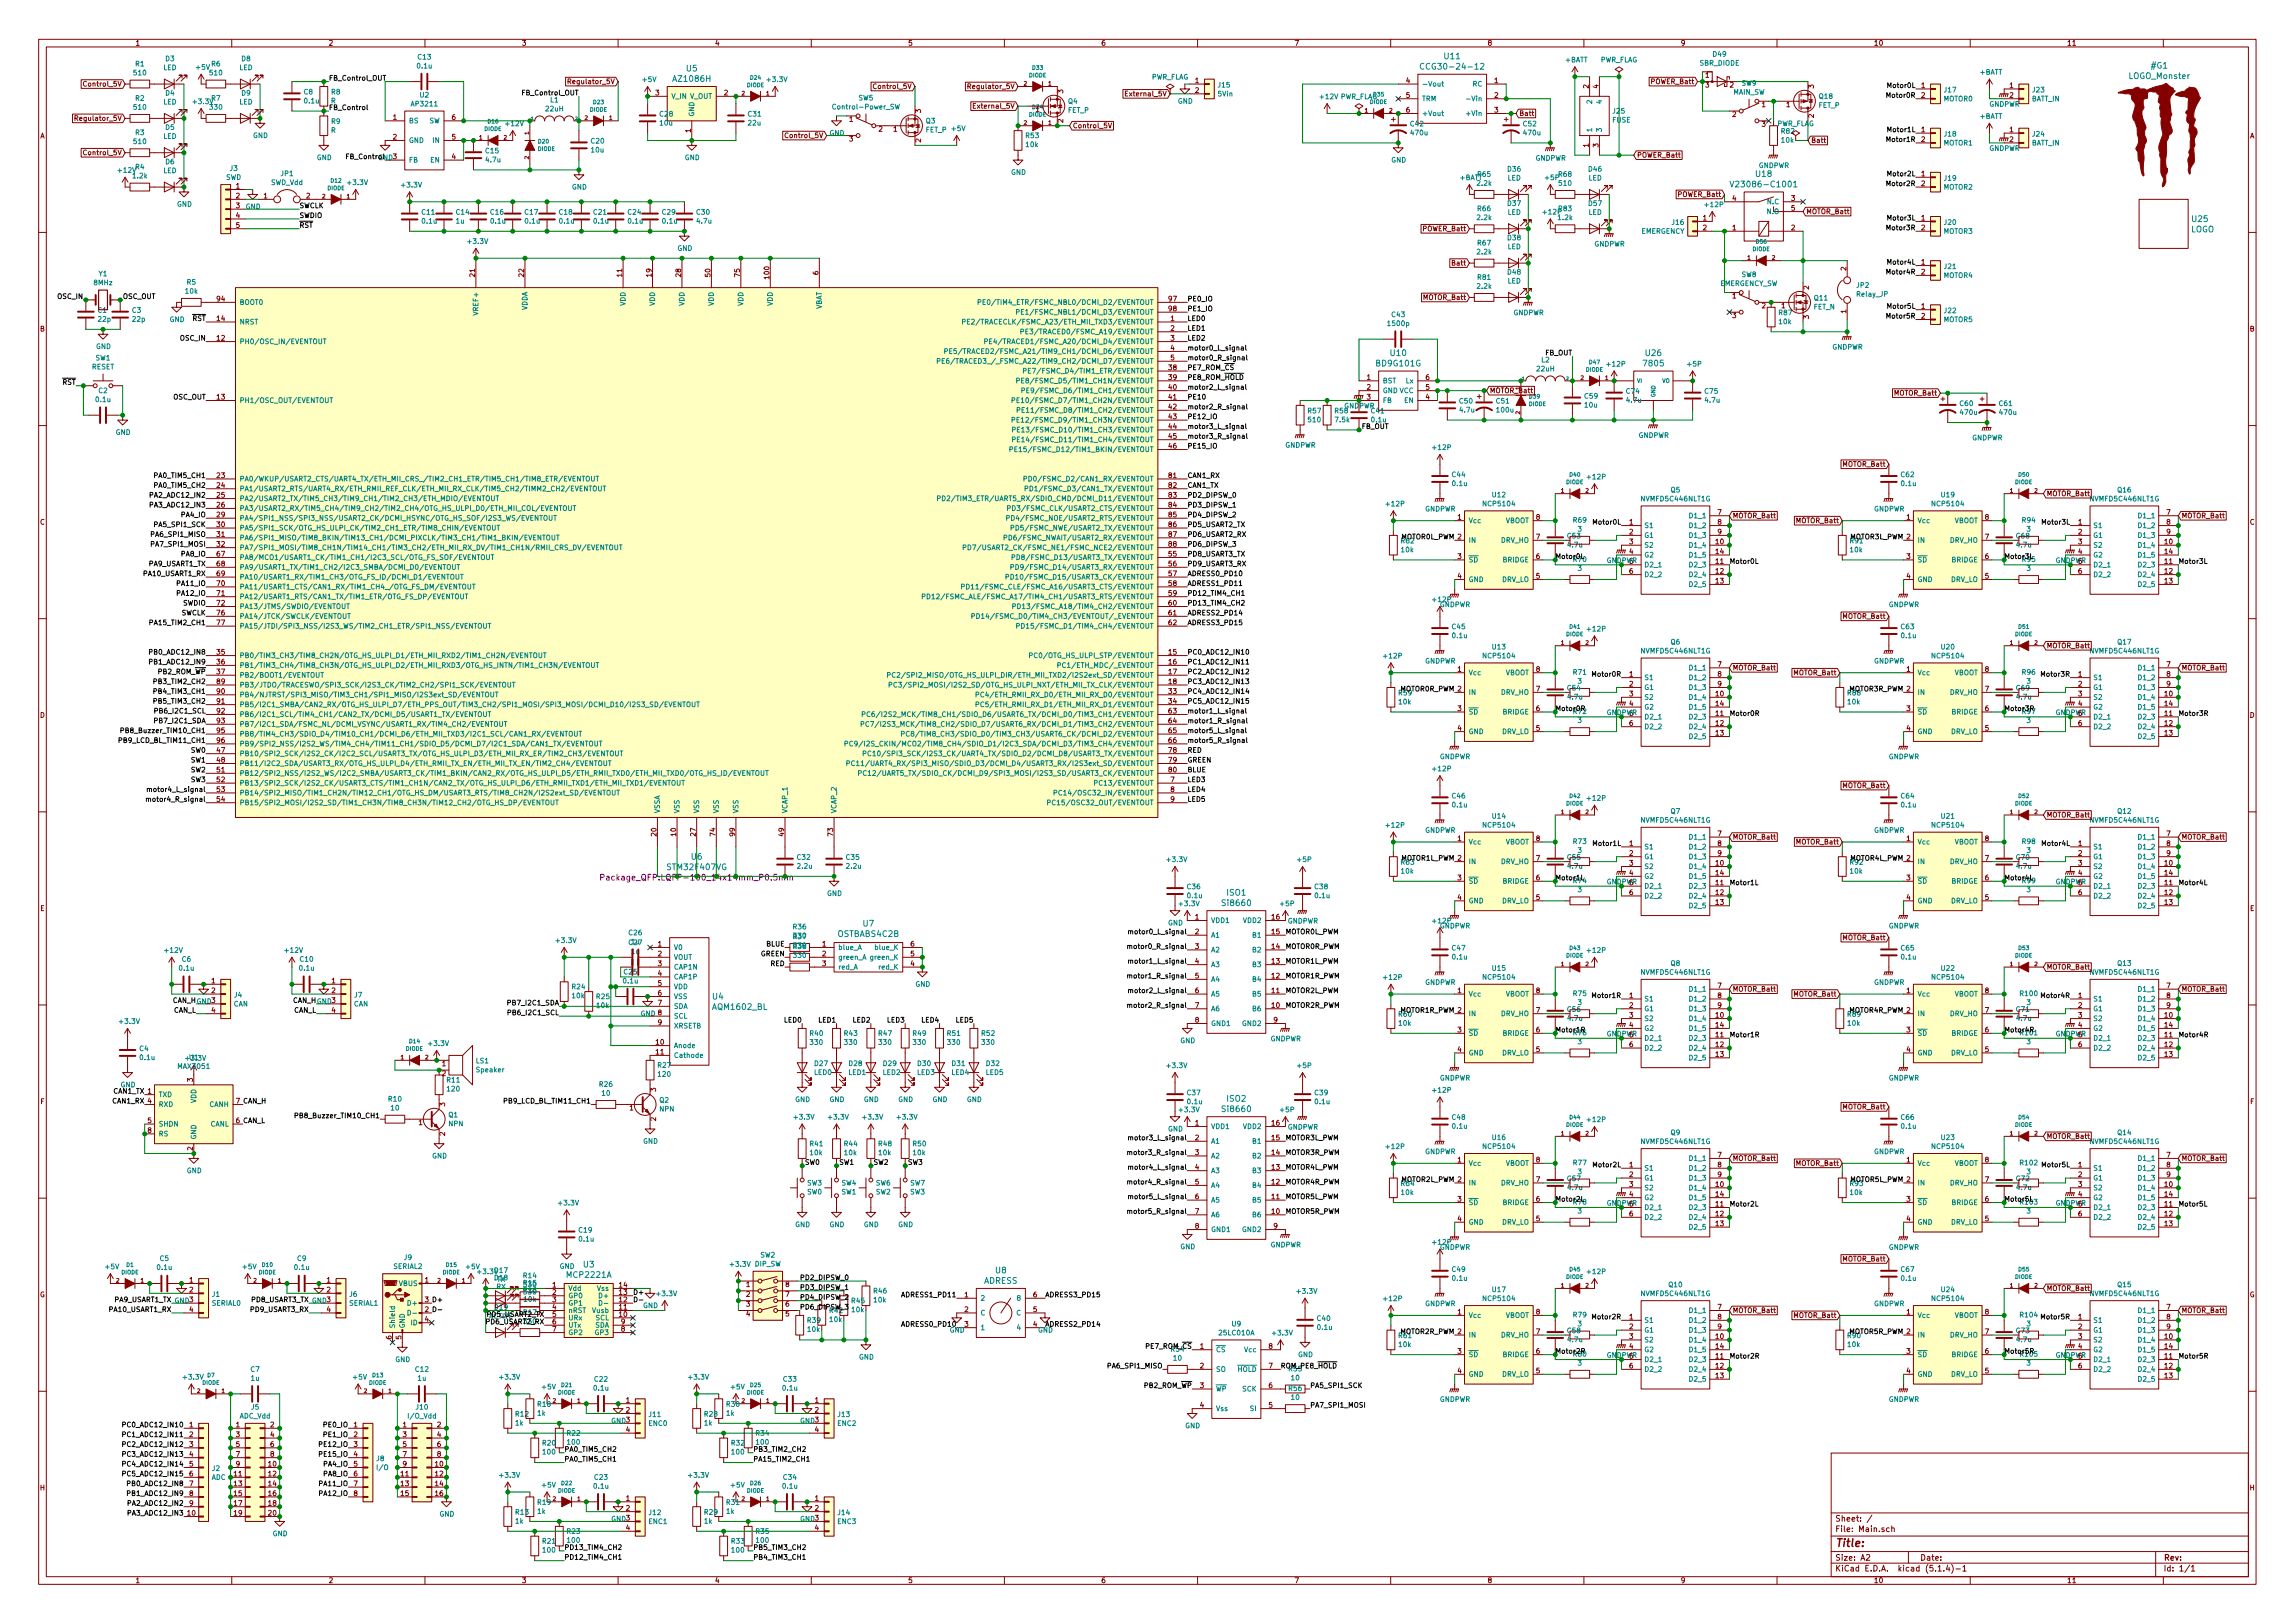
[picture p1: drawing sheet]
<svg xmlns="http://www.w3.org/2000/svg" width="594mm" height="420mm" viewBox="0 0 594 420" stroke-linecap="round" stroke-linejoin="round" font-family="sans-serif">
<defs><g id="words">
<text font-size="2.8" fill="#840000" x="475" y="400.4">Title:</text>
<g font-size="2.1" fill="#008484">
<text x="374" y="15.3">U11</text>
<text x="556.9" y="17.7">#G1</text>
<text x="174.5" y="21.2">AZ1086H</text>
<text x="177.7" y="18.5">U5</text>
<text x="369.3" y="18">CCG30-24-12</text>
<text x="551.1" y="20.4">LOGO_Monster</text>
<text x="454.6" y="45.8">U18</text>
<text x="449.4" y="48.5">V23086-C1001</text>
<text x="567.5" y="57.4">U25</text>
<text x="567.1" y="60.1">LOGO</text>
<text x="356.4" y="94.8">BD9G101G</text>
<text x="360" y="92.1">U10</text>
<text x="425.6" y="94.8">7805</text>
<text x="426.1" y="92.1">U26</text>
<text x="173" y="225.2">STM32F407VG</text>
<text x="179" y="222.5">U6</text>
<text x="317.6" y="231.8">ISO1</text>
<text x="223.4" y="239.8">U7</text>
<text x="316.7" y="234.5">Si8660</text>
<text x="216.9" y="242.5">OSTBABS4C2B</text>
<text x="184.5" y="258.7">U4</text>
<text x="184.7" y="261.4">AQM1602_BL</text>
<text x="316.7" y="287.9">Si8660</text>
<text x="317.6" y="285.2">ISO2</text>
<text x="151.1" y="328.1">U3</text>
<text x="257.7" y="329.6">U8</text>
<text x="146.9" y="330.8">MCP2221A</text>
<text x="254.7" y="332.3">ADRESS</text>
</g>
<text font-size="2.1" fill="#008400" x="157.9" y="227.9">Package_QFP:LQFP-100_14x14mm_P0.5mm</text>
<g font-size="2.1" fill="#840000">
<text x="475" y="393.9">Sheet: /</text>
<text x="475" y="396.6">File: Main.sch</text>
<text x="475" y="406.8">KiCad E.D.A. kicad (5.1.4)-1</text>
<text x="475" y="404">Size: A2</text>
<text x="497" y="404">Date:</text>
<text x="560" y="404">Rev:</text>
<text x="560" y="406.8">Id: 1/1</text>
</g>
<g font-size="1.8" fill="#840000">
<text x="35" y="11.8">1</text>
<text x="85" y="11.8">2</text>
<text x="135" y="11.8">3</text>
<text x="185" y="11.8">4</text>
<text x="235" y="11.8">5</text>
<text x="285" y="11.8">6</text>
<text x="335" y="11.8">7</text>
<text x="385" y="11.8">8</text>
<text x="435" y="11.8">9</text>
<text x="485" y="11.8">10</text>
<text x="535" y="11.8">11</text>
<text x="22.2" y="22.4">Control_5V</text>
<text x="147.8" y="21.8">Regulator_5V</text>
<text x="226.6" y="23">Control_5V</text>
<text x="251.3" y="23">Regulator_5V</text>
<text x="309.4" y="21.5">1</text>
<text x="364" y="21.5">4</text>
<text x="386.9" y="21.5">1</text>
<text x="411.2" y="22.9" transform="rotate(-90 411.2 22.9)">2</text>
<text x="413.8" y="22.9" transform="rotate(-90 413.8 22.9)">4</text>
<text x="427.5" y="21.8">POWER_Batt</text>
<text x="441.5" y="20.1">1</text>
<text x="441.5" y="22.6">3</text>
<text x="447.8" y="22.6">2</text>
<text x="469.5" y="22.9" transform="rotate(-90 469.5 22.9)">3</text>
<text x="497.4" y="22.8">1</text>
<text x="520.2" y="22.8">1</text>
<text x="169.7" y="24.7">3</text>
<text x="187.5" y="24.7">2</text>
<text x="238.4" y="29.2" transform="rotate(-90 238.4 29.2)">3</text>
<text x="252.6" y="28.1">External_5V</text>
<text x="268.1" y="29">1</text>
<text x="275.2" y="24.1" transform="rotate(-90 275.2 24.1)">3</text>
<text x="292" y="24.9">External_5V</text>
<text x="309.4" y="24">2</text>
<text x="364" y="25.3">5</text>
<text x="364" y="29.1">6</text>
<text x="386.9" y="25.3">2</text>
<text x="386.9" y="29.1">3</text>
<text x="456.1" y="27.7">1</text>
<text x="462.4" y="27.7">1</text>
<text x="497.4" y="25.3">2</text>
<text x="520.2" y="25.3">2</text>
<text x="10.4" y="35.8">A</text>
<text x="20.2" y="31.3">Regulator_5V</text>
<text x="101.8" y="31">1</text>
<text x="117" y="31">6</text>
<text x="178.8" y="34.3" transform="rotate(-90 178.8 34.3)">1</text>
<text x="203.8" y="35.7">Control_5V</text>
<text x="219.9" y="31.5">1</text>
<text x="227.5" y="34.1">2</text>
<text x="231.3" y="34.1">1</text>
<text x="275.2" y="31.8" transform="rotate(-90 275.2 31.8)">2</text>
<text x="277.6" y="33.2">Control_5V</text>
<text x="393.2" y="30">Batt</text>
<text x="448.5" y="30.3">2</text>
<text x="456.1" y="32.8">3</text>
<text x="469.5" y="30.5" transform="rotate(-90 469.5 30.5)">2</text>
<text x="497.4" y="34.2">1</text>
<text x="520.2" y="34.2">1</text>
<text x="582.4" y="35.8">A</text>
<text x="22.2" y="40.2">Control_5V</text>
<text x="101.8" y="36.1">2</text>
<text x="117" y="41.2">4</text>
<text x="117" y="36.1">5</text>
<text x="219.9" y="36.6">3</text>
<text x="238.4" y="36.8" transform="rotate(-90 238.4 36.8)">2</text>
<text x="411.2" y="38.1" transform="rotate(-90 411.2 38.1)">1</text>
<text x="413.8" y="38.1" transform="rotate(-90 413.8 38.1)">3</text>
<text x="423.7" y="40.8">POWER_Batt</text>
<text x="468.8" y="37">Batt</text>
<text x="497.4" y="36.7">2</text>
<text x="520.2" y="36.7">2</text>
<text x="497.4" y="45.6">1</text>
<text x="61.1" y="48.8">1</text>
<text x="61.1" y="51.4">2</text>
<text x="61.1" y="53.9">3</text>
<text x="68.3" y="51.4">1</text>
<text x="79.3" y="51.4">2</text>
<text x="434.5" y="51">POWER_Batt</text>
<text x="448.5" y="52">4</text>
<text x="463.7" y="52">3</text>
<text x="497.4" y="48.2">2</text>
<text x="61.1" y="56.4">4</text>
<text x="61.1" y="59">5</text>
<text x="368.5" y="59.9">POWER_Batt</text>
<text x="440.8" y="57.1">1</text>
<text x="440.8" y="59.6">2</text>
<text x="448.5" y="59.6">1</text>
<text x="463.7" y="59.6">2</text>
<text x="463.7" y="54.5">5</text>
<text x="467.5" y="55.4">MOTOR_Batt</text>
<text x="497.4" y="57.1">1</text>
<text x="497.4" y="59.6">2</text>
<text x="122.9" y="71.6" transform="rotate(-90 122.9 71.6)">21</text>
<text x="135.6" y="71.6" transform="rotate(-90 135.6 71.6)">22</text>
<text x="161" y="71.6" transform="rotate(-90 161 71.6)">11</text>
<text x="168.7" y="71.6" transform="rotate(-90 168.7 71.6)">19</text>
<text x="176.3" y="71.6" transform="rotate(-90 176.3 71.6)">28</text>
<text x="183.9" y="71.6" transform="rotate(-90 183.9 71.6)">50</text>
<text x="191.5" y="71.6" transform="rotate(-90 191.5 71.6)">75</text>
<text x="211.8" y="71.1" transform="rotate(-90 211.8 71.1)">6</text>
<text x="376.1" y="68.7">Batt</text>
<text x="477.9" y="70" transform="rotate(-90 477.9 70)">2</text>
<text x="497.4" y="68.5">1</text>
<text x="497.4" y="71">2</text>
<text x="199.1" y="72.1" transform="rotate(-90 199.1 72.1)">100</text>
<text x="368.6" y="77.6">MOTOR_Batt</text>
<text x="448.5" y="77.3">1</text>
<text x="468.2" y="74.9" transform="rotate(-90 468.2 74.9)">2</text>
<text x="56.2" y="83.1">14</text>
<text x="56.2" y="78">94</text>
<text x="302.6" y="78">97</text>
<text x="302.6" y="80.6">98</text>
<text x="303" y="83.1">1</text>
<text x="448.5" y="82.3">3</text>
<text x="456.1" y="79.8">2</text>
<text x="461.2" y="79.8">1</text>
<text x="468.2" y="82.6" transform="rotate(-90 468.2 82.6)">3</text>
<text x="477.9" y="81.1" transform="rotate(-90 477.9 81.1)">1</text>
<text x="497.4" y="79.9">1</text>
<text x="497.4" y="82.5">2</text>
<text x="10.4" y="85.8">B</text>
<text x="56.2" y="88.2">12</text>
<text x="303" y="85.6">2</text>
<text x="303" y="88.2">3</text>
<text x="582.4" y="85.8">B</text>
<text x="302.6" y="95.8">38</text>
<text x="303" y="90.7">4</text>
<text x="303" y="93.3">5</text>
<text x="302.6" y="98.3">39</text>
<text x="302.6" y="100.9">40</text>
<text x="353.8" y="98.3">1</text>
<text x="353.8" y="100.9">2</text>
<text x="369.1" y="100.9">5</text>
<text x="369.1" y="98.3">6</text>
<text x="385.6" y="101.8">MOTOR_Batt</text>
<text x="56.2" y="103.4">13</text>
<text x="302.6" y="103.4">41</text>
<text x="302.6" y="106">42</text>
<text x="353.8" y="103.4">3</text>
<text x="369.1" y="103.4">4</text>
<text x="490.5" y="102.4">MOTOR_Batt</text>
<text x="302.6" y="108.5">43</text>
<text x="302.6" y="111">44</text>
<text x="302.6" y="113.6">45</text>
<text x="302.6" y="116.1">46</text>
<text x="56.2" y="123.7">23</text>
<text x="302.6" y="123.7">81</text>
<text x="477.2" y="120.8">MOTOR_Batt</text>
<text x="56.2" y="126.3">24</text>
<text x="56.2" y="128.8">25</text>
<text x="56.2" y="131.4">26</text>
<text x="302.6" y="126.3">82</text>
<text x="302.6" y="128.8">83</text>
<text x="302.6" y="131.4">84</text>
<text x="529.7" y="128.4">MOTOR_Batt</text>
<text x="10.4" y="135.8">C</text>
<text x="56.2" y="133.9">29</text>
<text x="56.2" y="136.4">30</text>
<text x="302.6" y="133.9">85</text>
<text x="302.6" y="136.4">86</text>
<text x="377.3" y="134.5">1</text>
<text x="397.7" y="134.5">8</text>
<text x="421.8" y="135.8">1</text>
<text x="444.7" y="133.3">7</text>
<text x="444.7" y="135.8">8</text>
<text x="448.5" y="134.2">MOTOR_Batt</text>
<text x="465.1" y="135.4">MOTOR_Batt</text>
<text x="493.5" y="134.5">1</text>
<text x="513.9" y="134.5">8</text>
<text x="538" y="135.8">1</text>
<text x="560.9" y="133.3">7</text>
<text x="560.9" y="135.8">8</text>
<text x="564.7" y="134.2">MOTOR_Batt</text>
<text x="582.4" y="135.8">C</text>
<text x="56.2" y="139">31</text>
<text x="56.2" y="141.5">32</text>
<text x="302.6" y="139">87</text>
<text x="302.6" y="141.5">88</text>
<text x="397.7" y="139.6">7</text>
<text x="421.8" y="138.3">2</text>
<text x="421.8" y="140.9">3</text>
<text x="421.8" y="143.4">4</text>
<text x="444.2" y="140.9">10</text>
<text x="444.2" y="143.4">14</text>
<text x="444.7" y="138.3">9</text>
<text x="513.9" y="139.6">7</text>
<text x="538" y="138.3">2</text>
<text x="538" y="140.9">3</text>
<text x="538" y="143.4">4</text>
<text x="560.4" y="140.9">10</text>
<text x="560.4" y="143.4">14</text>
<text x="560.9" y="138.3">9</text>
<text x="56.2" y="144.1">67</text>
<text x="56.2" y="146.6">68</text>
<text x="56.2" y="149.1">69</text>
<text x="302.6" y="144.1">55</text>
<text x="302.6" y="146.6">56</text>
<text x="302.6" y="149.1">57</text>
<text x="377.3" y="144.7">3</text>
<text x="377.3" y="149.8">4</text>
<text x="397.7" y="149.8">5</text>
<text x="397.7" y="144.7">6</text>
<text x="421.8" y="146">5</text>
<text x="421.8" y="148.5">6</text>
<text x="444.2" y="146">11</text>
<text x="444.2" y="148.5">12</text>
<text x="493.5" y="144.7">3</text>
<text x="493.5" y="149.8">4</text>
<text x="513.9" y="149.8">5</text>
<text x="513.9" y="144.7">6</text>
<text x="538" y="146">5</text>
<text x="538" y="148.5">6</text>
<text x="560.4" y="146">11</text>
<text x="560.4" y="148.5">12</text>
<text x="56.2" y="151.7">70</text>
<text x="56.2" y="154.2">71</text>
<text x="302.6" y="151.7">58</text>
<text x="302.6" y="154.2">59</text>
<text x="444.2" y="151">13</text>
<text x="560.4" y="151">13</text>
<text x="56.2" y="156.8">72</text>
<text x="56.2" y="159.3">76</text>
<text x="56.2" y="161.8">77</text>
<text x="302.6" y="156.8">60</text>
<text x="302.6" y="159.3">61</text>
<text x="302.6" y="161.8">62</text>
<text x="477.2" y="160.2">MOTOR_Batt</text>
<text x="529.7" y="167.8">MOTOR_Batt</text>
<text x="56.2" y="169.5">35</text>
<text x="56.2" y="172">36</text>
<text x="302.6" y="169.5">15</text>
<text x="302.6" y="172">16</text>
<text x="377.3" y="173.9">1</text>
<text x="397.7" y="173.9">8</text>
<text x="444.7" y="172.6">7</text>
<text x="448.5" y="173.5">MOTOR_Batt</text>
<text x="493.5" y="173.9">1</text>
<text x="513.9" y="173.9">8</text>
<text x="560.9" y="172.6">7</text>
<text x="564.7" y="173.5">MOTOR_Batt</text>
<text x="56.2" y="174.5">37</text>
<text x="56.2" y="177.1">89</text>
<text x="56.2" y="179.6">90</text>
<text x="302.6" y="174.5">17</text>
<text x="302.6" y="177.1">18</text>
<text x="302.6" y="179.6">33</text>
<text x="397.7" y="179">7</text>
<text x="421.8" y="175.2">1</text>
<text x="421.8" y="177.7">2</text>
<text x="444.7" y="175.2">8</text>
<text x="444.7" y="177.7">9</text>
<text x="464.5" y="174.8">MOTOR_Batt</text>
<text x="513.9" y="179">7</text>
<text x="538" y="175.2">1</text>
<text x="538" y="177.7">2</text>
<text x="560.9" y="175.2">8</text>
<text x="560.9" y="177.7">9</text>
<text x="10.4" y="185.8">D</text>
<text x="56.2" y="182.2">91</text>
<text x="56.2" y="184.7">92</text>
<text x="302.6" y="182.2">34</text>
<text x="302.6" y="184.7">63</text>
<text x="377.3" y="184.1">3</text>
<text x="397.7" y="184.1">6</text>
<text x="421.8" y="180.3">3</text>
<text x="421.8" y="182.8">4</text>
<text x="421.8" y="185.3">5</text>
<text x="444.2" y="180.3">10</text>
<text x="444.2" y="185.3">11</text>
<text x="444.2" y="182.8">14</text>
<text x="493.5" y="184.1">3</text>
<text x="513.9" y="184.1">6</text>
<text x="538" y="180.3">3</text>
<text x="538" y="182.8">4</text>
<text x="538" y="185.3">5</text>
<text x="560.4" y="180.3">10</text>
<text x="560.4" y="185.3">11</text>
<text x="560.4" y="182.8">14</text>
<text x="582.4" y="185.8">D</text>
<text x="56.2" y="187.2">93</text>
<text x="56.2" y="189.8">95</text>
<text x="302.6" y="187.2">64</text>
<text x="302.6" y="189.8">65</text>
<text x="377.3" y="189.1">4</text>
<text x="397.7" y="189.1">5</text>
<text x="421.8" y="187.9">6</text>
<text x="444.2" y="187.9">12</text>
<text x="444.2" y="190.4">13</text>
<text x="493.5" y="189.1">4</text>
<text x="513.9" y="189.1">5</text>
<text x="538" y="187.9">6</text>
<text x="560.4" y="187.9">12</text>
<text x="560.4" y="190.4">13</text>
<text x="56.2" y="194.9">47</text>
<text x="56.2" y="197.4">48</text>
<text x="56.2" y="192.3">96</text>
<text x="302.6" y="192.3">66</text>
<text x="302.6" y="194.9">78</text>
<text x="302.6" y="197.4">79</text>
<text x="56.2" y="199.9">51</text>
<text x="56.2" y="202.5">52</text>
<text x="302.6" y="199.9">80</text>
<text x="303" y="202.5">7</text>
<text x="56.2" y="205">53</text>
<text x="56.2" y="207.6">54</text>
<text x="303" y="205">8</text>
<text x="303" y="207.6">9</text>
<text x="477.2" y="204">MOTOR_Batt</text>
<text x="529.7" y="211.6">MOTOR_Batt</text>
<text x="169.9" y="216.4" transform="rotate(-90 169.9 216.4)">20</text>
<text x="175" y="216.4" transform="rotate(-90 175 216.4)">10</text>
<text x="180.1" y="216.4" transform="rotate(-90 180.1 216.4)">27</text>
<text x="185.2" y="216.4" transform="rotate(-90 185.2 216.4)">74</text>
<text x="190.2" y="216.4" transform="rotate(-90 190.2 216.4)">99</text>
<text x="202.9" y="216.4" transform="rotate(-90 202.9 216.4)">49</text>
<text x="215.6" y="216.4" transform="rotate(-90 215.6 216.4)">73</text>
<text x="377.3" y="217.7">1</text>
<text x="397.7" y="217.7">8</text>
<text x="421.8" y="219">1</text>
<text x="421.8" y="221.5">2</text>
<text x="444.7" y="216.5">7</text>
<text x="444.7" y="219">8</text>
<text x="444.7" y="221.5">9</text>
<text x="448.5" y="217.3">MOTOR_Batt</text>
<text x="465.1" y="218.6">MOTOR_Batt</text>
<text x="493.5" y="217.7">1</text>
<text x="513.9" y="217.7">8</text>
<text x="538" y="219">1</text>
<text x="538" y="221.5">2</text>
<text x="560.9" y="216.5">7</text>
<text x="560.9" y="219">8</text>
<text x="560.9" y="221.5">9</text>
<text x="564.7" y="217.3">MOTOR_Batt</text>
<text x="377.3" y="227.9">3</text>
<text x="397.7" y="227.9">6</text>
<text x="397.7" y="222.8">7</text>
<text x="421.8" y="224.1">3</text>
<text x="421.8" y="226.6">4</text>
<text x="444.2" y="224.1">10</text>
<text x="444.2" y="226.6">14</text>
<text x="493.5" y="227.9">3</text>
<text x="513.9" y="227.9">6</text>
<text x="513.9" y="222.8">7</text>
<text x="538" y="224.1">3</text>
<text x="538" y="226.6">4</text>
<text x="560.4" y="224.1">10</text>
<text x="560.4" y="226.6">14</text>
<text x="377.3" y="233">4</text>
<text x="397.7" y="233">5</text>
<text x="421.8" y="229.2">5</text>
<text x="421.8" y="231.7">6</text>
<text x="444.2" y="229.2">11</text>
<text x="444.2" y="231.7">12</text>
<text x="493.5" y="233">4</text>
<text x="513.9" y="233">5</text>
<text x="538" y="229.2">5</text>
<text x="538" y="231.7">6</text>
<text x="560.4" y="229.2">11</text>
<text x="560.4" y="231.7">12</text>
<text x="10.4" y="235.8">E</text>
<text x="309.4" y="238">1</text>
<text x="329.2" y="238">16</text>
<text x="444.2" y="234.2">13</text>
<text x="560.4" y="234.2">13</text>
<text x="582.4" y="235.8">E</text>
<text x="170.3" y="245">1</text>
<text x="212.9" y="245">1</text>
<text x="235.7" y="245">6</text>
<text x="309.4" y="241.9">2</text>
<text x="309.4" y="245.7">3</text>
<text x="329.2" y="245.7">14</text>
<text x="329.2" y="241.9">15</text>
<text x="477.2" y="243.4">MOTOR_Batt</text>
<text x="170.3" y="247.6">2</text>
<text x="170.3" y="250.1">3</text>
<text x="212.9" y="247.6">2</text>
<text x="212.9" y="250.1">3</text>
<text x="235.7" y="250.1">4</text>
<text x="235.7" y="247.6">5</text>
<text x="309.4" y="249.5">4</text>
<text x="329.2" y="249.5">13</text>
<text x="529.7" y="251">MOTOR_Batt</text>
<text x="54.8" y="254.6">1</text>
<text x="54.8" y="257.1">2</text>
<text x="85.9" y="254.6">1</text>
<text x="85.9" y="257.1">2</text>
<text x="170.3" y="252.6">4</text>
<text x="170.3" y="255.2">5</text>
<text x="170.3" y="257.7">6</text>
<text x="309.4" y="253.3">5</text>
<text x="309.4" y="257.1">6</text>
<text x="329.2" y="257.1">11</text>
<text x="329.2" y="253.3">12</text>
<text x="377.3" y="257.1">1</text>
<text x="397.7" y="257.1">8</text>
<text x="444.7" y="255.8">7</text>
<text x="448.5" y="256.7">MOTOR_Batt</text>
<text x="464.5" y="258">MOTOR_Batt</text>
<text x="493.5" y="257.1">1</text>
<text x="513.9" y="257.1">8</text>
<text x="560.9" y="255.8">7</text>
<text x="564.7" y="256.7">MOTOR_Batt</text>
<text x="54.8" y="262.2">4</text>
<text x="85.9" y="262.2">4</text>
<text x="165.8" y="263.1">GND 8</text>
<text x="170.3" y="260.3">7</text>
<text x="309.4" y="260.9">7</text>
<text x="329.2" y="260.9">10</text>
<text x="397.7" y="262.2">7</text>
<text x="421.8" y="258.4">1</text>
<text x="421.8" y="260.9">2</text>
<text x="421.8" y="263.4">3</text>
<text x="444.2" y="263.4">10</text>
<text x="444.7" y="258.4">8</text>
<text x="444.7" y="260.9">9</text>
<text x="513.9" y="262.2">7</text>
<text x="538" y="258.4">1</text>
<text x="538" y="260.9">2</text>
<text x="538" y="263.4">3</text>
<text x="560.4" y="263.4">10</text>
<text x="560.9" y="258.4">8</text>
<text x="560.9" y="260.9">9</text>
<text x="170.3" y="265.3">9</text>
<text x="309.4" y="264.7">8</text>
<text x="329.7" y="264.7">9</text>
<text x="377.3" y="267.3">3</text>
<text x="397.7" y="267.3">6</text>
<text x="421.8" y="266">4</text>
<text x="421.8" y="268.5">5</text>
<text x="444.2" y="268.5">11</text>
<text x="444.2" y="266">14</text>
<text x="493.5" y="267.3">3</text>
<text x="513.9" y="267.3">6</text>
<text x="538" y="266">4</text>
<text x="538" y="268.5">5</text>
<text x="560.4" y="268.5">11</text>
<text x="560.4" y="266">14</text>
<text x="169.8" y="270.4">10</text>
<text x="169.8" y="273">11</text>
<text x="377.3" y="272.3">4</text>
<text x="397.7" y="272.3">5</text>
<text x="421.8" y="271.1">6</text>
<text x="444.2" y="271.1">12</text>
<text x="444.2" y="273.6">13</text>
<text x="493.5" y="272.3">4</text>
<text x="513.9" y="272.3">5</text>
<text x="538" y="271.1">6</text>
<text x="560.4" y="271.1">12</text>
<text x="560.4" y="273.6">13</text>
<text x="49.9" y="280.1" transform="rotate(-90 49.9 280.1)">3</text>
<text x="114.5" y="276">1</text>
<text x="114.5" y="278.6">2</text>
<text x="10.5" y="285.8">F</text>
<text x="115.2" y="286.4" transform="rotate(-90 115.2 286.4)">3</text>
<text x="163" y="287.4">1</text>
<text x="169.8" y="282.6" transform="rotate(-90 169.8 282.6)">3</text>
<text x="477.2" y="287.2">MOTOR_Batt</text>
<text x="582.5" y="285.8">F</text>
<text x="38.3" y="290.7">5</text>
<text x="38.3" y="293.3">8</text>
<text x="108.4" y="291.3">1</text>
<text x="169.8" y="290.2" transform="rotate(-90 169.8 290.2)">2</text>
<text x="309.4" y="291.4">1</text>
<text x="329.2" y="291.4">16</text>
<text x="49.9" y="297.8" transform="rotate(-90 49.9 297.8)">2</text>
<text x="115.2" y="294" transform="rotate(-90 115.2 294)">2</text>
<text x="309.4" y="295.2">2</text>
<text x="309.4" y="299">3</text>
<text x="329.2" y="299">14</text>
<text x="329.2" y="295.2">15</text>
<text x="444.7" y="299.6">7</text>
<text x="529.7" y="294.8">MOTOR_Batt</text>
<text x="560.9" y="299.6">7</text>
<text x="309.4" y="302.8">4</text>
<text x="329.2" y="302.8">13</text>
<text x="377.3" y="300.9">1</text>
<text x="397.7" y="306">7</text>
<text x="397.7" y="300.9">8</text>
<text x="421.8" y="302.2">1</text>
<text x="421.8" y="304.7">2</text>
<text x="444.7" y="302.2">8</text>
<text x="444.7" y="304.7">9</text>
<text x="448.5" y="300.5">MOTOR_Batt</text>
<text x="465.1" y="301.8">MOTOR_Batt</text>
<text x="493.5" y="300.9">1</text>
<text x="513.9" y="306">7</text>
<text x="513.9" y="300.9">8</text>
<text x="538" y="302.2">1</text>
<text x="538" y="304.7">2</text>
<text x="560.9" y="302.2">8</text>
<text x="560.9" y="304.7">9</text>
<text x="564.7" y="300.5">MOTOR_Batt</text>
<text x="309.4" y="306.6">5</text>
<text x="309.4" y="310.4">6</text>
<text x="329.2" y="310.4">11</text>
<text x="329.2" y="306.6">12</text>
<text x="377.3" y="311.1">3</text>
<text x="397.7" y="311.1">6</text>
<text x="421.8" y="307.3">3</text>
<text x="421.8" y="309.8">4</text>
<text x="444.2" y="307.3">10</text>
<text x="444.2" y="309.8">14</text>
<text x="493.5" y="311.1">3</text>
<text x="513.9" y="311.1">6</text>
<text x="538" y="307.3">3</text>
<text x="538" y="309.8">4</text>
<text x="560.4" y="307.3">10</text>
<text x="560.4" y="309.8">14</text>
<text x="309.4" y="314.2">7</text>
<text x="329.2" y="314.2">10</text>
<text x="377.3" y="316.1">4</text>
<text x="397.7" y="316.1">5</text>
<text x="421.8" y="312.3">5</text>
<text x="421.8" y="314.9">6</text>
<text x="444.2" y="312.3">11</text>
<text x="444.2" y="314.9">12</text>
<text x="444.2" y="317.4">13</text>
<text x="493.5" y="316.1">4</text>
<text x="513.9" y="316.1">5</text>
<text x="538" y="312.3">5</text>
<text x="538" y="314.9">6</text>
<text x="560.4" y="312.3">11</text>
<text x="560.4" y="314.9">12</text>
<text x="560.4" y="317.4">13</text>
<text x="309.4" y="318.1">8</text>
<text x="329.7" y="318.1">9</text>
<text x="477.2" y="326.6">MOTOR_Batt</text>
<text x="10.3" y="335.8">G</text>
<text x="49" y="332">1</text>
<text x="49" y="334.6">2</text>
<text x="84.6" y="332">1</text>
<text x="84.6" y="334.6">2</text>
<text x="110" y="332">1</text>
<text x="143" y="333.3">1</text>
<text x="143" y="335.2">2</text>
<text x="160.3" y="335.2">13</text>
<text x="160.3" y="333.3">14</text>
<text x="193.2" y="333.2">1</text>
<text x="193.2" y="335.7">2</text>
<text x="203.4" y="335.7">7</text>
<text x="203.4" y="333.2">8</text>
<text x="249.7" y="335.8">1</text>
<text x="267.5" y="335.8">6</text>
<text x="529.7" y="334.2">MOTOR_Batt</text>
<text x="582.3" y="335.8">G</text>
<text x="49" y="339.6">4</text>
<text x="84.6" y="339.6">4</text>
<text x="128.1" y="339.1">D19</text>
<text x="143" y="337.1">3</text>
<text x="143" y="339">4</text>
<text x="143" y="340.9">5</text>
<text x="160.3" y="340.9">10</text>
<text x="160.3" y="339">11</text>
<text x="160.3" y="337.1">12</text>
<text x="193.2" y="338.2">3</text>
<text x="193.2" y="340.8">4</text>
<text x="203.4" y="340.8">5</text>
<text x="203.4" y="338.2">6</text>
<text x="249.7" y="339.6">2</text>
<text x="267.5" y="339.6">5</text>
<text x="377.3" y="340.3">1</text>
<text x="397.7" y="340.3">8</text>
<text x="421.8" y="341.5">1</text>
<text x="444.7" y="339">7</text>
<text x="444.7" y="341.5">8</text>
<text x="448.5" y="339.9">MOTOR_Batt</text>
<text x="464.5" y="341.2">MOTOR_Batt</text>
<text x="493.5" y="340.3">1</text>
<text x="513.9" y="340.3">8</text>
<text x="538" y="341.5">1</text>
<text x="560.9" y="339">7</text>
<text x="560.9" y="341.5">8</text>
<text x="564.7" y="339.9">MOTOR_Batt</text>
<text x="101.3" y="346.7" transform="rotate(-90 101.3 346.7)">6</text>
<text x="103.9" y="346.7" transform="rotate(-90 103.9 346.7)">5</text>
<text x="110" y="342.2">4</text>
<text x="143" y="342.8">6</text>
<text x="143" y="344.7">7</text>
<text x="160.8" y="344.7">8</text>
<text x="160.8" y="342.8">9</text>
<text x="249.7" y="343.5">3</text>
<text x="267.5" y="343.5">4</text>
<text x="397.7" y="345.4">7</text>
<text x="421.8" y="344.1">2</text>
<text x="421.8" y="346.6">3</text>
<text x="444.2" y="346.6">10</text>
<text x="444.7" y="344.1">9</text>
<text x="513.9" y="345.4">7</text>
<text x="538" y="344.1">2</text>
<text x="538" y="346.6">3</text>
<text x="560.4" y="346.6">10</text>
<text x="560.9" y="344.1">9</text>
<text x="310.7" y="349.2">1</text>
<text x="328.4" y="349.2">8</text>
<text x="377.3" y="350.4">3</text>
<text x="397.7" y="350.4">6</text>
<text x="421.8" y="349.2">4</text>
<text x="421.8" y="351.7">5</text>
<text x="444.2" y="351.7">11</text>
<text x="444.2" y="349.2">14</text>
<text x="493.5" y="350.4">3</text>
<text x="513.9" y="350.4">6</text>
<text x="538" y="349.2">4</text>
<text x="538" y="351.7">5</text>
<text x="560.4" y="351.7">11</text>
<text x="560.4" y="349.2">14</text>
<text x="310.7" y="354.2">2</text>
<text x="310.7" y="359.3">3</text>
<text x="328.4" y="359.3">6</text>
<text x="328.4" y="354.2">7</text>
<text x="377.3" y="355.5">4</text>
<text x="397.7" y="355.5">5</text>
<text x="421.8" y="354.2">6</text>
<text x="444.2" y="354.2">12</text>
<text x="444.2" y="356.8">13</text>
<text x="493.5" y="355.5">4</text>
<text x="513.9" y="355.5">5</text>
<text x="538" y="354.2">6</text>
<text x="560.4" y="354.2">12</text>
<text x="560.4" y="356.8">13</text>
<text x="162.1" y="363.1">1</text>
<text x="162.1" y="365.7">2</text>
<text x="211" y="363.1">1</text>
<text x="211" y="365.7">2</text>
<text x="310.7" y="364.4">4</text>
<text x="328.4" y="364.4">5</text>
<text x="49" y="369.5">1</text>
<text x="61.1" y="369.5">1</text>
<text x="70" y="369.5">2</text>
<text x="91.6" y="369.5">1</text>
<text x="104.3" y="369.5">1</text>
<text x="113.2" y="369.5">2</text>
<text x="162.1" y="370.8">4</text>
<text x="211" y="370.8">4</text>
<text x="49" y="372">2</text>
<text x="49" y="374.6">3</text>
<text x="49" y="377.1">4</text>
<text x="61.1" y="372">3</text>
<text x="61.1" y="374.6">5</text>
<text x="61.1" y="377.1">7</text>
<text x="70" y="372">4</text>
<text x="70" y="374.6">6</text>
<text x="70" y="377.1">8</text>
<text x="91.6" y="372">2</text>
<text x="91.6" y="374.6">3</text>
<text x="91.6" y="377.1">4</text>
<text x="104.3" y="372">3</text>
<text x="104.3" y="374.6">5</text>
<text x="104.3" y="377.1">7</text>
<text x="113.2" y="372">4</text>
<text x="113.2" y="374.6">6</text>
<text x="113.2" y="377.1">8</text>
<text x="49" y="379.6">5</text>
<text x="49" y="382.2">6</text>
<text x="60.6" y="382.2">11</text>
<text x="61.1" y="379.6">9</text>
<text x="69.5" y="379.6">10</text>
<text x="69.5" y="382.2">12</text>
<text x="91.6" y="379.6">5</text>
<text x="91.6" y="382.2">6</text>
<text x="103.8" y="382.2">11</text>
<text x="104.3" y="379.6">9</text>
<text x="112.7" y="379.6">10</text>
<text x="112.7" y="382.2">12</text>
<text x="10.4" y="385.8">H</text>
<text x="49" y="384.7">7</text>
<text x="49" y="387.3">8</text>
<text x="49" y="389.8">9</text>
<text x="60.6" y="384.7">13</text>
<text x="60.6" y="387.3">15</text>
<text x="60.6" y="389.8">17</text>
<text x="69.5" y="384.7">14</text>
<text x="69.5" y="387.3">16</text>
<text x="69.5" y="389.8">18</text>
<text x="91.6" y="384.7">7</text>
<text x="91.6" y="387.3">8</text>
<text x="103.8" y="384.7">13</text>
<text x="103.8" y="387.3">15</text>
<text x="112.7" y="384.7">14</text>
<text x="112.7" y="387.3">16</text>
<text x="162.1" y="388.5">1</text>
<text x="211" y="388.5">1</text>
<text x="582.4" y="385.8">H</text>
<text x="48.6" y="392.3">10</text>
<text x="60.6" y="392.3">19</text>
<text x="69.5" y="392.3">20</text>
<text x="162.1" y="391.1">2</text>
<text x="211" y="391.1">2</text>
<text x="162.1" y="396.2">4</text>
<text x="211" y="396.2">4</text>
<text x="35" y="409.8">1</text>
<text x="85" y="409.8">2</text>
<text x="135" y="409.8">3</text>
<text x="185" y="409.8">4</text>
<text x="235" y="409.8">5</text>
<text x="285" y="409.8">6</text>
<text x="335" y="409.8">7</text>
<text x="385" y="409.8">8</text>
<text x="435" y="409.8">9</text>
<text x="485" y="409.8">10</text>
<text x="535" y="409.8">11</text>
</g>
<g font-size="1.8" fill="#008484">
<text x="35.1" y="17.2">R1</text>
<text x="42.9" y="15.8">D3</text>
<text x="54.8" y="17.2">R6</text>
<text x="62.6" y="15.8">D8</text>
<text x="108.1" y="17.7">0.1u</text>
<text x="108.2" y="15.4">C13</text>
<text x="405.2" y="16.1">+BATT</text>
<text x="414.1" y="16.1">PWR_FLAG</text>
<text x="440" y="17">SBR_DIODE</text>
<text x="443.5" y="14.7">D49</text>
<text x="34.7" y="19.5">510</text>
<text x="42.2" y="18.2">LED</text>
<text x="50.9" y="18.1">+5V</text>
<text x="54.4" y="19.5">510</text>
<text x="61.9" y="18.2">LED</text>
<text x="166.4" y="21.2">+5V</text>
<text x="198.7" y="21.2">+3.3V</text>
<text x="297.9" y="20.6">PWR_FLAG</text>
<text x="315.4" y="22.6">J15</text>
<text x="368" y="22.4">-Vout</text>
<text x="381.2" y="22.4">RC</text>
<text x="450.8" y="22.2">SW9</text>
<text x="503.3" y="23.9">J17</text>
<text x="512.5" y="19.3">+BATT</text>
<text x="526.2" y="23.9">J23</text>
<text x="34.7" y="28.4">510</text>
<text x="35.1" y="26.1">R2</text>
<text x="42.2" y="27">LED</text>
<text x="42.9" y="24.7">D4</text>
<text x="50.1" y="26.9">+3.3V</text>
<text x="54.4" y="28.4">330</text>
<text x="54.8" y="26.1">R7</text>
<text x="61.9" y="27">LED</text>
<text x="62.6" y="24.7">D9</text>
<text x="78.7" y="24.5">C8</text>
<text x="78.9" y="26.8">0.1u</text>
<text x="85.7" y="26.8">R</text>
<text x="85.8" y="24.5">R8</text>
<text x="106.7" y="27.6">AP3211</text>
<text x="108.7" y="25.2">U2</text>
<text x="141.4" y="28.8">22uH</text>
<text x="142.5" y="26.5">L1</text>
<text x="173.7" y="25.6">V_IN V_OUT</text>
<text x="216.2" y="28.3">Control-Power_SW</text>
<text x="222.2" y="26">SW5</text>
<text x="276.4" y="29.2">FET_P</text>
<text x="276.6" y="26.9">Q4</text>
<text x="304.9" y="26.8">GND</text>
<text x="315.3" y="25">5Vin</text>
<text x="341.8" y="25.7">+12V PWR_FLAG</text>
<text x="368" y="26.2">TRM</text>
<text x="380.4" y="26.2">-Vin</text>
<text x="412.1" y="26.7" transform="rotate(-90 412.1 26.7)">2</text>
<text x="414.7" y="26.7" transform="rotate(-90 414.7 26.7)">4</text>
<text x="417.6" y="29.4">J25</text>
<text x="448.6" y="24.5">MAIN_SW</text>
<text x="470.7" y="27.9">FET_P</text>
<text x="471" y="25.6">Q18</text>
<text x="503.1" y="26.2">MOTOR0</text>
<text x="514.9" y="27.6">GNDPWR</text>
<text x="525.8" y="26.2">BATT_IN</text>
<text x="35.1" y="35">R3</text>
<text x="42.2" y="35.9">LED</text>
<text x="42.9" y="33.6">D5</text>
<text x="65.5" y="35.7">GND</text>
<text x="85.7" y="34.4">R</text>
<text x="85.8" y="32.1">R9</text>
<text x="105.8" y="31.9">BS</text>
<text x="111.1" y="31.9">SW</text>
<text x="131" y="32.7">+12V</text>
<text x="170.8" y="30.2">C28</text>
<text x="170.9" y="32.5">10u</text>
<text x="179.7" y="30.3" transform="rotate(-90 179.7 30.3)">GND</text>
<text x="193.7" y="30.2">C31</text>
<text x="193.8" y="32.5">22u</text>
<text x="214.7" y="35.1">GND</text>
<text x="239.6" y="34.3">FET_P</text>
<text x="239.7" y="31.9">Q3</text>
<text x="246.4" y="33.9">+5V</text>
<text x="265.6" y="35.8">R53</text>
<text x="365.2" y="32.7">C42</text>
<text x="365.3" y="35">470u</text>
<text x="368" y="30">+Vout</text>
<text x="380" y="30">+Vin</text>
<text x="394.4" y="32.7">C52</text>
<text x="394.5" y="35">470u</text>
<text x="412.1" y="34.3" transform="rotate(-90 412.1 34.3)">1</text>
<text x="414.7" y="34.3" transform="rotate(-90 414.7 34.3)">3</text>
<text x="417.4" y="31.7">FUSE</text>
<text x="459.9" y="32.7">PWR_FLAG</text>
<text x="461.2" y="34.6">R82</text>
<text x="503.3" y="35.3">J18</text>
<text x="512.5" y="30.8">+BATT</text>
<text x="526.2" y="35.3">J24</text>
<text x="34.7" y="37.3">510</text>
<text x="82" y="41.4">GND</text>
<text x="105.8" y="37">GND</text>
<text x="112.1" y="37">IN</text>
<text x="125.8" y="39.7">C15</text>
<text x="153.1" y="37.2">C20</text>
<text x="153.1" y="39.5">10u</text>
<text x="177.2" y="41.4">GND</text>
<text x="265.6" y="38.1">10k</text>
<text x="397.4" y="41.6">GNDPWR</text>
<text x="461.2" y="36.9">10k</text>
<text x="503.1" y="37.7">MOTOR1</text>
<text x="514.9" y="39.1">GNDPWR</text>
<text x="525.8" y="37.7">BATT_IN</text>
<text x="30.7" y="44.7">+12V</text>
<text x="34.5" y="46.2">1.2k</text>
<text x="35.1" y="43.9">R4</text>
<text x="42.2" y="44.8">LED</text>
<text x="42.9" y="42.5">D6</text>
<text x="58.4" y="46.5">SWD</text>
<text x="59.5" y="44.2">J3</text>
<text x="70.1" y="47.9">SWD_Vdd</text>
<text x="72.7" y="45.6">JP1</text>
<text x="90.1" y="47.9">+3.3V</text>
<text x="105.8" y="42.1">FB</text>
<text x="111.5" y="42.1">EN</text>
<text x="125.9" y="42">4.7u</text>
<text x="261.7" y="45.3">GND</text>
<text x="360.1" y="42.1">GND</text>
<text x="377.9" y="46.6">+BATT</text>
<text x="382.5" y="45.8">R65</text>
<text x="390.2" y="46.7">LED</text>
<text x="390.3" y="44.4">D36</text>
<text x="400.1" y="46.6">+5P</text>
<text x="403.5" y="45.8">R68</text>
<text x="411.2" y="46.7">LED</text>
<text x="411.3" y="44.4">D46</text>
<text x="455.2" y="43.5">GNDPWR</text>
<text x="503.3" y="46.8">J19</text>
<text x="45.8" y="53.5">GND</text>
<text x="104.1" y="48.5">+3.3V</text>
<text x="148" y="49.1">GND</text>
<text x="382.4" y="48.1">2.2k</text>
<text x="390.3" y="53.3">D37</text>
<text x="403.7" y="48.1">510</text>
<text x="411.3" y="53.3">D57</text>
<text x="441.5" y="53.6">+12P</text>
<text x="457.6" y="52.9">N.C</text>
<text x="503.1" y="49.1">MOTOR2</text>
<text x="63.6" y="54.1">GND</text>
<text x="109.2" y="55.6">C11</text>
<text x="109.4" y="57.9">0.1u</text>
<text x="118.1" y="57.9">1u</text>
<text x="118.1" y="55.6">C14</text>
<text x="127" y="55.6">C16</text>
<text x="127.2" y="57.9">0.1u</text>
<text x="135.9" y="55.6">C17</text>
<text x="136" y="57.9">0.1u</text>
<text x="144.8" y="55.6">C18</text>
<text x="144.9" y="57.9">0.1u</text>
<text x="153.7" y="55.6">C21</text>
<text x="153.8" y="57.9">0.1u</text>
<text x="162.6" y="55.6">C24</text>
<text x="162.7" y="57.9">0.1u</text>
<text x="171.5" y="55.6">C29</text>
<text x="171.6" y="57.9">0.1u</text>
<text x="180.4" y="55.6">C30</text>
<text x="180.5" y="57.9">4.7u</text>
<text x="382.4" y="57">2.2k</text>
<text x="382.5" y="54.7">R66</text>
<text x="390.2" y="55.6">LED</text>
<text x="399.6" y="55.5">+12P</text>
<text x="403.4" y="57">1.2k</text>
<text x="403.5" y="54.7">R83</text>
<text x="411.2" y="55.6">LED</text>
<text x="432.9" y="58.2">J16</text>
<text x="457.5" y="55.4">N.O</text>
<text x="503.3" y="58.2">J20</text>
<text x="121.2" y="63.1">+3.3V</text>
<text x="175.3" y="64.9">GND</text>
<text x="382.4" y="65.9">2.2k</text>
<text x="382.5" y="63.5">R67</text>
<text x="390.2" y="64.5">LED</text>
<text x="390.3" y="62.2">D38</text>
<text x="412.6" y="63.8">GNDPWR</text>
<text x="424.8" y="60.5">EMERGENCY</text>
<text x="503.1" y="60.5">MOTOR3</text>
<text x="25.6" y="71.5">Y1</text>
<text x="390.3" y="71.1">D48</text>
<text x="450.8" y="71.7">SW8</text>
<text x="503.1" y="71.9">MOTOR4</text>
<text x="503.3" y="69.6">J21</text>
<text x="24.4" y="73.8">8MHz</text>
<text x="48.1" y="76">10k</text>
<text x="48.4" y="73.7">R5</text>
<text x="382.4" y="74.7">2.2k</text>
<text x="382.5" y="72.4">R81</text>
<text x="390.2" y="73.4">LED</text>
<text x="445.1" y="74">EMERGENCY_SW</text>
<text x="469.7" y="77.8">Q11</text>
<text x="480.6" y="74.5">JP2</text>
<text x="480.7" y="76.8">Relay_JP</text>
<text x="25.3" y="81">C1</text>
<text x="25.5" y="83.3">22p</text>
<text x="34.2" y="81">C3</text>
<text x="34.4" y="83.3">22p</text>
<text x="43.9" y="83.4">GND</text>
<text x="62" y="84">NRST</text>
<text x="62" y="78.9">BOOT0</text>
<text x="123.8" y="81.2" transform="rotate(-90 123.8 81.2)">VREF+</text>
<text x="136.5" y="80.5" transform="rotate(-90 136.5 80.5)">VDDA</text>
<text x="161.9" y="79.2" transform="rotate(-90 161.9 79.2)">VDD</text>
<text x="169.5" y="79.2" transform="rotate(-90 169.5 79.2)">VDD</text>
<text x="177.2" y="79.2" transform="rotate(-90 177.2 79.2)">VDD</text>
<text x="184.8" y="79.2" transform="rotate(-90 184.8 79.2)">VDD</text>
<text x="192.4" y="79.2" transform="rotate(-90 192.4 79.2)">VDD</text>
<text x="200" y="79.2" transform="rotate(-90 200 79.2)">VDD</text>
<text x="212.7" y="80.3" transform="rotate(-90 212.7 80.3)">VBAT</text>
<text x="252.3" y="84">PE2/TRACECLK/FSMC_A23/ETH_MII_TXD3/EVENTOUT</text>
<text x="256.8" y="78.9">PE0/TIM4_ETR/FSMC_NBL0/DCMI_D2/EVENTOUT</text>
<text x="265.9" y="81.4">PE1/FSMC_NBL1/DCMI_D3/EVENTOUT</text>
<text x="360.3" y="82.1">C43</text>
<text x="391.7" y="81.6">GNDPWR</text>
<text x="460.5" y="81.6">R87</text>
<text x="460.6" y="83.9">10k</text>
<text x="469.4" y="80.1">FET_N</text>
<text x="503.1" y="83.4">MOTOR5</text>
<text x="503.3" y="81.1">J22</text>
<text x="62" y="89.1">PH0/OSC_IN/EVENTOUT</text>
<text x="258.4" y="89.1">PE4/TRACED1/FSMC_A20/DCMI_D4/EVENTOUT</text>
<text x="266.7" y="86.5">PE3/TRACED0/FSMC_A19/EVENTOUT</text>
<text x="359.5" y="84.4">1500p</text>
<text x="23.7" y="95.6">RESET</text>
<text x="24.8" y="93.3">SW1</text>
<text x="24.8" y="90.3">GND</text>
<text x="247.4" y="94.1">PE6/TRACED3_/_FSMC_A22/TIM9_CH2/DCMI_D7/EVENTOUT</text>
<text x="249.4" y="91.6">PE5/TRACED2/FSMC_A21/TIM9_CH1/DCMI_D6/EVENTOUT</text>
<text x="399" y="93.8">L2</text>
<text x="416.1" y="94.9">+12P</text>
<text x="436.9" y="94.9">+5P</text>
<text x="474.2" y="90.5">GNDPWR</text>
<text x="25.6" y="101.8">C2</text>
<text x="266.2" y="99.2">PE8/FSMC_D5/TIM1_CH1N/EVENTOUT</text>
<text x="267.4" y="96.7">PE7/FSMC_D4/TIM1_ETR/EVENTOUT</text>
<text x="267.4" y="101.8">PE9/FSMC_D6/TIM1_CH1/EVENTOUT</text>
<text x="357.9" y="99.2">BST</text>
<text x="357.9" y="101.8">GND VCC</text>
<text x="364" y="99.2">Lx</text>
<text x="397.9" y="96.1">22uH</text>
<text x="421" y="101.9">C74</text>
<text x="441.4" y="101.9">C75</text>
<text x="24.9" y="104.1">0.1u</text>
<text x="62" y="104.3">PH1/OSC_OUT/EVENTOUT</text>
<text x="265.2" y="104.3">PE10/FSMC_D7/TIM1_CH2N/EVENTOUT</text>
<text x="266.5" y="106.8">PE11/FSMC_D8/TIM1_CH2/EVENTOUT</text>
<text x="338.6" y="107">R57</text>
<text x="345.6" y="107">R58</text>
<text x="347.9" y="105.7">GNDPWR</text>
<text x="355" y="107">C41</text>
<text x="357.9" y="104.3">FB</text>
<text x="363.6" y="104.3">EN</text>
<text x="377.9" y="104.5">C50</text>
<text x="378" y="106.8">4.7u</text>
<text x="387.4" y="104.5">C51</text>
<text x="387.6" y="106.8">100u</text>
<text x="410.2" y="103.2">C59</text>
<text x="410.3" y="105.5">10u</text>
<text x="421.2" y="104.2">4.7u</text>
<text x="441.5" y="104.2">4.7u</text>
<text x="507.4" y="105.1">C60</text>
<text x="507.6" y="107.4">470u</text>
<text x="517.6" y="105.1">C61</text>
<text x="517.7" y="107.4">470u</text>
<text x="29.9" y="112.6">GND</text>
<text x="265.2" y="109.4">PE12/FSMC_D9/TIM1_CH3N/EVENTOUT</text>
<text x="265.5" y="111.9">PE13/FSMC_D10/TIM1_CH3/EVENTOUT</text>
<text x="338.7" y="109.3">510</text>
<text x="345.7" y="109.3">7.5k</text>
<text x="355.1" y="109.3">0.1u</text>
<text x="424.1" y="113.4">GNDPWR</text>
<text x="510.4" y="114">GNDPWR</text>
<text x="264.7" y="117">PE15/FSMC_D12/TIM1_BKIN/EVENTOUT</text>
<text x="265.5" y="114.5">PE14/FSMC_D11/TIM1_CH4/EVENTOUT</text>
<text x="332.6" y="115.9">GNDPWR</text>
<text x="371" y="116.5">+12P</text>
<text x="62" y="124.6">PA0/WKUP/USART2_CTS/UART4_TX/ETH_MII_CRS_/TIM2_CH1_ETR/TIM5_CH1/TIM8_ETR/EVENTOUT</text>
<text x="267.6" y="124.6">PD0/FSMC_D2/CAN1_RX/EVENTOUT</text>
<text x="375.9" y="123.5">C44</text>
<text x="376.1" y="125.8">0.1u</text>
<text x="411" y="124.1">+12P</text>
<text x="492.2" y="123.5">C62</text>
<text x="492.3" y="125.8">0.1u</text>
<text x="62" y="127.2">PA1/USART2_RTS/UART4_RX/ETH_RMII_REF_CLK/ETH_MII_RX_CLK/TIM5_CH2/TIMM2_CH2/EVENTOUT</text>
<text x="62" y="129.7">PA2/USART2_TX/TIM5_CH3/TIM9_CH1/TIM2_CH3/ETH_MDIO/EVENTOUT</text>
<text x="247.2" y="129.7">PD2/TIM3_ETR/UART5_RX/SDIO_CMD/DCMI_D11/EVENTOUT</text>
<text x="267.8" y="127.2">PD1/FSMC_D3/CAN1_TX/EVENTOUT</text>
<text x="359" y="131.1">+12P</text>
<text x="384.1" y="131.1">NCP5104</text>
<text x="386.4" y="128.7">U12</text>
<text x="425.1" y="129.8">NVMFD5C446NLT1G</text>
<text x="432.5" y="127.5">Q5</text>
<text x="500.4" y="131.1">NCP5104</text>
<text x="502.6" y="128.7">U19</text>
<text x="541.3" y="129.8">NVMFD5C446NLT1G</text>
<text x="548.2" y="127.5">Q16</text>
<text x="62" y="132.2">PA3/USART2_RX/TIM5_CH4/TIM9_CH2/TIM2_CH4/OTG_HS_ULPI_D0/ETH_MII_COL/EVENTOUT</text>
<text x="62" y="134.8">PA4/SPI1_NSS/SPI3_NSS/USART2_CK/DCMI_HSYNC/OTG_HS_SOF/I2S3_WS/EVENTOUT</text>
<text x="62" y="137.3">PA5/SPI1_SCK/OTG_HS_ULPI_CK/TIM2_CH1_ETR/TIM8_CHIN/EVENTOUT</text>
<text x="262.7" y="134.8">PD4/FSMC_NOE/USART2_RTS/EVENTOUT</text>
<text x="262.9" y="132.2">PD3/FSMC_CLK/USART2_CTS/EVENTOUT</text>
<text x="263.7" y="137.3">PD5/FSMC_NWE/USART2_TX/EVENTOUT</text>
<text x="368.8" y="132.4">GNDPWR</text>
<text x="380.1" y="135.4">Vcc</text>
<text x="389.6" y="135.4">VBOOT</text>
<text x="407.3" y="135.3">R69</text>
<text x="408.5" y="137.6">3</text>
<text x="425.6" y="136.7">S1</text>
<text x="437.6" y="134.2">D1_1</text>
<text x="437.6" y="136.7">D1_2</text>
<text x="485" y="132.4">GNDPWR</text>
<text x="496.3" y="135.4">Vcc</text>
<text x="505.8" y="135.4">VBOOT</text>
<text x="523.5" y="135.3">R94</text>
<text x="524.7" y="137.6">3</text>
<text x="541.8" y="136.7">S1</text>
<text x="553.8" y="134.2">D1_1</text>
<text x="553.8" y="136.7">D1_2</text>
<text x="62" y="139.9">PA6/SPI1_MISO/TIM8_BKIN/TIM13_CH1/DCMI_PIXCLK/TIM3_CH1/TIM1_BKIN/EVENTOUT</text>
<text x="62" y="142.4">PA7/SPI1_MOSI/TIM8_CH1N/TIM14_CH1/TIM3_CH2/ETH_MII_RX_DV/TIM1_CH1N/RMII_CRS_DV/EVENTOUT</text>
<text x="252.9" y="142.4">PD7/USART2_CK/FSMC_NE1/FSMC_NCE2/EVENTOUT</text>
<text x="261.8" y="139.9">PD6/FSMC_NWAIT/USART2_RX/EVENTOUT</text>
<text x="362.7" y="140.7">R62</text>
<text x="362.8" y="143">10k</text>
<text x="380.1" y="140.5">IN</text>
<text x="388.5" y="140.5">DRV_HO</text>
<text x="405.8" y="139.4">C53</text>
<text x="405.9" y="141.7">4.7u</text>
<text x="425.6" y="139.2">G1</text>
<text x="425.6" y="141.8">S2</text>
<text x="437.6" y="141.8">D1_4</text>
<text x="437.6" y="139.2">D1_3</text>
<text x="478.9" y="140.7">R91</text>
<text x="479" y="143">10k</text>
<text x="496.3" y="140.5">IN</text>
<text x="504.7" y="140.5">DRV_HO</text>
<text x="522" y="139.4">C68</text>
<text x="522.1" y="141.7">4.7u</text>
<text x="541.8" y="139.2">G1</text>
<text x="541.8" y="141.8">S2</text>
<text x="553.8" y="141.8">D1_4</text>
<text x="553.8" y="139.2">D1_3</text>
<text x="62" y="144.9">PA8/MCO1/USART1_CK/TIM1_CH1/I2C3_SCL/OTG_FS_SOF/EVENTOUT</text>
<text x="62" y="147.5">PA9/USART1_TX/TIM1_CH2/I2C3_SMBA/DCMI_D0/EVENTOUT</text>
<text x="264.4" y="147.5">PD9/FSMC_D14/USART3_RX/EVENTOUT</text>
<text x="264.6" y="144.9">PD8/FSMC_D13/USART3_TX/EVENTOUT</text>
<text x="380.1" y="145.6">SD</text>
<text x="389" y="145.6">BRIDGE</text>
<text x="408.5" y="147.8">3</text>
<text x="415.8" y="145.7">GNDPWR</text>
<text x="425.6" y="144.3">G2</text>
<text x="425.6" y="146.9">D2_1</text>
<text x="425.6" y="149.4">D2_2</text>
<text x="437.6" y="146.9">D2_3</text>
<text x="437.6" y="149.4">D2_4</text>
<text x="437.6" y="144.3">D1_5</text>
<text x="496.3" y="145.6">SD</text>
<text x="505.2" y="145.6">BRIDGE</text>
<text x="524.7" y="147.8">3</text>
<text x="532" y="145.7">GNDPWR</text>
<text x="541.8" y="144.3">G2</text>
<text x="541.8" y="146.9">D2_1</text>
<text x="541.8" y="149.4">D2_2</text>
<text x="553.8" y="146.9">D2_3</text>
<text x="553.8" y="149.4">D2_4</text>
<text x="553.8" y="144.3">D1_5</text>
<text x="62" y="150">PA10/USART1_RX/TIM1_CH3/OTG_FS_ID/DCMI_D1/EVENTOUT</text>
<text x="62" y="152.6">PA11/USART1_CTS/CAN1_RX/TIM1_CH4_/OTG_FS_DM/EVENTOUT</text>
<text x="62" y="155.1">PA12/USART1_RTS/CAN1_TX/TIM1_ETR/OTG_FS_DP/EVENTOUT</text>
<text x="243.3" y="155.1">PD12/FSMC_ALE/FSMC_A17/TIM4_CH1/USART3_RTS/EVENTOUT</text>
<text x="252.3" y="152.6">PD11/FSMC_CLE/FSMC_A16/USART3_CTS/EVENTOUT</text>
<text x="263.3" y="150">PD10/FSMC_D15/USART3_CK/EVENTOUT</text>
<text x="371" y="155.8">+12P</text>
<text x="380.1" y="150.7">GND</text>
<text x="388.7" y="150.7">DRV_LO</text>
<text x="437.6" y="151.9">D2_5</text>
<text x="496.3" y="150.7">GND</text>
<text x="504.9" y="150.7">DRV_LO</text>
<text x="553.8" y="151.9">D2_5</text>
<text x="62" y="157.6">PA13/JTMS/SWDIO/EVENTOUT</text>
<text x="62" y="160.2">PA14/JTCK/SWCLK/EVENTOUT</text>
<text x="255.3" y="160.2">PD14/FSMC_D0/TIM4_CH3/EVENTOUT/_EVENTOUT</text>
<text x="265.4" y="157.6">PD13/FSMC_A18/TIM4_CH2/EVENTOUT</text>
<text x="372.6" y="157.2">GNDPWR</text>
<text x="488.8" y="157.2">GNDPWR</text>
<text x="62" y="162.7">PA15/JTDI/SPI3_NSS/I2S3_WS/TIM2_CH1_ETR/SPI1_NSS/EVENTOUT</text>
<text x="266.4" y="162.7">PD15/FSMC_D1/TIM4_CH4/EVENTOUT</text>
<text x="375.9" y="162.9">C45</text>
<text x="376.1" y="165.2">0.1u</text>
<text x="411" y="163.5">+12P</text>
<text x="432.5" y="166.8">Q6</text>
<text x="492.2" y="162.9">C63</text>
<text x="492.3" y="165.2">0.1u</text>
<text x="548.2" y="166.8">Q17</text>
<text x="62" y="170.3">PB0/TIM3_CH3/TIM8_CH2N/OTG_HS_ULPI_D1/ETH_MII_RXD2/TIM1_CH2N/EVENTOUT</text>
<text x="62" y="172.9">PB1/TIM3_CH4/TIM8_CH3N/OTG_HS_ULPI_D2/ETH_MII_RXD3/OTG_HS_INTN/TIM1_CH3N/EVENTOUT</text>
<text x="267.9" y="170.3">PC0/OTG_HS_ULPI_STP/EVENTOUT</text>
<text x="275.1" y="172.9">PC1/ETH_MDC/_EVENTOUT</text>
<text x="358.3" y="170.5">+12P</text>
<text x="368.8" y="171.8">GNDPWR</text>
<text x="384.1" y="170.4">NCP5104</text>
<text x="386.4" y="168.1">U13</text>
<text x="425.1" y="169.2">NVMFD5C446NLT1G</text>
<text x="437.6" y="173.5">D1_1</text>
<text x="485" y="171.8">GNDPWR</text>
<text x="500.4" y="170.4">NCP5104</text>
<text x="502.6" y="168.1">U20</text>
<text x="541.3" y="169.2">NVMFD5C446NLT1G</text>
<text x="553.8" y="173.5">D1_1</text>
<text x="62" y="175.4">PB2/BOOT1/EVENTOUT</text>
<text x="62" y="178">PB3/JTDO/TRACESWO/SPI3_SCK/I2S3_CK/TIM2_CH2/SPI1_SCK/EVENTOUT</text>
<text x="235.1" y="178">PC3/SPI2_MOSI/I2S2_SD/OTG_HS_ULPI_NXT/ETH_MII_TX_CLK/EVENTOUT</text>
<text x="235.4" y="175.4">PC2/SPI2_MISO/OTG_HS_ULPI_DIR/ETH_MII_TXD2/I2S2ext_SD/EVENTOUT</text>
<text x="380.1" y="174.8">Vcc</text>
<text x="380.1" y="179.9">IN</text>
<text x="388.5" y="179.9">DRV_HO</text>
<text x="389.6" y="174.8">VBOOT</text>
<text x="405.8" y="178.8">C54</text>
<text x="407.3" y="174.7">R71</text>
<text x="408.5" y="177">3</text>
<text x="425.6" y="176.1">S1</text>
<text x="425.6" y="178.6">G1</text>
<text x="437.6" y="176.1">D1_2</text>
<text x="437.6" y="178.6">D1_3</text>
<text x="496.3" y="174.8">Vcc</text>
<text x="496.3" y="179.9">IN</text>
<text x="504.7" y="179.9">DRV_HO</text>
<text x="505.8" y="174.8">VBOOT</text>
<text x="522" y="178.8">C69</text>
<text x="523.5" y="174.7">R96</text>
<text x="524.7" y="177">3</text>
<text x="541.8" y="176.1">S1</text>
<text x="541.8" y="178.6">G1</text>
<text x="553.8" y="176.1">D1_2</text>
<text x="553.8" y="178.6">D1_3</text>
<text x="62" y="180.5">PB4/NJTRST/SPI3_MISO/TIM3_CH1/SPI1_MISO/I2S3ext_SD/EVENTOUT</text>
<text x="62" y="183">PB5/I2C1_SMBA/CAN2_RX/OTG_HS_ULPI_D7/ETH_PPS_OUT/TIM3_CH2/SPI1_MOSI/SPI3_MOSI/DCMI_D10/I2S3_SD/EVENTOUT</text>
<text x="62" y="185.6">PB6/I2C1_SCL/TIM4_CH1/CAN2_TX/DCMI_D5/USART1_TX/EVENTOUT</text>
<text x="230.8" y="185.6">PC6/I2S2_MCK/TIM8_CH1/SDIO_D6/USART6_TX/DCMI_D0/TIM3_CH1/EVENTOUT</text>
<text x="255.5" y="180.5">PC4/ETH_RMII_RX_D0/ETH_MII_RX_D0/EVENTOUT</text>
<text x="255.5" y="183">PC5/ETH_RMII_RX_D1/ETH_MII_RX_D1/EVENTOUT</text>
<text x="362.1" y="180">R59</text>
<text x="362.2" y="182.3">10k</text>
<text x="380.1" y="185">SD</text>
<text x="389" y="185">BRIDGE</text>
<text x="405.9" y="181.1">4.7u</text>
<text x="415.8" y="185.1">GNDPWR</text>
<text x="425.6" y="181.1">S2</text>
<text x="425.6" y="183.7">G2</text>
<text x="437.6" y="181.1">D1_4</text>
<text x="437.6" y="183.7">D1_5</text>
<text x="478.3" y="180">R88</text>
<text x="478.4" y="182.3">10k</text>
<text x="496.3" y="185">SD</text>
<text x="505.2" y="185">BRIDGE</text>
<text x="522.1" y="181.1">4.7u</text>
<text x="532" y="185.1">GNDPWR</text>
<text x="541.8" y="181.1">S2</text>
<text x="541.8" y="183.7">G2</text>
<text x="553.8" y="181.1">D1_4</text>
<text x="553.8" y="183.7">D1_5</text>
<text x="62" y="188.1">PB7/I2C1_SDA/FSMC_NL/DCMI_VSYNC/USART1_RX/TIM4_CH2/EVENTOUT</text>
<text x="62" y="190.7">PB8/TIM4_CH3/SDIO_D4/TIM10_CH1/DCMI_D6/ETH_MII_TXD3/I2C1_SCL/CAN1_RX/EVENTOUT</text>
<text x="230.6" y="188.1">PC7/I2S3_MCK/TIM8_CH2/SDIO_D7/USART6_RX/DCMI_D1/TIM3_CH2/EVENTOUT</text>
<text x="239.6" y="190.7">PC8/TIM8_CH3/SDIO_D0/TIM3_CH3/USART6_CK/DCMI_D2/EVENTOUT</text>
<text x="380.1" y="190">GND</text>
<text x="388.7" y="190">DRV_LO</text>
<text x="408.5" y="187.1">3</text>
<text x="425.6" y="186.2">D2_1</text>
<text x="425.6" y="188.8">D2_2</text>
<text x="437.6" y="186.2">D2_3</text>
<text x="437.6" y="188.8">D2_4</text>
<text x="437.6" y="191.3">D2_5</text>
<text x="496.3" y="190">GND</text>
<text x="504.9" y="190">DRV_LO</text>
<text x="524.7" y="187.1">3</text>
<text x="541.8" y="186.2">D2_1</text>
<text x="541.8" y="188.8">D2_2</text>
<text x="553.8" y="186.2">D2_3</text>
<text x="553.8" y="188.8">D2_4</text>
<text x="553.8" y="191.3">D2_5</text>
<text x="62" y="195.7">PB10/SPI2_SCK/I2S2_CK/I2C2_SCL/USART3_TX/OTG_HS_ULPI_D3/ETH_MII_RX_ER/TIM2_CH3/EVENTOUT</text>
<text x="62" y="193.2">PB9/SPI2_NSS/I2S2_WS/TIM4_CH4/TIM11_CH1/SDIO_D5/DCMI_D7/I2C1_SDA/CAN1_TX/EVENTOUT</text>
<text x="227.7" y="193.2">PC9/I2S_CKIN/MCO2/TIM8_CH4/SDIO_D1/I2C3_SDA/DCMI_D3/TIM3_CH4/EVENTOUT</text>
<text x="230.7" y="195.7">PC10/SPI3_SCK/I2S3_CK/UART4_TX/SDIO_D2/DCMI_D8/USART3_TX/EVENTOUT</text>
<text x="372.6" y="196.5">GNDPWR</text>
<text x="488.8" y="196.5">GNDPWR</text>
<text x="62" y="198.3">PB11/I2C2_SDA/USART3_RX/OTG_HS_ULPI_D4/ETH_RMII_TX_EN/ETH_MII_TX_EN/TIM2_CH4/EVENTOUT</text>
<text x="62" y="200.8">PB12/SPI2_NSS/I2S2_WS/I2C2_SMBA/USART3_CK/TIM1_BKIN/CAN2_RX/OTG_HS_ULPI_D5/ETH_RMII_TXD0/ETH_MII_TXD0/OTG_HS_ID/EVENTOUT</text>
<text x="62" y="203.4">PB13/SPI2_SCK/I2S2_CK/USART3_CTS/TIM1_CH1N/CAN2_TX/OTG_HS_ULPI_D6/ETH_RMII_TXD1/ETH_MII_TXD1/EVENTOUT</text>
<text x="227.1" y="198.3">PC11/UART4_RX/SPI3_MISO/SDIO_D3/DCMI_D4/USART3_RX/I2S3ext_SD/EVENTOUT</text>
<text x="229.4" y="200.8">PC12/UART5_TX/SDIO_CK/DCMI_D9/SPI3_MOSI/I2S3_SD/USART3_CK/EVENTOUT</text>
<text x="284.1" y="203.4">PC13/EVENTOUT</text>
<text x="371" y="199.7">+12P</text>
<text x="62" y="205.9">PB14/SPI2_MISO/TIM1_CH2N/TIM12_CH1/OTG_HS_DM/USART3_RTS/TIM8_CH2N/I2S2ext_SD/EVENTOUT</text>
<text x="62" y="208.4">PB15/SPI2_MOSI/I2S2_SD/TIM1_CH3N/TIM8_CH3N/TIM12_CH2/OTG_HS_DP/EVENTOUT</text>
<text x="273.2" y="208.4">PC15/OSC32_OUT/EVENTOUT</text>
<text x="275.1" y="205.9">PC14/OSC32_IN/EVENTOUT</text>
<text x="375.9" y="206.7">C46</text>
<text x="376.1" y="209">0.1u</text>
<text x="411" y="207.3">+12P</text>
<text x="492.2" y="206.7">C64</text>
<text x="492.3" y="209">0.1u</text>
<text x="170.8" y="210.6" transform="rotate(-90 170.8 210.6)">VSSA</text>
<text x="175.9" y="210.6" transform="rotate(-90 175.9 210.6)">VSS</text>
<text x="181" y="210.6" transform="rotate(-90 181 210.6)">VSS</text>
<text x="186.1" y="210.6" transform="rotate(-90 186.1 210.6)">VSS</text>
<text x="191.1" y="210.6" transform="rotate(-90 191.1 210.6)">VSS</text>
<text x="203.8" y="210.6" transform="rotate(-90 203.8 210.6)">VCAP_1</text>
<text x="216.5" y="210.6" transform="rotate(-90 216.5 210.6)">VCAP_2</text>
<text x="359" y="214.3">+12P</text>
<text x="368.8" y="215.6">GNDPWR</text>
<text x="384.1" y="214.2">NCP5104</text>
<text x="386.4" y="211.9">U14</text>
<text x="425.1" y="213">NVMFD5C446NLT1G</text>
<text x="432.5" y="210.7">Q7</text>
<text x="485" y="215.6">GNDPWR</text>
<text x="500.4" y="214.2">NCP5104</text>
<text x="502.6" y="211.9">U21</text>
<text x="541.3" y="213">NVMFD5C446NLT1G</text>
<text x="548.2" y="210.7">Q12</text>
<text x="380.1" y="218.6">Vcc</text>
<text x="389.6" y="218.6">VBOOT</text>
<text x="407.3" y="218.5">R73</text>
<text x="408.5" y="220.8">3</text>
<text x="425.6" y="219.9">S1</text>
<text x="437.6" y="217.3">D1_1</text>
<text x="437.6" y="219.9">D1_2</text>
<text x="496.3" y="218.6">Vcc</text>
<text x="505.8" y="218.6">VBOOT</text>
<text x="523.5" y="218.5">R98</text>
<text x="524.7" y="220.8">3</text>
<text x="541.8" y="219.9">S1</text>
<text x="553.8" y="217.3">D1_1</text>
<text x="553.8" y="219.9">D1_2</text>
<text x="206.4" y="222.6">C32</text>
<text x="206.5" y="224.9">2.2u</text>
<text x="219.1" y="222.6">C35</text>
<text x="219.2" y="224.9">2.2u</text>
<text x="302.2" y="223.2">+3.3V</text>
<text x="336" y="223.2">+5P</text>
<text x="362.7" y="223.8">R63</text>
<text x="362.8" y="226.2">10k</text>
<text x="380.1" y="223.7">IN</text>
<text x="388.5" y="223.7">DRV_HO</text>
<text x="405.8" y="222.6">C55</text>
<text x="405.9" y="224.9">4.7u</text>
<text x="425.6" y="222.4">G1</text>
<text x="425.6" y="225">S2</text>
<text x="425.6" y="227.5">G2</text>
<text x="437.6" y="225">D1_4</text>
<text x="437.6" y="222.4">D1_3</text>
<text x="437.6" y="227.5">D1_5</text>
<text x="478.9" y="223.8">R92</text>
<text x="479" y="226.2">10k</text>
<text x="496.3" y="223.7">IN</text>
<text x="504.7" y="223.7">DRV_HO</text>
<text x="522" y="222.6">C70</text>
<text x="522.1" y="224.9">4.7u</text>
<text x="541.8" y="222.4">G1</text>
<text x="541.8" y="225">S2</text>
<text x="541.8" y="227.5">G2</text>
<text x="553.8" y="225">D1_4</text>
<text x="553.8" y="222.4">D1_3</text>
<text x="553.8" y="227.5">D1_5</text>
<text x="214.1" y="231.9">GND</text>
<text x="307.4" y="230.2">C36</text>
<text x="307.5" y="232.5">0.1u</text>
<text x="340.4" y="230.2">C38</text>
<text x="340.5" y="232.5">0.1u</text>
<text x="380.1" y="228.8">SD</text>
<text x="380.1" y="233.8">GND</text>
<text x="388.7" y="233.8">DRV_LO</text>
<text x="389" y="228.8">BRIDGE</text>
<text x="408.5" y="231">3</text>
<text x="415.8" y="228.9">GNDPWR</text>
<text x="425.6" y="230">D2_1</text>
<text x="425.6" y="232.6">D2_2</text>
<text x="437.6" y="230">D2_3</text>
<text x="437.6" y="232.6">D2_4</text>
<text x="496.3" y="228.8">SD</text>
<text x="496.3" y="233.8">GND</text>
<text x="504.9" y="233.8">DRV_LO</text>
<text x="505.2" y="228.8">BRIDGE</text>
<text x="524.7" y="231">3</text>
<text x="532" y="228.9">GNDPWR</text>
<text x="541.8" y="230">D2_1</text>
<text x="541.8" y="232.6">D2_2</text>
<text x="553.8" y="230">D2_3</text>
<text x="553.8" y="232.6">D2_4</text>
<text x="302.3" y="239.6">GND</text>
<text x="305.4" y="234.6">+3.3V</text>
<text x="313.4" y="238.9">VDD1</text>
<text x="321.9" y="238.9">VDD2</text>
<text x="331.5" y="234.6">+5P</text>
<text x="333.3" y="239.1">GNDPWR</text>
<text x="371" y="239">+12P</text>
<text x="437.6" y="235.1">D2_5</text>
<text x="553.8" y="235.1">D2_5</text>
<text x="144.1" y="244.1">+3.3V</text>
<text x="162.8" y="244.6">C27</text>
<text x="162.8" y="242.1">C26</text>
<text x="163.4" y="244.4">1u</text>
<text x="174.4" y="245.9">V0</text>
<text x="205.4" y="240.6">R36</text>
<text x="205.5" y="242.9">330</text>
<text x="205.5" y="245.4">330</text>
<text x="216.9" y="245.9">blue_A</text>
<text x="226.8" y="245.9">blue_K</text>
<text x="313.4" y="242.7">A1</text>
<text x="324.4" y="242.7">B1</text>
<text x="372.6" y="240.4">GNDPWR</text>
<text x="488.8" y="240.4">GNDPWR</text>
<text x="42.7" y="246.7">+12V</text>
<text x="46.5" y="251.3">0.1u</text>
<text x="47.1" y="249">C6</text>
<text x="73.9" y="246.7">+12V</text>
<text x="77.6" y="251.3">0.1u</text>
<text x="77.7" y="249">C10</text>
<text x="163.4" y="247">1u</text>
<text x="174.4" y="248.5">VOUT</text>
<text x="174.4" y="251">CAP1N</text>
<text x="205.5" y="248">330</text>
<text x="216.9" y="248.5">green_A</text>
<text x="216.9" y="251">red_A</text>
<text x="225.6" y="248.5">green_K</text>
<text x="227.7" y="251">red_K</text>
<text x="313.4" y="246.5">A2</text>
<text x="313.4" y="250.4">A3</text>
<text x="324.4" y="250.4">B3</text>
<text x="324.4" y="246.5">B2</text>
<text x="375.9" y="246.1">C47</text>
<text x="376.1" y="248.4">0.1u</text>
<text x="386.4" y="251.3">U15</text>
<text x="411" y="246.7">+12P</text>
<text x="432.5" y="250">Q8</text>
<text x="492.2" y="246.1">C65</text>
<text x="492.3" y="248.4">0.1u</text>
<text x="502.6" y="251.3">U22</text>
<text x="548.2" y="250">Q13</text>
<text x="148.1" y="256.1">R24</text>
<text x="161.4" y="254.6">0.1u</text>
<text x="161.6" y="252.3">C25</text>
<text x="174.4" y="253.5">CAP1P</text>
<text x="174.4" y="256.1">VDD</text>
<text x="236.9" y="255.4">GND</text>
<text x="313.4" y="254.2">A4</text>
<text x="313.4" y="258">A5</text>
<text x="324.4" y="258">B5</text>
<text x="324.4" y="254.2">B4</text>
<text x="358.3" y="253.6">+12P</text>
<text x="368.8" y="255">GNDPWR</text>
<text x="380.1" y="258">Vcc</text>
<text x="384.1" y="253.6">NCP5104</text>
<text x="389.6" y="258">VBOOT</text>
<text x="407.3" y="257.9">R75</text>
<text x="425.1" y="252.3">NVMFD5C446NLT1G</text>
<text x="437.6" y="256.7">D1_1</text>
<text x="485" y="255">GNDPWR</text>
<text x="496.3" y="258">Vcc</text>
<text x="500.4" y="253.6">NCP5104</text>
<text x="505.8" y="258">VBOOT</text>
<text x="523" y="257.9">R100</text>
<text x="541.3" y="252.3">NVMFD5C446NLT1G</text>
<text x="553.8" y="256.7">D1_1</text>
<text x="60.5" y="260.5">CAN</text>
<text x="60.7" y="258.2">J4</text>
<text x="91.6" y="260.5">CAN</text>
<text x="91.8" y="258.2">J7</text>
<text x="148.2" y="258.4">10k</text>
<text x="154.5" y="258.6">R25</text>
<text x="154.5" y="261">10k</text>
<text x="174.4" y="258.6">VSS</text>
<text x="174.4" y="261.2">SDA</text>
<text x="174.4" y="263.7">SCL</text>
<text x="313.4" y="261.8">A6</text>
<text x="324.4" y="261.8">B6</text>
<text x="362.1" y="263.2">R60</text>
<text x="380.1" y="263.1">IN</text>
<text x="388.5" y="263.1">DRV_HO</text>
<text x="405.8" y="261.9">C56</text>
<text x="408.5" y="260.2">3</text>
<text x="425.6" y="259.2">S1</text>
<text x="425.6" y="261.8">G1</text>
<text x="437.6" y="259.2">D1_2</text>
<text x="437.6" y="261.8">D1_3</text>
<text x="478.3" y="263.2">R89</text>
<text x="496.3" y="263.1">IN</text>
<text x="504.7" y="263.1">DRV_HO</text>
<text x="522" y="261.9">C71</text>
<text x="524.7" y="260.2">3</text>
<text x="541.8" y="259.2">S1</text>
<text x="541.8" y="261.8">G1</text>
<text x="553.8" y="259.2">D1_2</text>
<text x="553.8" y="261.8">D1_3</text>
<text x="31.1" y="265.1">+3.3V</text>
<text x="174.4" y="266.2">XRSETB</text>
<text x="209.7" y="268.2">R40</text>
<text x="218.6" y="268.2">R43</text>
<text x="227.5" y="268.2">R47</text>
<text x="236.4" y="268.2">R49</text>
<text x="245.3" y="268.2">R51</text>
<text x="254.2" y="268.2">R52</text>
<text x="313.4" y="265.6">GND1</text>
<text x="321.7" y="265.6">GND2</text>
<text x="328.8" y="269.6">GNDPWR</text>
<text x="362.2" y="265.5">10k</text>
<text x="380.1" y="268.1">SD</text>
<text x="389" y="268.1">BRIDGE</text>
<text x="405.9" y="264.3">4.7u</text>
<text x="415.8" y="268.3">GNDPWR</text>
<text x="425.6" y="264.3">S2</text>
<text x="425.6" y="266.9">G2</text>
<text x="425.6" y="269.4">D2_1</text>
<text x="437.6" y="264.3">D1_4</text>
<text x="437.6" y="269.4">D2_3</text>
<text x="437.6" y="266.9">D1_5</text>
<text x="478.4" y="265.5">10k</text>
<text x="496.3" y="268.1">SD</text>
<text x="505.2" y="268.1">BRIDGE</text>
<text x="522.1" y="264.3">4.7u</text>
<text x="532" y="268.3">GNDPWR</text>
<text x="541.8" y="264.3">S2</text>
<text x="541.8" y="266.9">G2</text>
<text x="541.8" y="269.4">D2_1</text>
<text x="553.8" y="264.3">D1_4</text>
<text x="553.8" y="269.4">D2_3</text>
<text x="553.8" y="266.9">D1_5</text>
<text x="36.1" y="272.1">C4</text>
<text x="36.3" y="274.4">0.1u</text>
<text x="48.2" y="274.6">+3.3V</text>
<text x="49" y="274.4">U1</text>
<text x="111.1" y="270.8">+3.3V</text>
<text x="123.2" y="275.3">LS1</text>
<text x="174.4" y="271.3">Anode</text>
<text x="174.4" y="273.9">Cathode</text>
<text x="209.8" y="270.5">330</text>
<text x="210.9" y="276">D27</text>
<text x="218.7" y="270.5">330</text>
<text x="219.8" y="276">D28</text>
<text x="227.6" y="270.5">330</text>
<text x="228.7" y="276">D29</text>
<text x="236.5" y="270.5">330</text>
<text x="237.6" y="276">D30</text>
<text x="245.4" y="270.5">330</text>
<text x="246.5" y="276">D31</text>
<text x="254.3" y="270.5">330</text>
<text x="255.4" y="276">D32</text>
<text x="305.5" y="270">GND</text>
<text x="380.1" y="273.2">GND</text>
<text x="388.7" y="273.2">DRV_LO</text>
<text x="408.5" y="270.3">3</text>
<text x="425.6" y="271.9">D2_2</text>
<text x="437.6" y="271.9">D2_4</text>
<text x="437.6" y="274.5">D2_5</text>
<text x="496.3" y="273.2">GND</text>
<text x="504.9" y="273.2">DRV_LO</text>
<text x="524.7" y="270.3">3</text>
<text x="541.8" y="271.9">D2_2</text>
<text x="553.8" y="271.9">D2_4</text>
<text x="553.8" y="274.5">D2_5</text>
<text x="31.2" y="281.5">GND</text>
<text x="46.2" y="276.7">MAX3051</text>
<text x="115.7" y="280.2">R11</text>
<text x="123.4" y="277.6">Speaker</text>
<text x="155.2" y="281.3">R26</text>
<text x="170.3" y="276.4">R27</text>
<text x="170.5" y="278.7">120</text>
<text x="210.8" y="278.3">LED0</text>
<text x="219.7" y="278.3">LED1</text>
<text x="228.5" y="278.3">LED2</text>
<text x="237.4" y="278.3">LED3</text>
<text x="246.3" y="278.3">LED4</text>
<text x="255.2" y="278.3">LED5</text>
<text x="302.2" y="276.5">+3.3V</text>
<text x="336" y="276.5">+5P</text>
<text x="372.6" y="279.7">GNDPWR</text>
<text x="488.8" y="279.7">GNDPWR</text>
<text x="41" y="284">TXD</text>
<text x="41" y="286.6">RXD</text>
<text x="50.8" y="285.6" transform="rotate(-90 50.8 285.6)">VDD</text>
<text x="54.2" y="286.6">CANH</text>
<text x="100.6" y="285.2">R10</text>
<text x="101.3" y="287.5">10</text>
<text x="115.8" y="282.5">120</text>
<text x="155.9" y="283.7">10</text>
<text x="170.8" y="285.4">Q2</text>
<text x="170.8" y="287.7">NPN</text>
<text x="205.8" y="285.3">GND</text>
<text x="214.7" y="285.3">GND</text>
<text x="223.6" y="285.3">GND</text>
<text x="232.5" y="285.3">GND</text>
<text x="241.4" y="285.3">GND</text>
<text x="250.3" y="285.3">GND</text>
<text x="305.4" y="287.9">+3.3V</text>
<text x="307.4" y="283.5">C37</text>
<text x="307.5" y="285.8">0.1u</text>
<text x="331.5" y="287.9">+5P</text>
<text x="340.4" y="283.5">C39</text>
<text x="340.5" y="285.8">0.1u</text>
<text x="371" y="282.8">+12P</text>
<text x="41" y="291.6">SHDN</text>
<text x="54.4" y="291.6">CANL</text>
<text x="116.2" y="289.2">Q1</text>
<text x="116.2" y="291.6">NPN</text>
<text x="205.7" y="289.8">+3.3V</text>
<text x="214.6" y="289.8">+3.3V</text>
<text x="223.5" y="289.8">+3.3V</text>
<text x="232.4" y="289.8">+3.3V</text>
<text x="302.3" y="292.9">GND</text>
<text x="313.4" y="292.3">VDD1</text>
<text x="321.9" y="292.3">VDD2</text>
<text x="333.3" y="292.4">GNDPWR</text>
<text x="375.9" y="289.9">C48</text>
<text x="376.1" y="292.2">0.1u</text>
<text x="411" y="290.5">+12P</text>
<text x="432.5" y="293.8">Q9</text>
<text x="492.2" y="289.9">C66</text>
<text x="492.3" y="292.2">0.1u</text>
<text x="548.2" y="293.8">Q14</text>
<text x="41" y="294.2">RS</text>
<text x="50.8" y="295.1" transform="rotate(-90 50.8 295.1)">GND</text>
<text x="111.8" y="299.9">GND</text>
<text x="166.4" y="296.1">GND</text>
<text x="209.7" y="296.7">R41</text>
<text x="209.8" y="299.1">10k</text>
<text x="218.6" y="296.7">R44</text>
<text x="218.6" y="299.1">10k</text>
<text x="227.5" y="296.7">R48</text>
<text x="227.5" y="299.1">10k</text>
<text x="236.4" y="296.7">R50</text>
<text x="236.4" y="299.1">10k</text>
<text x="313.4" y="296.1">A1</text>
<text x="313.4" y="299.9">A2</text>
<text x="324.4" y="299.9">B2</text>
<text x="324.4" y="296.1">B1</text>
<text x="359" y="297.5">+12P</text>
<text x="368.8" y="298.8">GNDPWR</text>
<text x="384.1" y="297.4">NCP5104</text>
<text x="386.4" y="295.1">U16</text>
<text x="425.1" y="296.2">NVMFD5C446NLT1G</text>
<text x="485" y="298.8">GNDPWR</text>
<text x="500.4" y="297.4">NCP5104</text>
<text x="502.6" y="295.1">U23</text>
<text x="541.3" y="296.2">NVMFD5C446NLT1G</text>
<text x="48.3" y="303.7">GND</text>
<text x="313.4" y="303.7">A3</text>
<text x="324.4" y="303.7">B3</text>
<text x="380.1" y="301.8">Vcc</text>
<text x="389.6" y="301.8">VBOOT</text>
<text x="405.8" y="305.8">C57</text>
<text x="407.3" y="301.7">R77</text>
<text x="408.5" y="304">3</text>
<text x="425.6" y="303.1">S1</text>
<text x="425.6" y="305.6">G1</text>
<text x="437.6" y="300.5">D1_1</text>
<text x="437.6" y="303.1">D1_2</text>
<text x="437.6" y="305.6">D1_3</text>
<text x="496.3" y="301.8">Vcc</text>
<text x="505.8" y="301.8">VBOOT</text>
<text x="522" y="305.8">C72</text>
<text x="523" y="301.7">R102</text>
<text x="524.7" y="304">3</text>
<text x="541.8" y="303.1">S1</text>
<text x="541.8" y="305.6">G1</text>
<text x="553.8" y="300.5">D1_1</text>
<text x="553.8" y="303.1">D1_2</text>
<text x="553.8" y="305.6">D1_3</text>
<text x="209" y="306.9">SW3</text>
<text x="209" y="309.2">SW0</text>
<text x="217.9" y="306.9">SW4</text>
<text x="217.9" y="309.2">SW1</text>
<text x="226.7" y="306.9">SW6</text>
<text x="226.7" y="309.2">SW2</text>
<text x="235.6" y="306.9">SW7</text>
<text x="235.6" y="309.2">SW3</text>
<text x="313.4" y="307.5">A4</text>
<text x="313.4" y="311.3">A5</text>
<text x="324.4" y="311.3">B5</text>
<text x="324.4" y="307.5">B4</text>
<text x="362.7" y="307">R64</text>
<text x="362.8" y="309.3">10k</text>
<text x="380.1" y="306.9">IN</text>
<text x="380.1" y="312">SD</text>
<text x="388.5" y="306.9">DRV_HO</text>
<text x="389" y="312">BRIDGE</text>
<text x="405.9" y="308.1">4.7u</text>
<text x="425.6" y="308.1">S2</text>
<text x="425.6" y="310.7">G2</text>
<text x="437.6" y="308.1">D1_4</text>
<text x="437.6" y="310.7">D1_5</text>
<text x="478.9" y="307">R93</text>
<text x="479" y="309.3">10k</text>
<text x="496.3" y="306.9">IN</text>
<text x="496.3" y="312">SD</text>
<text x="504.7" y="306.9">DRV_HO</text>
<text x="505.2" y="312">BRIDGE</text>
<text x="522.1" y="308.1">4.7u</text>
<text x="541.8" y="308.1">S2</text>
<text x="541.8" y="310.7">G2</text>
<text x="553.8" y="308.1">D1_4</text>
<text x="553.8" y="310.7">D1_5</text>
<text x="144.7" y="312.1">+3.3V</text>
<text x="205.8" y="317.7">GND</text>
<text x="214.7" y="317.7">GND</text>
<text x="223.6" y="317.7">GND</text>
<text x="232.5" y="317.7">GND</text>
<text x="313.4" y="315.1">A6</text>
<text x="324.4" y="315.1">B6</text>
<text x="380.1" y="317">GND</text>
<text x="388.7" y="317">DRV_LO</text>
<text x="408.5" y="314.1">3</text>
<text x="415.8" y="312.1">GNDPWR</text>
<text x="425.6" y="313.2">D2_1</text>
<text x="425.6" y="315.8">D2_2</text>
<text x="437.6" y="313.2">D2_3</text>
<text x="437.6" y="315.8">D2_4</text>
<text x="496.3" y="317">GND</text>
<text x="504.9" y="317">DRV_LO</text>
<text x="524.7" y="314.1">3</text>
<text x="532" y="312.1">GNDPWR</text>
<text x="541.8" y="313.2">D2_1</text>
<text x="541.8" y="315.8">D2_2</text>
<text x="553.8" y="313.2">D2_3</text>
<text x="553.8" y="315.8">D2_4</text>
<text x="149.9" y="319.1">C19</text>
<text x="150" y="321.4">0.1u</text>
<text x="305.5" y="323.4">GND</text>
<text x="313.4" y="318.9">GND1</text>
<text x="321.7" y="318.9">GND2</text>
<text x="328.8" y="322.9">GNDPWR</text>
<text x="371" y="322.2">+12P</text>
<text x="372.6" y="323.5">GNDPWR</text>
<text x="437.6" y="318.3">D2_5</text>
<text x="488.8" y="323.5">GNDPWR</text>
<text x="553.8" y="318.3">D2_5</text>
<text x="27.4" y="328.6">+5V</text>
<text x="40.8" y="328.7">0.1u</text>
<text x="41.4" y="326.4">C5</text>
<text x="62.9" y="328.6">+5V</text>
<text x="76.4" y="328.7">0.1u</text>
<text x="77" y="326.4">C9</text>
<text x="101.9" y="328.5">SERIAL2</text>
<text x="104.6" y="326.2">J9</text>
<text x="120.7" y="328.6">+5V</text>
<text x="123.8" y="329.8">+3.3VD17</text>
<text x="144.9" y="328.5">GND</text>
<text x="189.2" y="327.9">+3.3V</text>
<text x="195.4" y="327.9">DIP_SW</text>
<text x="196.8" y="325.5">SW2</text>
<text x="375.9" y="329.3">C49</text>
<text x="411" y="329.8">+12P</text>
<text x="492.2" y="329.3">C67</text>
<text x="54.9" y="335.7">J1</text>
<text x="90.5" y="335.7">J6</text>
<text x="103.3" y="332.9">VBUS</text>
<text x="128.5" y="333.7">RX</text>
<text x="128.6" y="331.8">TX</text>
<text x="135.5" y="330.9">R14</text>
<text x="135.7" y="333.2">330</text>
<text x="135.7" y="335.1">330</text>
<text x="147.1" y="334.2">Vdd</text>
<text x="154.6" y="334.2">Vss</text>
<text x="170.1" y="335.6">+3.3V</text>
<text x="226.2" y="334.8">R46</text>
<text x="335.9" y="334.9">+3.3V</text>
<text x="376.1" y="331.6">0.1u</text>
<text x="386.4" y="334.5">U17</text>
<text x="425.1" y="335.5">NVMFD5C446NLT1G</text>
<text x="432" y="333.2">Q10</text>
<text x="492.3" y="331.6">0.1u</text>
<text x="502.6" y="334.5">U24</text>
<text x="541.3" y="335.5">NVMFD5C446NLT1G</text>
<text x="548.2" y="333.2">Q15</text>
<text x="54.9" y="338">SERIAL0</text>
<text x="90.4" y="338">SERIAL1</text>
<text x="105.9" y="338">D+</text>
<text x="135.7" y="337">10k</text>
<text x="147.1" y="336.1">GP0</text>
<text x="147.1" y="338">GP1</text>
<text x="147.1" y="339.9">nRST</text>
<text x="147.1" y="341.8">URx</text>
<text x="153.4" y="339.9">Vusb</text>
<text x="154.2" y="341.8">SCL</text>
<text x="155.4" y="336.1">D+</text>
<text x="166.4" y="338.6">GND</text>
<text x="214.8" y="339.9">R42</text>
<text x="220.5" y="337.4">R45</text>
<text x="220.5" y="339.7">10k</text>
<text x="226.3" y="337.2">10k</text>
<text x="253.7" y="336.7">2</text>
<text x="253.7" y="340.5">C</text>
<text x="263.1" y="340.5">C</text>
<text x="263.4" y="336.7">8</text>
<text x="341" y="342">C40</text>
<text x="358.3" y="336.8">+12P</text>
<text x="368.8" y="338.1">GNDPWR</text>
<text x="380.1" y="341.2">Vcc</text>
<text x="384.1" y="336.8">NCP5104</text>
<text x="389.6" y="341.2">VBOOT</text>
<text x="407.3" y="341">R79</text>
<text x="437.6" y="339.9">D1_1</text>
<text x="485" y="338.1">GNDPWR</text>
<text x="496.3" y="341.2">Vcc</text>
<text x="500.4" y="336.8">NCP5104</text>
<text x="505.8" y="341.2">VBOOT</text>
<text x="523" y="341">R104</text>
<text x="553.8" y="339.9">D1_1</text>
<text x="102.2" y="344" transform="rotate(-90 102.2 344)">Shield</text>
<text x="104.8" y="344" transform="rotate(-90 104.8 344)">GND</text>
<text x="106.4" y="343.1">ID</text>
<text x="147.1" y="343.7">UTx</text>
<text x="147.1" y="345.6">GP2</text>
<text x="154" y="343.7">SDA</text>
<text x="154.2" y="345.6">GP3</text>
<text x="209.1" y="342.5">R39</text>
<text x="209.1" y="344.8">10k</text>
<text x="214.8" y="342.2">10k</text>
<text x="253.7" y="344.3">1</text>
<text x="263.4" y="344.3">4</text>
<text x="268.7" y="345">GND</text>
<text x="315.8" y="345.7">25LC010A</text>
<text x="318.9" y="343.4">U9</text>
<text x="329.5" y="345.7">+3.3V</text>
<text x="341.1" y="344.3">0.1u</text>
<text x="362.1" y="346.4">R61</text>
<text x="380.1" y="346.2">IN</text>
<text x="388.5" y="346.2">DRV_HO</text>
<text x="405.8" y="345.1">C58</text>
<text x="405.9" y="347.4">4.7u</text>
<text x="408.5" y="343.3">3</text>
<text x="425.6" y="342.4">S1</text>
<text x="425.6" y="345">G1</text>
<text x="425.6" y="347.5">S2</text>
<text x="437.6" y="347.5">D1_4</text>
<text x="437.6" y="342.4">D1_2</text>
<text x="437.6" y="345">D1_3</text>
<text x="478.3" y="346.4">R90</text>
<text x="496.3" y="346.2">IN</text>
<text x="504.7" y="346.2">DRV_HO</text>
<text x="522" y="345.1">C73</text>
<text x="522.1" y="347.4">4.7u</text>
<text x="524.7" y="343.3">3</text>
<text x="541.8" y="342.4">S1</text>
<text x="541.8" y="345">G1</text>
<text x="541.8" y="347.5">S2</text>
<text x="553.8" y="347.5">D1_4</text>
<text x="553.8" y="342.4">D1_2</text>
<text x="553.8" y="345">D1_3</text>
<text x="102.3" y="352.6">GND</text>
<text x="222.3" y="352">GND</text>
<text x="303.8" y="352.2">10</text>
<text x="314.7" y="350.1">CS</text>
<text x="322.2" y="350.1">Vcc</text>
<text x="336" y="351.3">GND</text>
<text x="362.2" y="348.7">10k</text>
<text x="380.1" y="351.3">SD</text>
<text x="389" y="351.3">BRIDGE</text>
<text x="408.5" y="353.5">3</text>
<text x="415.8" y="351.5">GNDPWR</text>
<text x="425.6" y="350.1">G2</text>
<text x="425.6" y="352.6">D2_1</text>
<text x="437.6" y="352.6">D2_3</text>
<text x="437.6" y="350.1">D1_5</text>
<text x="478.4" y="348.7">10k</text>
<text x="496.3" y="351.3">SD</text>
<text x="505.2" y="351.3">BRIDGE</text>
<text x="524.7" y="353.5">3</text>
<text x="532" y="351.5">GNDPWR</text>
<text x="541.8" y="350.1">G2</text>
<text x="541.8" y="352.6">D2_1</text>
<text x="553.8" y="352.6">D2_3</text>
<text x="553.8" y="350.1">D1_5</text>
<text x="47.6" y="357.1">+3.3V</text>
<text x="64.9" y="355.1">C7</text>
<text x="65" y="357.4">1u</text>
<text x="91.5" y="357.1">+5V</text>
<text x="107.6" y="355.1">C12</text>
<text x="108.2" y="357.4">1u</text>
<text x="129.5" y="357.1">+3.3V</text>
<text x="140.4" y="359.7">+5V</text>
<text x="153.8" y="360">0.1u</text>
<text x="153.9" y="357.7">C22</text>
<text x="178.4" y="357.1">+3.3V</text>
<text x="189.3" y="359.7">+5V</text>
<text x="202.7" y="360">0.1u</text>
<text x="202.8" y="357.7">C33</text>
<text x="314.7" y="355.1">SO</text>
<text x="320.4" y="355.1">HOLD</text>
<text x="334.3" y="357.3">10</text>
<text x="380.1" y="356.4">GND</text>
<text x="388.7" y="356.4">DRV_LO</text>
<text x="425.6" y="355.1">D2_2</text>
<text x="437.6" y="355.1">D2_4</text>
<text x="437.6" y="357.7">D2_5</text>
<text x="496.3" y="356.4">GND</text>
<text x="504.9" y="356.4">DRV_LO</text>
<text x="541.8" y="355.1">D2_2</text>
<text x="553.8" y="355.1">D2_4</text>
<text x="553.8" y="357.7">D2_5</text>
<text x="65.1" y="364.9">J5</text>
<text x="107.7" y="364.9">J10</text>
<text x="139.2" y="364.2">R18</text>
<text x="188.1" y="364.2">R30</text>
<text x="314.7" y="360.2">WP</text>
<text x="314.7" y="365.3">Vss</text>
<text x="321.6" y="360.2">SCK</text>
<text x="323.7" y="365.3">SI</text>
<text x="333.7" y="360.1">R56</text>
<text x="334.3" y="362.4">10</text>
<text x="372.6" y="362.9">GNDPWR</text>
<text x="488.8" y="362.9">GNDPWR</text>
<text x="62" y="367.2">ADC_Vdd</text>
<text x="105.9" y="367.2">I/O_Vdd</text>
<text x="133.5" y="369">1k</text>
<text x="133.5" y="366.7">R12</text>
<text x="139.2" y="366.5">1k</text>
<text x="146.8" y="371.7">R22</text>
<text x="158.2" y="368.5">GND3</text>
<text x="167.9" y="369.1">ENC0</text>
<text x="168" y="366.8">J11</text>
<text x="182.3" y="369">1k</text>
<text x="182.4" y="366.7">R28</text>
<text x="188.1" y="366.5">1k</text>
<text x="195.7" y="371.7">R34</text>
<text x="207.1" y="368.5">GND3</text>
<text x="216.8" y="369.1">ENC2</text>
<text x="216.9" y="366.8">J13</text>
<text x="306.8" y="369.7">GND</text>
<text x="140.5" y="374.2">R20</text>
<text x="140.6" y="376.5">100</text>
<text x="147" y="374">100</text>
<text x="189.4" y="374.2">R32</text>
<text x="189.5" y="376.5">100</text>
<text x="195.9" y="374">100</text>
<text x="54.7" y="383.1">ADC</text>
<text x="54.9" y="380.8">J2</text>
<text x="97.5" y="378.2">J8</text>
<text x="97.8" y="380.6">I/O</text>
<text x="129.5" y="382.5">+3.3V</text>
<text x="153.9" y="383.1">C23</text>
<text x="178.4" y="382.5">+3.3V</text>
<text x="202.8" y="383.1">C34</text>
<text x="139.2" y="389.6">R19</text>
<text x="140.4" y="385.1">+5V</text>
<text x="153.8" y="385.4">0.1u</text>
<text x="188.1" y="389.6">R31</text>
<text x="189.3" y="385.1">+5V</text>
<text x="202.7" y="385.4">0.1u</text>
<text x="113.7" y="392.6">GND</text>
<text x="133.5" y="394.4">1k</text>
<text x="133.5" y="392.1">R13</text>
<text x="139.2" y="391.9">1k</text>
<text x="158.2" y="393.9">GND3</text>
<text x="167.9" y="394.5">ENC1</text>
<text x="168" y="392.2">J12</text>
<text x="182.3" y="394.4">1k</text>
<text x="182.4" y="392.1">R29</text>
<text x="188.1" y="391.9">1k</text>
<text x="207.1" y="393.9">GND3</text>
<text x="216.8" y="394.5">ENC3</text>
<text x="216.9" y="392.2">J14</text>
<text x="70.6" y="397.7">GND</text>
<text x="140.5" y="399.6">R21</text>
<text x="140.6" y="401.9">100</text>
<text x="146.8" y="397.1">R23</text>
<text x="147" y="399.4">100</text>
<text x="189.4" y="399.6">R33</text>
<text x="189.5" y="401.9">100</text>
<text x="195.7" y="397.1">R35</text>
<text x="195.9" y="399.4">100</text>
</g>
<g font-size="1.8">
<text x="85.1" y="20.9">FB_Control_OUT</text>
<text x="488.9" y="22.8">Motor0L</text>
<text x="85.1" y="28.5">FB_Control</text>
<text x="135.5" y="24.7">FB_Control_OUT</text>
<text x="488.8" y="25.3">Motor0R</text>
<text x="488.9" y="34.2">Motor1L</text>
<text x="90.1" y="41.2">FB_Control</text>
<text x="97.9" y="41.4">GND3</text>
<text x="488.8" y="36.7">Motor1R</text>
<text x="488.9" y="45.6">Motor2L</text>
<text x="77.5" y="53.9">SWCLK</text>
<text x="488.8" y="48.2">Motor2R</text>
<text x="77.5" y="56.4">SWDIO</text>
<text x="77.5" y="59">RST</text>
<text x="488.8" y="59.6">Motor3R</text>
<text x="488.9" y="57.1">Motor3L</text>
<text x="488.8" y="71">Motor4R</text>
<text x="488.9" y="68.5">Motor4L</text>
<text x="15" y="77.4">OSC_IN</text>
<text x="31.7" y="77.4">OSC_OUT</text>
<text x="49.8" y="83.1">RST</text>
<text x="307.3" y="78">PE0_IO</text>
<text x="307.3" y="80.6">PE1_IO</text>
<text x="307.3" y="83.1">LED0</text>
<text x="488.8" y="82.5">Motor5R</text>
<text x="488.9" y="79.9">Motor5L</text>
<text x="46.8" y="88.2">OSC_IN</text>
<text x="307.3" y="88.2">LED2</text>
<text x="307.3" y="85.6">LED1</text>
<text x="307.3" y="95.8">PE7_ROM_CS</text>
<text x="307.3" y="90.7">motor0_L_signal</text>
<text x="307.3" y="93.3">motor0_R_signal</text>
<text x="399.9" y="92">FB_OUT</text>
<text x="16.2" y="99.6">RST</text>
<text x="307.3" y="98.3">PE8_ROM_HOLD</text>
<text x="307.3" y="100.9">motor2_L_signal</text>
<text x="44.8" y="103.4">OSC_OUT</text>
<text x="307.3" y="103.4">PE10</text>
<text x="307.3" y="106">motor2_R_signal</text>
<text x="307.3" y="108.5">PE12_IO</text>
<text x="307.3" y="113.6">motor3_R_signal</text>
<text x="307.3" y="111">motor3_L_signal</text>
<text x="352.4" y="111">FB_OUT</text>
<text x="307.3" y="116.1">PE15_IO</text>
<text x="40.4" y="123.7">PA0_TIM5_CH1</text>
<text x="307.3" y="123.7">CAN1_RX</text>
<text x="39.4" y="128.8">PA2_ADC12_IN2</text>
<text x="39.4" y="131.4">PA3_ADC12_IN3</text>
<text x="40.4" y="126.3">PA0_TIM5_CH2</text>
<text x="307.3" y="128.8">PD2_DIPSW_0</text>
<text x="307.3" y="131.4">PD3_DIPSW_1</text>
<text x="307.3" y="126.3">CAN1_TX</text>
<text x="40.4" y="136.4">PA5_SPI1_SCK</text>
<text x="47" y="133.9">PA4_IO</text>
<text x="307.3" y="133.9">PD4_DIPSW_2</text>
<text x="307.3" y="136.4">PD5_USART2_TX</text>
<text x="412.7" y="135.8">Motor0L</text>
<text x="529" y="135.8">Motor3L</text>
<text x="39.6" y="141.5">PA7_SPI1_MOSI</text>
<text x="39.6" y="139">PA6_SPI1_MISO</text>
<text x="307.3" y="141.5">PD6_DIPSW_3</text>
<text x="307.3" y="139">PD6_USART2_RX</text>
<text x="362.6" y="139.6">MOTOR0L_PWM 2</text>
<text x="478.8" y="139.6">MOTOR3L_PWM 2</text>
<text x="37.4" y="149.1">PA10_USART1_RX</text>
<text x="38.6" y="146.6">PA9_USART1_TX</text>
<text x="47" y="144.1">PA8_IO</text>
<text x="307.3" y="149.1">ADRESS0_PD10</text>
<text x="307.3" y="144.1">PD8_USART3_TX</text>
<text x="307.3" y="146.6">PD9_USART3_RX</text>
<text x="402.6" y="144.7">Motor0L</text>
<text x="407.3" y="145.5">R70</text>
<text x="447.7" y="146">Motor0L</text>
<text x="518.8" y="144.7">Motor3L</text>
<text x="523.5" y="145.5">R95</text>
<text x="563.9" y="146">Motor3L</text>
<text x="46.1" y="154.2">PA12_IO</text>
<text x="46.1" y="151.7">PA11_IO</text>
<text x="307.3" y="151.7">ADRESS1_PD11</text>
<text x="307.3" y="154.2">PD12_TIM4_CH1</text>
<text x="39.4" y="161.8">PA15_TIM2_CH1</text>
<text x="46.9" y="159.3">SWCLK</text>
<text x="47.3" y="156.8">SWDIO</text>
<text x="307.3" y="161.8">ADRESS3_PD15</text>
<text x="307.3" y="159.3">ADRESS2_PD14</text>
<text x="307.3" y="156.8">PD13_TIM4_CH2</text>
<text x="39.4" y="169.5">PB0_ADC12_IN8</text>
<text x="39.4" y="172">PB1_ADC12_IN9</text>
<text x="307.3" y="172">PC1_ADC12_IN11</text>
<text x="307.3" y="169.5">PC0_ADC12_IN10</text>
<text x="40.4" y="177.1">PB3_TIM2_CH2</text>
<text x="40.4" y="179.6">PB4_TIM3_CH1</text>
<text x="40.9" y="174.5">PB2_ROM_WP</text>
<text x="307.3" y="174.5">PC2_ADC12_IN12</text>
<text x="307.3" y="177.1">PC3_ADC12_IN13</text>
<text x="307.3" y="179.6">PC4_ADC12_IN14</text>
<text x="362.4" y="179">MOTOR0R_PWM 2</text>
<text x="412.6" y="175.2">Motor0R</text>
<text x="478.6" y="179">MOTOR3R_PWM 2</text>
<text x="528.8" y="175.2">Motor3R</text>
<text x="40.4" y="182.2">PB5_TIM3_CH2</text>
<text x="40.7" y="184.7">PB6_I2C1_SCL</text>
<text x="307.3" y="184.7">motor1_L_signal</text>
<text x="307.3" y="182.2">PC5_ADC12_IN15</text>
<text x="402.6" y="184.1">Motor0R</text>
<text x="407.3" y="184.8">R72</text>
<text x="447.7" y="185.3">Motor0R</text>
<text x="518.8" y="184.1">Motor3R</text>
<text x="523.5" y="184.8">R97</text>
<text x="563.9" y="185.3">Motor3R</text>
<text x="32.6" y="189.8">PB8_Buzzer_TIM10_CH1</text>
<text x="40.5" y="187.2">PB7_I2C1_SDA</text>
<text x="307.3" y="189.8">motor5_L_signal</text>
<text x="307.3" y="187.2">motor1_R_signal</text>
<text x="31.4" y="192.3">PB9_LCD_BL_TIM11_CH1</text>
<text x="49.5" y="197.4">SW1</text>
<text x="49.5" y="194.9">SW0</text>
<text x="307.3" y="192.3">motor5_R_signal</text>
<text x="307.3" y="194.9">RED</text>
<text x="307.3" y="197.4">GREEN</text>
<text x="49.5" y="199.9">SW2</text>
<text x="49.5" y="202.5">SW3</text>
<text x="307.3" y="199.9">BLUE</text>
<text x="307.3" y="202.5">LED3</text>
<text x="39" y="207.6">motor4_R_signal</text>
<text x="39.2" y="205">motor4_L_signal</text>
<text x="307.3" y="207.6">LED5</text>
<text x="307.3" y="205">LED4</text>
<text x="412.7" y="219">Motor1L</text>
<text x="529" y="219">Motor4L</text>
<text x="362.6" y="222.8">MOTOR1L_PWM 2</text>
<text x="402.6" y="227.9">Motor1L</text>
<text x="478.8" y="222.8">MOTOR4L_PWM 2</text>
<text x="518.8" y="227.9">Motor4L</text>
<text x="407.3" y="228.6">R74</text>
<text x="447.7" y="229.2">Motor1L</text>
<text x="523.5" y="228.6">R99</text>
<text x="563.9" y="229.2">Motor4L</text>
<text x="198.4" y="245">BLUE</text>
<text x="293" y="245.7">motor0_R_signal</text>
<text x="293.2" y="241.9">motor0_L_signal</text>
<text x="332.7" y="241.9">MOTOR0L_PWM</text>
<text x="332.7" y="245.7">MOTOR0R_PWM</text>
<text x="196.9" y="247.6">GREEN</text>
<text x="199.5" y="250.1">RED</text>
<text x="293.2" y="249.5">motor1_L_signal</text>
<text x="332.7" y="249.5">MOTOR1L_PWM</text>
<text x="293" y="253.3">motor1_R_signal</text>
<text x="293.2" y="257.1">motor2_L_signal</text>
<text x="332.7" y="253.3">MOTOR1R_PWM</text>
<text x="332.7" y="257.1">MOTOR2L_PWM</text>
<text x="44.7" y="259.6">CAN_HGND3</text>
<text x="44.9" y="262.2">CAN_L</text>
<text x="75.8" y="259.6">CAN_HGND3</text>
<text x="76" y="262.2">CAN_L</text>
<text x="131.9" y="260.3">PB7_I2C1_SDA</text>
<text x="132.1" y="262.8">PB6_I2C1_SCL</text>
<text x="293" y="260.9">motor2_R_signal</text>
<text x="332.7" y="260.9">MOTOR2R_PWM</text>
<text x="362.4" y="262.2">MOTOR1R_PWM 2</text>
<text x="412.6" y="258.4">Motor1R</text>
<text x="478.6" y="262.2">MOTOR4R_PWM 2</text>
<text x="528.8" y="258.4">Motor4R</text>
<text x="203.1" y="264.7">LED0</text>
<text x="212" y="264.7">LED1</text>
<text x="220.9" y="264.7">LED2</text>
<text x="229.8" y="264.7">LED3</text>
<text x="238.7" y="264.7">LED4</text>
<text x="247.6" y="264.7">LED5</text>
<text x="402.6" y="267.3">Motor1R</text>
<text x="407.3" y="268">R76</text>
<text x="447.7" y="268.5">Motor1R</text>
<text x="518.8" y="267.3">Motor4R</text>
<text x="523" y="268">R101</text>
<text x="563.9" y="268.5">Motor4R</text>
<text x="29.2" y="285.7">CAN1_RX 4</text>
<text x="29.4" y="283.1">CAN1_TX 1</text>
<text x="61.1" y="285.7">7 CAN_H</text>
<text x="131.1" y="285.7">PB9_LCD_BL_TIM11_CH1</text>
<text x="61.1" y="290.7">6 CAN_L</text>
<text x="77.7" y="289.5">PB8_Buzzer_TIM10_CH1</text>
<text x="293" y="299">motor3_R_signal</text>
<text x="293.2" y="295.2">motor3_L_signal</text>
<text x="332.7" y="295.2">MOTOR3L_PWM</text>
<text x="332.7" y="299">MOTOR3R_PWM</text>
<text x="208.3" y="301.5">SW0</text>
<text x="217.2" y="301.5">SW1</text>
<text x="226.1" y="301.5">SW2</text>
<text x="234.9" y="301.5">SW3</text>
<text x="293.2" y="302.8">motor4_L_signal</text>
<text x="332.7" y="302.8">MOTOR4L_PWM</text>
<text x="362.6" y="306">MOTOR2L_PWM 2</text>
<text x="412.7" y="302.2">Motor2L</text>
<text x="478.8" y="306">MOTOR5L_PWM 2</text>
<text x="529" y="302.2">Motor5L</text>
<text x="293" y="306.6">motor4_R_signal</text>
<text x="293.2" y="310.4">motor5_L_signal</text>
<text x="332.7" y="310.4">MOTOR5L_PWM</text>
<text x="332.7" y="306.6">MOTOR4R_PWM</text>
<text x="402.6" y="311.1">Motor2L</text>
<text x="407.3" y="311.8">R78</text>
<text x="518.8" y="311.1">Motor5L</text>
<text x="523" y="311.8">R103</text>
<text x="293" y="314.2">motor5_R_signal</text>
<text x="332.7" y="314.2">MOTOR5R_PWM</text>
<text x="447.7" y="312.3">Motor2L</text>
<text x="563.9" y="312.3">Motor5L</text>
<text x="163.8" y="335.2">D+</text>
<text x="207" y="331.4">PD2_DIPSW_0</text>
<text x="207" y="333.9">PD3_DIPSW_1</text>
<text x="233.9" y="335.8">ADRESS1_PD11</text>
<text x="270.5" y="335.8">ADRESS3_PD15</text>
<text x="28.5" y="339.6">PA10_USART1_RX</text>
<text x="29.7" y="337.1">PA9_USART1_TX GND3</text>
<text x="65.1" y="339.6">PD9_USART3_RX</text>
<text x="65.3" y="337.1">PD8_USART3_TX GND3</text>
<text x="110" y="339.6">2 D-</text>
<text x="110" y="337.1">3 D+</text>
<text x="126.2" y="340.9">PD5_USART2_TX</text>
<text x="126.5" y="341.4">ACTIVE</text>
<text x="135.5" y="340.4">R17</text>
<text x="207" y="339">PD6_DIPSW_3</text>
<text x="207" y="336.5">PD4_DIPSW_2</text>
<text x="412.6" y="341.5">Motor2R</text>
<text x="528.8" y="341.5">Motor5R</text>
<text x="126" y="342.8">PD6_USART2_RX</text>
<text x="135.7" y="342.7">330</text>
<text x="233.9" y="343.5">ADRESS0_PD10</text>
<text x="245.8" y="345">GND</text>
<text x="270.5" y="343.5">ADRESS2_PD14</text>
<text x="362.4" y="345.4">MOTOR2R_PWM 2</text>
<text x="478.6" y="345.4">MOTOR5R_PWM 2</text>
<text x="296.7" y="349.2">PE7_ROM_CS</text>
<text x="303.2" y="349.9">R54</text>
<text x="402.6" y="350.4">Motor2R</text>
<text x="407.3" y="351.2">R80</text>
<text x="447.7" y="351.7">Motor2R</text>
<text x="518.8" y="350.4">Motor5R</text>
<text x="523" y="351.2">R105</text>
<text x="563.9" y="351.7">Motor5R</text>
<text x="287.2" y="354.2">PA6_SPI1_MISO</text>
<text x="296.2" y="359.3">PB2_ROM_WP</text>
<text x="331.5" y="354.2">ROM_PE8_HOLD</text>
<text x="333.7" y="355">R55</text>
<text x="339.1" y="359.3">PA5_SPI1_SCK</text>
<text x="339.1" y="364.4">PA7_SPI1_MOSI</text>
<text x="32.7" y="369.5">PC0_ADC12_IN10</text>
<text x="84" y="369.5">PE0_IO</text>
<text x="32.7" y="372">PC1_ADC12_IN11</text>
<text x="32.7" y="374.6">PC2_ADC12_IN12</text>
<text x="32.7" y="377.1">PC3_ADC12_IN13</text>
<text x="83" y="374.6">PE12_IO</text>
<text x="83" y="377.1">PE15_IO</text>
<text x="84" y="372">PE1_IO</text>
<text x="146" y="375.8">PA0_TIM5_CH2</text>
<text x="194.9" y="375.8">PB3_TIM2_CH2</text>
<text x="32.7" y="382.2">PC5_ADC12_IN15</text>
<text x="32.7" y="379.6">PC4_ADC12_IN14</text>
<text x="83.9" y="379.6">PA4_IO</text>
<text x="83.9" y="382.2">PA8_IO</text>
<text x="146" y="378.4">PA0_TIM5_CH1</text>
<text x="194.9" y="378.4">PA15_TIM2_CH1</text>
<text x="33.7" y="389.8">PA2_ADC12_IN2</text>
<text x="33.7" y="384.7">PB0_ADC12_IN8</text>
<text x="33.7" y="387.3">PB1_ADC12_IN9</text>
<text x="82.9" y="387.3">PA12_IO</text>
<text x="82.9" y="384.7">PA11_IO</text>
<text x="33.7" y="392.3">PA3_ADC12_IN3</text>
<text x="146" y="401.2">PD13_TIM4_CH2</text>
<text x="194.9" y="401.2">PB5_TIM3_CH2</text>
<text x="146" y="403.8">PD12_TIM4_CH1</text>
<text x="194.9" y="403.8">PB4_TIM3_CH1</text>
</g>
<g font-size="1.4" fill="#008484">
<text x="193.3" y="22.5">DIODE</text>
<text x="194.3" y="20.6">D24</text>
<text x="266.4" y="20">DIODE</text>
<text x="267.3" y="18.1">D33</text>
<text x="152.7" y="28.9">DIODE</text>
<text x="153.6" y="27">D23</text>
<text x="267.3" y="28.2">D34</text>
<text x="354.6" y="26.9">DIODE</text>
<text x="355.6" y="25">D35</text>
<text x="125.4" y="33.9">DIODE</text>
<text x="126.3" y="31.9">D16</text>
<text x="266.4" y="30.2">DIODE</text>
<text x="139.2" y="39.1">DIODE</text>
<text x="139.4" y="37.1">D20</text>
<text x="85.7" y="47.3">D12</text>
<text x="84.8" y="49.2">DIODE</text>
<text x="453.7" y="65">DIODE</text>
<text x="454.6" y="63.1">D56</text>
<text x="411.5" y="94.3">D47</text>
<text x="410.5" y="96.2">DIODE</text>
<text x="423.7" y="99.1">VI</text>
<text x="430.3" y="99.1">VO</text>
<text x="395.8" y="105.1">DIODE</text>
<text x="395.9" y="103.2">D39</text>
<text x="428.5" y="102.9" transform="rotate(-90 428.5 102.9)">GND</text>
<text x="405.4" y="125.3">DIODE</text>
<text x="406.4" y="123.4">D40</text>
<text x="521.6" y="125.3">DIODE</text>
<text x="522.6" y="123.4">D50</text>
<text x="405.4" y="164.7">DIODE</text>
<text x="406.4" y="162.8">D41</text>
<text x="521.6" y="164.7">DIODE</text>
<text x="522.6" y="162.8">D51</text>
<text x="405.4" y="208.5">DIODE</text>
<text x="406.4" y="206.6">D42</text>
<text x="521.6" y="208.5">DIODE</text>
<text x="522.6" y="206.6">D52</text>
<text x="406.4" y="245.9">D43</text>
<text x="522.6" y="245.9">D53</text>
<text x="405.4" y="247.9">DIODE</text>
<text x="521.6" y="247.9">DIODE</text>
<text x="105.1" y="272">DIODE</text>
<text x="106" y="270.1">D14</text>
<text x="405.4" y="291.7">DIODE</text>
<text x="406.4" y="289.8">D44</text>
<text x="521.6" y="291.7">DIODE</text>
<text x="522.6" y="289.8">D54</text>
<text x="31.4" y="329.9">DIODE</text>
<text x="32.8" y="328">D1</text>
<text x="67" y="329.9">DIODE</text>
<text x="67.9" y="328">D10</text>
<text x="114.6" y="329.9">DIODE</text>
<text x="115.5" y="328">D15</text>
<text x="406.4" y="329.1">D45</text>
<text x="522.6" y="329.1">D55</text>
<text x="405.4" y="331.1">DIODE</text>
<text x="521.6" y="331.1">DIODE</text>
<text x="52.4" y="358.5">DIODE</text>
<text x="53.7" y="356.5">D7</text>
<text x="95.6" y="358.5">DIODE</text>
<text x="96.5" y="356.5">D13</text>
<text x="145.4" y="359.1">D21</text>
<text x="194.3" y="359.1">D25</text>
<text x="144.4" y="361">DIODE</text>
<text x="193.3" y="361">DIODE</text>
<text x="144.4" y="386.4">DIODE</text>
<text x="145.4" y="384.5">D22</text>
<text x="193.3" y="386.4">DIODE</text>
<text x="194.3" y="384.5">D26</text>
</g>
<g font-size="1.4" fill="#840000">
<text x="265" y="22.1">2</text>
<text x="271.4" y="22.1">1</text>
<text x="192" y="24.7">2</text>
<text x="198.4" y="24.7">1</text>
<text x="353.3" y="29.1">1</text>
<text x="359.7" y="29.1">2</text>
<text x="136.9" y="34.8" transform="rotate(-90 136.9 34.8)">1</text>
<text x="151.4" y="31">2</text>
<text x="157.7" y="31">1</text>
<text x="265" y="32.3">2</text>
<text x="271.4" y="32.3">1</text>
<text x="124.1" y="36.1">1</text>
<text x="130.4" y="36.1">2</text>
<text x="136.9" y="41.2" transform="rotate(-90 136.9 41.2)">2</text>
<text x="83.4" y="51.4">2</text>
<text x="89.8" y="51.4">1</text>
<text x="452.4" y="67.2">1</text>
<text x="458.7" y="67.2">2</text>
<text x="393.4" y="100.9" transform="rotate(-90 393.4 100.9)">1</text>
<text x="409.2" y="98.3">2</text>
<text x="415.5" y="98.3">1</text>
<text x="393.4" y="107.2" transform="rotate(-90 393.4 107.2)">2</text>
<text x="404.1" y="127.6">1</text>
<text x="410.5" y="127.6">2</text>
<text x="520.3" y="127.6">1</text>
<text x="526.7" y="127.6">2</text>
<text x="404.1" y="166.9">1</text>
<text x="410.5" y="166.9">2</text>
<text x="520.3" y="166.9">1</text>
<text x="526.7" y="166.9">2</text>
<text x="404.1" y="210.7">1</text>
<text x="410.5" y="210.7">2</text>
<text x="520.3" y="210.7">1</text>
<text x="526.7" y="210.7">2</text>
<text x="404.1" y="250.1">1</text>
<text x="410.5" y="250.1">2</text>
<text x="520.3" y="250.1">1</text>
<text x="526.7" y="250.1">2</text>
<text x="103.8" y="274.2">1</text>
<text x="110.1" y="274.2">2</text>
<text x="404.1" y="293.9">1</text>
<text x="410.5" y="293.9">2</text>
<text x="520.3" y="293.9">1</text>
<text x="526.7" y="293.9">2</text>
<text x="30.1" y="332">2</text>
<text x="36.4" y="332">1</text>
<text x="65.7" y="332">2</text>
<text x="72" y="332">1</text>
<text x="113.3" y="332">2</text>
<text x="119.6" y="332">1</text>
<text x="404.1" y="333.3">1</text>
<text x="410.5" y="333.3">2</text>
<text x="520.3" y="333.3">1</text>
<text x="526.7" y="333.3">2</text>
<text x="51.1" y="360.6">2</text>
<text x="57.4" y="360.6">1</text>
<text x="94.2" y="360.6">2</text>
<text x="100.6" y="360.6">1</text>
<text x="143.1" y="363.1">2</text>
<text x="149.5" y="363.1">1</text>
<text x="192" y="363.1">2</text>
<text x="198.4" y="363.1">1</text>
<text x="143.1" y="388.5">2</text>
<text x="149.5" y="388.5">1</text>
<text x="192" y="388.5">2</text>
<text x="198.4" y="388.5">1</text>
</g>
<g font-size="1.1" fill="#008484">
<text x="137.5" y="31.1">1</text>
<text x="148.9" y="31.1">2</text>
<text x="394.1" y="98.4">1</text>
<text x="405.5" y="98.4">2</text>
</g>
</g></defs>
<g fill="none" stroke="#840000" stroke-width=".26">
<path d="M10 10.2h574v400h-574zM12 12.2h570v396h-570zM52.1 19.2v2.6h1.2M52.1 19.2l-.8 1.3M52.1 19.2l.7 1.3M60 10.2v2M110 10.2v2M160 10.2v2M210 10.2v2M260 10.2v2M310 10.2v2M360 10.2v2"/>
<path d="M367 19.2h17.8v12.7h-17.8zM407.7 17.3l-.8 1.3M407.7 17.3v2.6M407.7 17.3l.7 1.3M410 10.2v2M411.5 19.9v5M414 19.9v5M419.1 18.6l1-.7-1-.6-1 .6 1 .7v1.3M419.1 19.9h.1M440.7 18.6h2.5M442 18.6h1.2v2.5h6.4M444.5 19.9l2.5 1.2-2.5 1.3z"/>
<path d="M460 10.2v2M510 10.2v2M536.5 11.8h.8M560 10.2v2M18.8 29.5h12.9l.7 1.1-.7 1.2h-12.9zM19.4 30.6l.7-.1v-.4l-.7-.2v1.3M19.7 30.6l.4 .6M21 38.4h10.7l.7 1.1-.7 1.2h-10.7zM21 20.6h10.7l.7 1.2-.7 1.1h-10.7zM22.4 39a.56 .56 0 0 0-.8 .5 .56 .56 0 0 0 .8 .5M22.4 21.2a.56 .56 0 0 0-.8 .5 .56 .56 0 0 0 .8 .5M32.4 21.8h1.3"/>
<path d="M32.4 30.6h1.3M32.4 39.5h1.3M33.7 38.5h5v2.1h-5zM33.7 29.6h5v2.1h-5zM33.7 20.7h5v2.1h-5zM38.7 21.8h8.9M38.7 30.6h8.9M38.7 39.5h8.9M42.5 29.4l2.6 1.2-2.6 1.3zM42.5 38.3l2.6 1.2-2.6 1.3zM42.5 20.5l2.6 1.3-2.6 1.2zM45.1 20.5v2.5"/>
<path d="M45.1 29.4v2.5M45.1 38.3v2.5M47.1 29.1v-.7h-.7h.7l-1.5 1.5M47.1 38v-.7h-.7h.7l-1.5 1.5M47.1 20.2v-.7h-.7h.7l-1.5 1.5M48.4 29.1v-.7h-.8h.8l-1.5 1.5M48.4 38v-.7h-.8h.8l-1.5 1.5M48.4 20.2v-.7h-.8h.8l-1.5 1.5M52.1 28.1v2.5h1.2M52.1 28.1l-.8 1.3M52.1 28.1l.7 1.3M53.3 29.6h5.1v2.1h-5.1z"/>
<path d="M53.3 20.7h5.1v2.1h-5.1zM58.4 30.6h8.9v1.3h1.3l-1.3 1.3-1.3-1.3h1.3M58.4 21.8h8.9M62.2 29.4l2.6 1.2-2.6 1.3zM62.2 20.5l2.6 1.3-2.6 1.2zM64.8 20.5v2.5M64.8 29.4v2.5M66.8 29.1v-.7h-.8h.8l-1.5 1.5M66.8 20.2v-.7h-.8h.8l-1.5 1.5M68.1 29.1v-.7h-.8h.8l-1.6 1.5M68.1 20.2v-.7h-.8h.8l-1.6 1.5M75.6 21.1v2.8"/>
<path d="M75.6 26v2.7M82.8 22.4h2v5.1h-2zM82.8 30h2v5.1h-2zM83.8 35.1v2.5h1.3l-1.3 1.3-1.3-1.3h1.3M83.8 21.1v1.3M83.8 27.5v2.5M99.7 31.3h5.1M104.8 28.7h10.1v15.3h-10.1zM104.8 36.4h-5.1v1.2h1.3l-1.3 1.3-1.3-1.3h1.3M106 21.1h2.8M110.9 21.1h2.8M114.9 31.3h5.1"/>
<path d="M114.9 36.4h5.1M126.4 36.4h-3.8v2.8M126.4 35.1v2.5M132.7 33.8v2.6h-3.8M132.7 33.8l-.7 1.3M132.7 33.8l.8 1.3M135.9 36.4h2.5M137.2 31.3h1.2a1.27 1.27 0 0 1 1.3-1.3 1.27 1.27 0 0 1 1.3 1.3 1.27 1.27 0 0 1 1.2-1.3 1.27 1.27 0 0 1 1.3 1.3 1.27 1.27 0 0 1 1.3-1.3 1.27 1.27 0 0 1 1.2 1.3 1.27 1.27 0 0 1 1.3-1.3 1.27 1.27 0 0 1 1.3 1.3h5.1M137.2 32.6v3.8M137.2 38.9v3.8M146.4 20h13l.6 1.1-.6 1.1h-13zM147 21.1l.7-.1v-.5l-.7-.1v1.3"/>
<path d="M147.3 21.1l.5 .6M149.9 33.8v2.8M149.9 38.7v2.7M156.2 31.3h3.8M156.2 30v2.6M167.6 22.4v2.5h5.1M167.6 26.8v2.8M167.6 31.7v2.8M167.6 22.4l-.7 1.3M167.6 22.4l.8 1.3M172.7 22.4h12.7v8.9h-12.7zM179.1 31.3v6.3h1.2l-1.2 1.3-1.3-1.3h1.3"/>
<path d="M185.4 24.9h8.9M190.5 26.8v2.8M190.5 31.7v2.8M196.8 23.7v2.5M200.7 22.4v2.5h-3.9M200.7 22.4l-.8 1.3M200.7 22.4l.7 1.3M202.6 34h10.8l.6 1.1-.6 1.1h-10.8zM204 34.5a.56 .56 0 0 0-.8 .5 .56 .56 0 0 0 .8 .5M216.5 30v1.3h1.3l-1.3 1.3-1.2-1.3h1.2M219.1 30h2.5M219.1 35.1h2.5"/>
<path d="M221.6 30.5l4.1 1.8M224.2 29.5v2M225.5 21.3h10.7l.7 1.1-.7 1.1h-10.7zM226.7 32.6h7.9M226.8 21.8a.56 .56 0 0 0-.7 .5 .56 .56 0 0 0 .7 .5M234.6 30.6v3.9M235.1 30.8h2.5v3.5h-.7M235.1 30.3v1M235.1 32v1.1M235.1 33.8v1M235.1 34.3h1.8M236.9 27.5v5.1h-1.8"/>
<path d="M236.9 34.3v3.3M237.2 32.3h.8l-.4 .6zM238.1 32.8l-1 .3M247.6 35.1l-.7 1.3M247.6 35.1v2.5M247.6 35.1l.8 1.3M249.9 21.3h13l.6 1.1-.6 1.1h-13zM250.5 22.3l.7-.1v-.4l-.7-.1v1.3M250.9 22.3l.4 .7M251.3 26.4h11.6l.6 1.1-.6 1.1h-11.6zM251.9 27.4h.5M252.6 26.8h-.7v1.2h.7"/>
<path d="M262.5 33.8h2v5.1h-2zM263.5 38.9v2.5h1.3l-1.3 1.3-1.2-1.3h1.2M263.5 22.4h3.8M266.1 27.5h5.3M267.3 32.6h-3.8v1.2M269.9 21.1v2.6M269.9 31.3v2.5M269.9 22.4h3.8v5.1h-1.8M271.4 25.6v3.8M271.9 25.7h2.5v3.6h-.7M271.9 25.2v1M271.9 27v1"/>
<path d="M271.9 28.7v1.1M271.9 29.3h1.8M273.7 29.3v3.3h-3.8M274.1 27.2h.7l-.4 .7zM275 27.7l-1.1 .3M277.5 31.4h10.7v2.3h-10.7l-.6-1.1zM286.9 31.8l.4 1.3 .5-1.3M290.7 23.2h11.6l.6 1.1-.6 1.1h-11.6zM291.3 24.2h.4M291.9 23.6h-.6v1.3h.6M302.9 23l1-.6-1-.6-1 .6 1 .6v1.3M302.9 24.3h.1"/>
<path d="M306.7 21.8v1.2h1.3l-1.3 1.3-1.3-1.3h1.3M308 21.8h3.8M308 24.3h3.8M311.8 20.5h2.5v5.1h-2.5zM311.8 24.2h1.3v.2h-1.3zM311.8 21.6h1.3v.3h-1.3zM343.5 26.8l-.7 1.3M343.5 26.8v2.6M343.5 26.8l.8 1.3M351.8 28.1l1-.6-1-.7-1 .7 1 .6v1.3M351.8 29.4h.1M351.8 29.4h3.8"/>
<path d="M355.6 28.1v2.5M358.1 29.4h8.9M360.2 30.9h1M360.7 30.4v1M361.9 33.7v4.6h1.3l-1.3 1.2-1.2-1.2h1.2M361.9 21.8h5.1M361.9 25.6h5.1M361.9 29.4v2.8M384.8 21.8h5.1M384.8 25.6h5.1M384.8 29.4h5.1M389.4 30.9h1"/>
<path d="M389.9 30.4v1M391.2 29.4v2.8M391.2 33.7v3.3M393.1 28.3h4.4v2.2h-4.4l-.7-1.1zM396.5 29.1h.5M396.7 28.7v1.1l.3 .1M400 39l.3-.7h2l-.2 .7M400.8 38.3l-.2 .7M401.3 37v1.3l-.2 .7M401.8 38.3l-.2 .7M408.9 24.9h7.7v10.2h-7.7zM411.5 35.1v5.1"/>
<path d="M414 35.1v5.1M423.5 39.1h11.9v2.2h-11.9l-.6-1.1zM426.9 20h11.9l.6 1.1-.6 1.1h-11.9zM440.7 21.1h2.5M447.7 20.5v-.6h-.7v2.5h-.6v-.6M447.7 28.7h2.5M452.8 25.7v2M455.3 26.7l-4.1 1.8M455.3 26.2h2.5M455.3 31.3h2.5M458.1 32.6h2v5h-2zM459.1 37.6v2.6l-.2 .7"/>
<path d="M459.1 31.3v1.3M460.4 26.2h5.3M464.8 35.1l1-.6-1-.7-1 .7 1 .6v1.3M464.8 36.4h.1M465.7 24.3v3.8M466.2 24.4h2.6v3.6h-.8M466.2 23.9v1M466.2 25.7v1M466.2 27.5v1M466.2 28h1.8M468 21.1v5.1h-1.8M468 28v3.3"/>
<path d="M468.2 25.7l1.1 .3M468.6 35.2h4.5v2.3h-4.5l-.6-1.1zM468.8 25.8l.3 .7h-.7zM472.1 36.1h.5M472.3 35.7v1l.3 .2M495.9 25.6h3.8M495.9 34.5h3.8M495.9 37h3.8M495.9 23h3.8M499.7 33.2h2.6v5.1h-2.6zM499.7 36.9h1.3v.2h-1.3zM499.7 34.3h1.3v.3h-1.3z"/>
<path d="M499.7 21.8h2.6v5h-2.6zM499.7 25.4h1.3v.3h-1.3zM499.7 22.9h1.3v.3h-1.3zM515 31.9l-.8 1.3M515 20.5v2.5M515 31.9v2.6M515 31.9l.7 1.3M515 20.5l-.8 1.3M515 20.5l.7 1.3M517.5 36.5l.3-.8h2l-.2 .8M517.5 25.1l.3-.8h2l-.2 .8M518.3 35.7l-.3 .8"/>
<path d="M518.3 24.3l-.3 .8M518.8 25.6h3.8M518.8 37h3.8M519.3 35.7l-.3 .8M519.3 24.3l-.3 .8M522.6 33.2h2.5v5.1h-2.5zM522.6 36.9h1.3v.2h-1.3zM522.6 34.3h1.3v.3h-1.3zM522.6 21.8h2.5v5h-2.5zM522.6 25.4h1.3v.3h-1.3zM522.6 22.9h1.3v.3h-1.3zM522.6 34.5h-3.8v1.2l-.3 .8"/>
<path d="M522.6 23h-3.8v1.3l-.3 .8M32.4 45.9v2.5h1.3M32.4 45.9l-.8 1.3M32.4 45.9l.7 1.3M33.7 47.4h5v2h-5zM38.7 48.4h8.9v1.3h1.3l-1.3 1.3-1.2-1.3h1.2M42.5 47.2l2.6 1.2-2.6 1.3zM45.1 47.2v2.5M47.1 46.9v-.8h-.7h.7l-1.5 1.6M48.4 46.9v-.8h-.8h.8l-1.5 1.6M57.1 47.8h2.6v12.7h-2.6zM58.4 59.1h1.3v.3h-1.3z"/>
<path d="M58.4 56.6h1.3v.2h-1.3zM58.4 51.5h1.3v.2h-1.3zM58.4 48.9h1.3v.3h-1.3zM58.4 54h1.3v.3h-1.3zM59.7 59.2h3.8M59.7 49.1h3.8M59.7 51.6h3.8M59.7 54.1h3.8M59.7 56.7h3.8M65.4 49.1v1.2h1.3l-1.3 1.3-1.3-1.3h1.3M66.7 51.6h4.2M71.8 50.3a3.2 3.2 0 0 1 5 0"/>
<path d="M77.7 51.6h8M88.3 50.3v2.6M92.1 49.1v2.5h-3.8M92.1 49.1l-.8 1.2M92.1 49.1l.7 1.2M99.7 41.4h5.1M106 49.7l-.7 1.3M106 49.7v5.3M106 57.1v2.8M106 49.7l.8 1.3M114.9 41.4h5.1M114.9 52.2v2.8"/>
<path d="M114.9 57.1v2.8M122.6 41.2v2.8M123.8 52.2v2.8M123.8 57.1v2.8M132.7 52.2v2.8M132.7 57.1v2.8M141.6 52.2v2.8M141.6 57.1v2.8M149.9 44v1.3h1.2l-1.2 1.2-1.3-1.2h1.3M150.5 52.2v2.8M150.5 57.1v2.8M159.4 52.2v2.8"/>
<path d="M159.4 57.1v2.8M168.3 52.2v2.8M168.3 57.1v2.8M177.2 57.1v4h1.2l-1.2 1.3-1.3-1.3h1.3M177.2 52.2v2.8M367.8 58.1h11.9l.7 1.1-.7 1.1h-11.9zM380.4 47.8v2.5h1.2M380.4 59.2h1.2M380.4 47.8l-.8 1.3M380.4 47.8l.7 1.3M381.6 58.2h5.1v2h-5.1zM381.6 49.3h5.1v2.1h-5.1z"/>
<path d="M386.7 50.3h8.9M386.7 59.2h8.9M390.5 58l2.6 1.2-2.6 1.3zM390.5 49.1l2.6 1.2-2.6 1.3zM393.1 49.1v2.5M393.1 58v2.5M395.1 57.7v-.8h-.8h.8l-1.5 1.6M395.1 48.8v-.8h-.8h.8l-1.5 1.6M396.4 57.7v-.8h-.8h.8l-1.6 1.6M396.4 48.8v-.8h-.8h.8l-1.6 1.6M401.3 47.8v2.5h1.3M401.3 47.8l-.7 1.3"/>
<path d="M401.3 56.7v2.5h1.3M401.3 47.8l.8 1.3M401.3 56.7l-.7 1.3M401.3 56.7l.8 1.3M402.6 49.3h5.1v2.1h-5.1zM402.6 58.2h5.1v2h-5.1zM407.7 59.2h8.9v1.3l-.3 .8M407.7 50.3h8.9M411.5 49.1l2.5 1.2-2.5 1.3zM411.5 58l2.5 1.2-2.5 1.3zM414 49.1v2.5M414 58v2.5"/>
<path d="M416.1 48.8v-.8h-.8h.8l-1.6 1.6M416.1 57.7v-.8h-.8h.8l-1.6 1.6M417.3 48.8v-.8h-.7h.7l-1.5 1.6M417.3 57.7v-.8h-.7h.7l-1.5 1.6M433.9 49.2h11.9l.6 1.1-.6 1.2h-11.9zM436.9 56h2.5v5.1h-2.5zM438.1 59.7h1.3v.3h-1.3zM438.1 57.2h1.3v.2h-1.3zM439.4 59.9h3.8M443.2 54.8v2.5h-3.8M443.2 54.8l-.7 1.2M443.2 54.8l.8 1.2"/>
<path d="M446.4 59.9h8.9M451.5 49.7h10.1v12.7h-10.1zM455.3 57.3h2.5v3.8h-2.5zM457.8 40.9l.3-.7h2l-.2 .7M457.8 59.9h8.9M457.8 57.3l-2.5 3.8M458.6 40.2l-.3 .7M459.1 53.5v1.3h7.6M459.1 51l-3.8 1.2h-8.9M459.6 40.2l-.2 .7M461.6 52.2h5.1M467.4 53.7h11.7v2.2h-11.7l-.7-1.1z"/>
<path d="M495.9 57.3h3.8M495.9 59.9h3.8M495.9 48.4h3.8M495.9 45.9h3.8M499.7 56h2.6v5.1h-2.6zM499.7 59.7h1.3v.3h-1.3zM499.7 57.2h1.3v.2h-1.3zM499.7 44.6h2.6v5.1h-2.6zM499.7 48.3h1.3v.3h-1.3zM499.7 45.8h1.3v.2h-1.3zM553.7 51.6h12.7v12.7h-12.7zM10 60.2h2"/>
<path d="M22.2 77.6v2.8M22.9 77.6h1.9M28.6 77.6h1.9M31.1 77.6v2.8M47 77.3h5.1v2h-5.1zM47 78.3h-1.3v1.2h1.3l-1.3 1.3-1.3-1.3h1.3M52.1 78.3h8.9M61 74.5h238.7v137.1h-238.7zM123.2 64.3l-.8 1.3M123.2 64.3v10.2M123.2 64.3l.8 1.3M135.9 66.8v7.7"/>
<path d="M161.3 66.8v7.7M168.9 66.8v7.7M176.5 66.8v7.7M184.1 66.8v7.7M191.8 66.8v7.7M199.4 66.8v7.7M212.1 66.8v7.7M299.7 78.3h7.6M368 75.9h11.7l.7 1.1-.7 1.1h-11.7zM375.3 67h4.4l.7 1.1-.7 1.1h-4.4zM380.4 77h1.2M380.4 68.1h1.2"/>
<path d="M381.6 76h5.1v2h-5.1zM381.6 67.1h5.1v2h-5.1zM386.7 77h8.9v1.3l-.2 .7M386.7 68.1h8.9M390.5 75.7l2.6 1.3-2.6 1.3zM390.5 66.8l2.6 1.3-2.6 1.3zM393.1 66.8v2.6M393.1 75.7v2.6M394.3 79l.3-.7h2l-.2 .7M395.1 75.5v-.8h-.8h.8l-1.5 1.5M395.1 78.3l-.3 .7M395.1 66.6v-.8h-.8h.8l-1.5 1.6"/>
<path d="M396.1 78.3l-.2 .7M396.4 75.5v-.8h-.8h.8l-1.6 1.5M396.4 66.6v-.8h-.8h.8l-1.6 1.6M415.3 61.3l.2-.8h2.1l-.3 .8M416.1 60.5l-.3 .8M417.1 60.5l-.3 .8M447.7 75.7h2.5M450.2 76.2l4.1 1.8M450.8 67.5h3.9M452.8 75.2v2.1M454.7 66.2v2.5M455.3 78.3h2.5"/>
<path d="M457.2 67.5h3.8M457.5 79.5h2v5.1h-2zM458.5 78.3v1.2M459.1 78.3h5.3M464.4 76.4v3.8M464.9 78.3h1.8v5.1M464.9 76v1M464.9 77.8v1M464.9 79.5v1.1M464.9 76.5h1.8M466.7 76.5h.8v3.6h-2.6M466.7 73.2v3.3"/>
<path d="M467 77.8l1 .2M467.5 77.9l.4 .6h-.8zM476.9 72.6a3.2 3.2 0 0 0 0 5M478.2 67.5v4.2M478.2 78.5v4.2M495.9 68.7h3.8M495.9 71.3h3.8M499.7 78.9h2.6v5.1h-2.6zM499.7 67.5h2.6v5.1h-2.6zM499.7 71.2h1.3v.2h-1.3zM499.7 68.6h1.3v.3h-1.3zM582 60.2h2"/>
<path d="M21.6 99.9h2.5M22.2 82.5v2.8M24.1 98.6h5.1M26.7 85.3v1.2h1.2l-1.2 1.3-1.3-1.3h1.3M26.7 96.8v1.8M29.2 99.9h2.5M31.1 82.5v2.8M53.3 83.4h7.7M53.3 88.4h7.7M299.7 98.6h7.6M299.7 83.4h7.6M299.7 88.4h7.6"/>
<path d="M299.7 85.9h7.6M299.7 96.1h7.6M299.7 91h7.6M299.7 93.5h7.6M299.7 80.8h7.6M351.8 98.6h5.1M356.9 96.1h10.1v10.1h-10.1zM358.1 87.8h2.8M363 87.8h2.8M367 98.6h5.1M406.4 98.6h-1.3a1.27 1.27 0 0 0-1.2-1.3 1.27 1.27 0 0 0-1.3 1.3 1.27 1.27 0 0 0-1.3-1.3 1.27 1.27 0 0 0-1.3 1.3 1.27 1.27 0 0 0-1.2-1.3 1.27 1.27 0 0 0-1.3 1.3 1.27 1.27 0 0 0-1.3-1.3 1.27 1.27 0 0 0-1.2 1.3h-1.3v3.8M407 99.9v2.8"/>
<path d="M407.7 98.6h3.8M414 98.6h8.9M414 97.3v2.6M417.8 96.1l-.7 1.2M417.8 96.1v5.3M417.8 96.1l.8 1.2M422.9 96.1h10.2v7.6h-10.2zM433.1 98.6h5M438.1 96.1l-.7 1.2M438.1 96.1v5.3M438.1 96.1l.8 1.2M447.7 80.8h2.5"/>
<path d="M458.5 84.6v1.3M476.9 87.9l.2-.7h2.1l-.3 .7M477.6 87.2l-.2 .7M478.2 85.9v1.3l-.3 .7M478.7 87.2l-.3 .7M495.9 80.2h3.8M495.9 82.7h3.8M499.7 82.6h1.3v.2h-1.3zM499.7 80.1h1.3v.2h-1.3zM10 110.2h2M22.9 107.5h2.8M27.7 107.5h2.8"/>
<path d="M31.7 107.5v1.3h1.3l-1.3 1.2-1.2-1.2h1.2M53.3 103.7h7.7M299.7 101.1h7.6M299.7 103.7h7.6M299.7 106.2h7.6M299.7 108.8h7.6M299.7 111.3h7.6M299.7 113.8h7.6M299.7 116.4h7.6M335.3 113.3l.2-.7h2.1l-.3 .7M335.5 104.9h2.1v5.1h-2.1zM336 112.6l-.2 .7"/>
<path d="M336.5 110v2.6l-.2 .7M336.5 103.7v1.2M337.1 112.6l-.3 .7M342.5 104.9h2.1v5.1h-2.1zM343.5 103.7v1.2M343.5 110v1.3M350.5 103.2l.3-.8h2l-.2 .8M351.3 102.4l-.3 .8M351.8 108.5v2.8M352.3 102.4l-.3 .8M356.9 101.1h-5.1v1.3l-.3 .8M356.9 103.7h-5.1v2.8"/>
<path d="M367 101.1h5.1M367 103.7h5.1M372.7 117.6v5.4M372.7 117.6l-.7 1.3M372.7 117.6l.8 1.3M374.6 101.1v2.8M374.6 106v2.8M382.4 102.7h1M382.9 102.2v1M384.2 101.1v2.8M384.2 105.5v3.3M385.4 100h11.8v2.3h-11.8l-.6-1.2z"/>
<path d="M393.7 104.9v3.9M407 104.7v2.8M417.8 103.4v2.8M426.7 110.8l.3-.8h2l-.2 .8M427.5 110l-.3 .8M428 108.8v1.2l-.3 .8M428 103.7v2.5M428.5 110l-.3 .8M438.1 103.4v2.8M476.6 119.1h11.7l.6 1.1-.6 1.1h-11.7zM489.9 100.7h11.7l.7 1.1-.7 1.1h-11.7zM502.4 103.3h1"/>
<path d="M502.9 102.8v1M504.2 101.8v2.8M504.2 106.1v3.3M512.6 103.3h1M513.1 111.4l.2-.7h2.1l-.3 .7M513.1 102.8v1M513.8 110.7l-.2 .7M514.3 106.1v4.6l-.2 .7M514.3 101.8v2.8M514.9 110.7l-.3 .7M582 110.2h2M53.3 124h7.7"/>
<path d="M53.3 126.5h7.7M53.3 129.1h7.7M53.3 131.6h7.7M53.3 134.2h7.7M53.3 136.7h7.7M53.3 139.2h7.7M299.7 124h7.6M299.7 126.5h7.6M299.7 129.1h7.6M299.7 131.6h7.6M299.7 134.2h7.6M299.7 136.7h7.6"/>
<path d="M299.7 139.2h7.6M359.7 138.6h2v5.1h-2zM360.7 132.2v2.6M360.7 137.3v1.3M360.7 132.2l-.8 1.3M360.7 132.2l.7 1.3M371.5 129.8l.2-.7h2.1l-.3 .7M372.2 129.1l-.2 .7M372.7 125v4.1l-.2 .7M373.3 129.1l-.3 .7M376.6 134.8h2.5M376.6 139.9h2.5"/>
<path d="M379.1 132.2h17.8v20.4h-17.8zM396.9 134.8h2.5M396.9 139.9h2.5M402.6 127.8h3.8M402.6 136.1v2.8M405.1 139.9h1.3M406.4 138.9h5.1v2h-5.1zM406.4 126.5v2.6M411.5 139.9h1.2M412.7 125.3v2.5h-3.8M412.7 125.3l-.7 1.2M412.7 125.3l.8 1.2"/>
<path d="M419.7 136.1h5.1M419.7 138.6h5.1M424.8 131h17.8v22.8h-17.8zM442.6 136.1h5.1M442.6 138.6h5.1M442.6 133.5h5.1M448.3 132.4h11.8v2.2h-11.8l-.6-1.1zM464.5 133.7h11.7l.7 1.1-.7 1.1h-11.7zM475.9 138.6h2v5.1h-2zM476.9 137.3v1.3M487.7 129.8l.2-.7h2.1l-.3 .7M488.4 129.1l-.2 .7"/>
<path d="M488.9 125v4.1l-.2 .7M488.9 120.2v2.8M489.5 129.1l-.3 .7M492.8 134.8h2.5M492.8 139.9h2.5M495.3 132.2h17.8v20.4h-17.8zM513.1 134.8h2.5M513.1 139.9h2.5M518.8 136.1v2.8M518.8 127.8h3.8M521.3 139.9h1.3M522.6 138.9h5.1v2h-5.1z"/>
<path d="M522.6 126.5v2.6M525.1 127.8h3.9M527.7 139.9h1.3M529.6 126.7h11.8v2.2h-11.8l-.6-1.1zM535.9 136.1h5.1M535.9 138.6h5.1M541 131h17.8v22.8h-17.8zM558.8 136.1h5.1M558.8 138.6h5.1M558.8 133.5h5.1M564.5 132.4h11.8v2.2h-11.8l-.6-1.1zM53.3 141.8h7.7"/>
<path d="M53.3 144.3h7.7M53.3 146.9h7.7M53.3 149.4h7.7M53.3 151.9h7.7M53.3 154.5h7.7M53.3 157h7.7M53.3 159.6h7.7M299.7 141.8h7.6M299.7 144.3h7.6M299.7 146.9h7.6M299.7 149.4h7.6M299.7 151.9h7.6"/>
<path d="M299.7 154.5h7.6M299.7 157h7.6M299.7 159.6h7.6M360.7 143.7v1.2M372.7 157v5.3M372.7 157l-.7 1.3M372.7 157l.8 1.3M375.3 154.6l.2-.8h2.1l-.3 .8M376 153.8l-.2 .8M376.6 152.6v1.2l-.3 .8M376.6 144.9h2.5M376.6 150h2.5"/>
<path d="M377.1 153.8l-.3 .8M396.9 144.9h2.5M396.9 150h2.5M402.6 140.9v2.8M405.1 150h1.3M406.4 149h5.1v2h-5.1zM411.5 150h1.2M418.5 143.2l.2-.8h2.1l-.3 .8M419.2 142.4l-.2 .8M419.7 146.2h5.1M419.7 148.8h5.1M419.7 143.7h5.1"/>
<path d="M420.2 142.4l-.2 .8M424.8 141.1h-5.1v1.3l-.2 .8M442.6 141.1h5.1M442.6 146.2h5.1M442.6 148.8h5.1M442.6 143.7h5.1M442.6 151.3h5.1M476.6 158.4h11.7l.6 1.2-.6 1.1h-11.7zM476.9 143.7v1.2M488.9 159.6v2.7M491.5 154.6l.2-.8h2.1l-.3 .8M492.3 153.8l-.3 .8"/>
<path d="M492.8 152.6v1.2l-.3 .8M492.8 144.9h2.5M492.8 150h2.5M493.3 153.8l-.3 .8M513.1 144.9h2.5M513.1 150h2.5M518.8 140.9v2.8M521.3 150h1.3M522.6 149h5.1v2h-5.1zM527.7 150h1.3M534.7 143.2l.2-.8h2.1l-.3 .8M535.4 142.4l-.2 .8"/>
<path d="M535.9 146.2h5.1M535.9 148.8h5.1M535.9 143.7h5.1M536.4 142.4l-.2 .8M541 141.1h-5.1v1.3l-.2 .8M558.8 141.1h5.1M558.8 146.2h5.1M558.8 148.8h5.1M558.8 143.7h5.1M558.8 151.3h5.1M10 160.2h2M53.3 169.7h7.7"/>
<path d="M53.3 172.3h7.7M53.3 174.8h7.7M53.3 177.3h7.7M53.3 179.9h7.7M53.3 162.1h7.7M299.7 169.7h7.6M299.7 172.3h7.6M299.7 174.8h7.6M299.7 177.3h7.6M299.7 179.9h7.6M299.7 162.1h7.6M359 178h2.1v5h-2.1z"/>
<path d="M360 171.6v2.6M360 176.7v1.3M360 171.6l-.7 1.3M360 171.6l.8 1.3M371.5 169.2l.2-.8h2.1l-.3 .8M372.2 168.4l-.2 .8M372.7 164.4v4l-.2 .8M373.3 168.4l-.3 .8M376.6 174.2h2.5M376.6 179.2h2.5M379.1 171.6h17.8v20.3h-17.8zM396.9 174.2h2.5"/>
<path d="M396.9 179.2h2.5M402.6 167.2h3.8M402.6 175.4v2.8M405.1 179.2h1.3M406.4 178.2h5.1v2.1h-5.1zM406.4 165.9v2.5M411.5 179.2h1.2M412.7 164.6v2.6h-3.8M412.7 164.6l-.7 1.3M412.7 164.6l.8 1.3M419.7 175.4h5.1M419.7 178h5.1"/>
<path d="M424.8 170.3h17.8v22.9h-17.8zM442.6 175.4h5.1M442.6 178h5.1M442.6 172.9h5.1M448.3 171.8h11.8v2.2h-11.8l-.6-1.1zM463.9 173h11.7l.6 1.2-.6 1.1h-11.7zM475.2 178h2.1v5h-2.1zM476.2 176.7v1.3M487.7 169.2l.2-.8h2.1l-.3 .8M488.4 168.4l-.2 .8M488.9 164.4v4l-.2 .8M489.5 168.4l-.3 .8"/>
<path d="M492.8 174.2h2.5M492.8 179.2h2.5M495.3 171.6h17.8v20.3h-17.8zM513.1 174.2h2.5M513.1 179.2h2.5M518.8 175.4v2.8M518.8 167.2h3.8M521.3 179.2h1.3M522.6 178.2h5.1v2.1h-5.1zM522.6 165.9v2.5M525.1 167.2h3.9M527.7 179.2h1.3"/>
<path d="M529.6 166.1h11.8v2.2h-11.8l-.6-1.1zM535.9 175.4h5.1M535.9 178h5.1M541 170.3h17.8v22.9h-17.8zM558.8 175.4h5.1M558.8 178h5.1M558.8 172.9h5.1M564.5 171.8h11.8v2.2h-11.8l-.6-1.1zM582 160.2h2M53.3 182.4h7.7M53.3 195.1h7.7M53.3 197.7h7.7"/>
<path d="M53.3 185h7.7M53.3 187.5h7.7M53.3 190h7.7M53.3 192.6h7.7M299.7 182.4h7.6M299.7 195.1h7.6M299.7 197.7h7.6M299.7 185h7.6M299.7 187.5h7.6M299.7 190h7.6M299.7 192.6h7.6M360 183v1.3"/>
<path d="M375.3 194l.2-.8h2.1l-.3 .8M376 193.2l-.2 .8M376.6 191.9v1.3l-.3 .8M376.6 184.3h2.5M376.6 189.4h2.5M377.1 193.2l-.3 .8M396.9 184.3h2.5M396.9 189.4h2.5M402.6 180.3v2.7M405.1 189.4h1.3M406.4 188.4h5.1v2h-5.1zM411.5 189.4h1.2"/>
<path d="M418.5 182.5l.2-.7h2.1l-.3 .7M419.2 181.8l-.2 .7M419.7 185.6h5.1M419.7 188.1h5.1M419.7 183h5.1M420.2 181.8l-.2 .7M424.8 180.5h-5.1v1.3l-.2 .7M442.6 180.5h5.1M442.6 185.6h5.1M442.6 188.1h5.1M442.6 183h5.1M442.6 190.7h5.1"/>
<path d="M476.2 183v1.3M491.5 194l.2-.8h2.1l-.3 .8M492.3 193.2l-.3 .8M492.8 191.9v1.3l-.3 .8M492.8 184.3h2.5M492.8 189.4h2.5M493.3 193.2l-.3 .8M513.1 184.3h2.5M513.1 189.4h2.5M518.8 180.3v2.7M521.3 189.4h1.3M522.6 188.4h5.1v2h-5.1z"/>
<path d="M527.7 189.4h1.3M534.7 182.5l.2-.7h2.1l-.3 .7M535.4 181.8l-.2 .7M535.9 185.6h5.1M535.9 188.1h5.1M535.9 183h5.1M536.4 181.8l-.2 .7M541 180.5h-5.1v1.3l-.2 .7M558.8 180.5h5.1M558.8 185.6h5.1M558.8 188.1h5.1M558.8 183h5.1"/>
<path d="M558.8 190.7h5.1M10 210.2h2M53.3 200.2h7.7M53.3 202.7h7.7M53.3 205.3h7.7M53.3 207.8h7.7M170.2 211.6v7.6M175.3 211.6v7.6M180.3 211.6v7.6M185.4 211.6v7.6M190.5 211.6v7.6M203.2 211.6v10.4"/>
<path d="M215.9 211.6v10.4M299.7 200.2h7.6M299.7 202.7h7.6M299.7 205.3h7.6M299.7 207.8h7.6M360.7 215.4v2.6M360.7 215.4l-.8 1.3M360.7 215.4l.7 1.3M371.5 213l.2-.7h2.1l-.3 .7M372.2 212.3l-.2 .7M372.7 208.2v4.1l-.2 .7M372.7 200.8v5.4"/>
<path d="M372.7 200.8l-.7 1.3M372.7 200.8l.8 1.3M373.3 212.3l-.3 .7M376.6 218h2.5M379.1 215.4h17.8v20.4h-17.8zM396.9 218h2.5M402.6 211h3.8M402.6 219.2v2.8M406.4 209.7v2.6M412.7 208.4v2.6h-3.8M412.7 208.4l-.7 1.3M412.7 208.4l.8 1.3"/>
<path d="M419.7 219.2h5.1M424.8 214.2h17.8v22.8h-17.8zM442.6 219.2h5.1M442.6 216.7h5.1M448.3 215.6h11.8v2.2h-11.8l-.6-1.1zM464.5 216.9h11.7l.7 1.1-.7 1.1h-11.7zM476.6 202.3h11.7l.6 1.1-.6 1.1h-11.7zM487.7 213l.2-.7h2.1l-.3 .7M488.4 212.3l-.2 .7M488.9 208.2v4.1l-.2 .7M488.9 203.4v2.8M489.5 212.3l-.3 .7"/>
<path d="M492.8 218h2.5M495.3 215.4h17.8v20.4h-17.8zM513.1 218h2.5M518.8 211h3.8M518.8 219.2v2.8M522.6 209.7v2.6M525.1 211h3.9M529.6 209.9h11.8v2.2h-11.8l-.6-1.1zM535.9 219.2h5.1M541 214.2h17.8v22.8h-17.8zM558.8 219.2h5.1M558.8 216.7h5.1"/>
<path d="M564.5 215.6h11.8v2.2h-11.8l-.6-1.1zM582 210.2h2M203.2 224.1v2.8M215.9 224.1v4h1.3l-1.3 1.3-1.3-1.3h1.3M304.2 231.7v4.1h1.2l-1.2 1.2-1.3-1.2h1.3M304.2 224.3v5.4M304.2 224.3l-.8 1.3M304.2 224.3l.7 1.3M307.3 235.8v2.5h5.1M307.3 235.8l-.7 1.2M307.3 235.8l.8 1.2M312.4 235.8h15.3v31.7h-15.3z"/>
<path d="M332.7 235.8v2.5h-5M332.7 235.8l-.7 1.2M332.7 235.8l.8 1.2M335.9 236.5l.3-.7h2l-.3 .7M336.7 235.8l-.3 .7M337.2 231.7v4.1l-.3 .7M337.2 224.3v5.4M337.2 224.3l-.8 1.3M337.2 224.3l.7 1.3M337.7 235.8l-.3 .7M359.7 221.8h2v5.1h-2zM360.7 220.5v1.3"/>
<path d="M360.7 226.9v1.2M375.3 237.8l.2-.8h2.1l-.3 .8M376 237l-.2 .8M376.6 235.8v1.2l-.3 .8M376.6 223.1h2.5M376.6 228.1h2.5M376.6 233.2h2.5M377.1 237l-.3 .8M396.9 223.1h2.5M396.9 228.1h2.5M396.9 233.2h2.5M402.6 224.1v2.8"/>
<path d="M405.1 223.1h1.3M405.1 233.2h1.3M406.4 232.2h5.1v2h-5.1zM406.4 222h5.1v2.1h-5.1zM411.5 223.1h1.2M411.5 233.2h1.2M418.5 226.4l.2-.8h2.1l-.3 .8M419.2 225.6l-.2 .8M419.7 229.4h5.1M419.7 231.9h5.1M419.7 221.8h5.1M419.7 226.9h5.1"/>
<path d="M420.2 225.6l-.2 .8M424.8 224.3h-5.1v1.3l-.2 .8M442.6 224.3h5.1M442.6 229.4h5.1M442.6 231.9h5.1M442.6 221.8h5.1M442.6 226.9h5.1M442.6 234.5h5.1M475.9 221.8h2v5.1h-2zM476.9 220.5v1.3M476.9 226.9v1.2M491.5 237.8l.2-.8h2.1l-.3 .8"/>
<path d="M492.3 237l-.3 .8M492.8 235.8v1.2l-.3 .8M492.8 223.1h2.5M492.8 228.1h2.5M492.8 233.2h2.5M493.3 237l-.3 .8M513.1 223.1h2.5M513.1 228.1h2.5M513.1 233.2h2.5M518.8 224.1v2.8M521.3 223.1h1.3M521.3 233.2h1.3"/>
<path d="M522.6 222h5.1v2.1h-5.1zM522.6 232.2h5.1v2h-5.1zM527.7 223.1h1.3M527.7 233.2h1.3M534.7 226.4l.2-.8h2.1l-.3 .8M535.4 225.6l-.2 .8M535.9 229.4h5.1M535.9 231.9h5.1M535.9 221.8h5.1M535.9 226.9h5.1M536.4 225.6l-.2 .8M541 224.3h-5.1v1.3l-.2 .8"/>
<path d="M558.8 224.3h5.1M558.8 229.4h5.1M558.8 231.9h5.1M558.8 221.8h5.1M558.8 226.9h5.1M558.8 234.5h5.1M44.4 254.8h2.8M44.4 247.8l-.7 1.3M44.4 247.8v2.6M44.4 247.8l.8 1.3M49.3 254.8h2.8M52.7 254.8v1.3h1.3l-1.3 1.2-1.3-1.2h1.3"/>
<path d="M53.3 257.3h3.8M53.3 254.8h3.8M53.3 259.9h3.8M57.1 253.5h2.6v10.2h-2.6zM57.1 259.8h1.3v.2h-1.3zM57.1 254.7h1.3v.2h-1.3zM57.1 257.2h1.3v.3h-1.3zM75.6 254.8h2.8M75.6 247.8l-.8 1.3M75.6 247.8v2.6M75.6 247.8l.7 1.3M80.4 254.8h2.8"/>
<path d="M83.8 254.8v1.3h1.3l-1.3 1.2-1.3-1.2h1.3M84.5 257.3h3.8M84.5 254.8h3.8M84.5 259.9h3.8M88.3 253.5h2.5v10.2h-2.5zM88.3 259.8h1.2v.2h-1.2zM88.3 254.7h1.2v.2h-1.2zM88.3 257.2h1.2v.3h-1.2zM145 254.2h2.1v5h-2.1zM146 245.3l-.7 1.2M146 245.3v2.5M146 252.9v1.3"/>
<path d="M146 259.2v1.3M146 245.3l.8 1.2M151.4 256.7h2v5.1h-2zM152.4 255.4v1.3M159.4 258h2.8M160.7 250.4h2.7M160.7 247.8h2.7M164.2 258h2.8M165.5 250.4h7.9M165.5 247.8h7.9M167.6 258v1.2h1.3l-1.3 1.3-1.2-1.3h1.2M168.3 245.3h5.1"/>
<path d="M168.3 258h5.1M168.3 252.9h5.1M168.3 255.4h5.1M173.4 242.7h10.1v33.1h-10.1zM203.2 250.4h1.3M203.2 245.3h1.3M203.2 247.8h1.3M204.5 244.3h5v2h-5zM204.5 246.8h5v2h-5zM204.5 249.3h5v2.1h-5zM209.5 250.4h6.4M209.5 245.3h6.4"/>
<path d="M209.5 247.8h6.4M215.9 244h17.8v7.6h-17.8zM233.7 250.4h5.1v1.2h1.2l-1.2 1.3-1.3-1.3h1.3M233.7 245.3h5.1M233.7 247.8h5.1M307.3 257.3h5.1M307.3 253.5h5.1M307.3 249.7h5.1M307.3 245.9h5.1M307.3 242.1h5.1M327.7 257.3h5M327.7 253.5h5"/>
<path d="M327.7 249.7h5M327.7 245.9h5M327.7 242.1h5M360 254.8v2.5M360 259.9v1.3M360 254.8l-.7 1.3M360 254.8l.8 1.3M371.5 252.4l.2-.8h2.1l-.3 .8M372.2 251.6l-.2 .8M372.7 247.6v4l-.2 .8M372.7 240.2v5.3M372.7 240.2l-.7 1.3"/>
<path d="M372.7 240.2l.8 1.3M373.3 251.6l-.3 .8M376.6 257.3h2.5M379.1 254.8h17.8v20.3h-17.8zM396.9 257.3h2.5M402.6 250.4h3.8M402.6 258.6v2.8M406.4 249.1v2.5M412.7 247.8v2.6h-3.8M412.7 247.8l-.7 1.3M412.7 247.8l.8 1.3M419.7 258.6h5.1"/>
<path d="M424.8 253.5h17.8v22.9h-17.8zM442.6 258.6h5.1M442.6 256.1h5.1M448.3 255h11.8v2.2h-11.8l-.6-1.1zM463.9 256.2h11.7l.6 1.1-.6 1.2h-11.7zM476.2 259.9v1.3M476.6 241.6h11.7l.6 1.1-.6 1.2h-11.7zM487.7 252.4l.2-.8h2.1l-.3 .8M488.4 251.6l-.2 .8M488.9 247.6v4l-.2 .8M488.9 242.7v2.8M489.5 251.6l-.3 .8"/>
<path d="M492.8 257.3h2.5M495.3 254.8h17.8v20.3h-17.8zM513.1 257.3h2.5M518.8 258.6v2.8M518.8 250.4h3.8M522.6 249.1v2.5M525.1 250.4h3.9M529.6 249.2h11.8v2.3h-11.8l-.6-1.1zM535.9 258.6h5.1M541 253.5h17.8v22.9h-17.8zM558.8 258.6h5.1M558.8 256.1h5.1"/>
<path d="M564.5 255h11.8v2.2h-11.8l-.6-1.1zM10 260.2h2M33 273.6v4.1h1.3l-1.3 1.2-1.3-1.2h1.3M33 266.2l-.7 1.3M33 266.2v5.4M33 266.2l.8 1.3M50.2 275.8v5M53.3 262.4h3.8M57.1 262.3h1.3v.3h-1.3zM84.5 262.4h3.8M88.3 262.3h1.2v.3h-1.2zM102.2 274.5h3.8"/>
<path d="M106 273.2v2.6M108.6 274.5h3.8M112.6 278.3h2.1v5.1h-2.1zM113 271.9l-.7 1.3M113 271.9v2.6M113 271.9l.8 1.3M113.7 274.5h2.5M116.2 273.2h3.6v5.1h-3.6zM116.2 277h-2.5v1.3M119.8 273.2l2.5-2.5v10.1l-2.5-2.5M152.4 261.8v1.3M167.3 274.5h2v5.1h-2z"/>
<path d="M168.3 279.6v3.8l-1.9 1.9M168.3 270.7h5.1M168.3 260.5h5.1M168.3 263.1h5.1M168.3 265.6h5.1M173.4 273.2h-5.1v1.3M206.4 275.1h2.5l-1.3 2.6zM206.4 277.7h2.5M206.6 266.2h2.1v5.1h-2.1zM207.6 271.3v10.2h1.3l-1.3 1.2-1.2-1.2h1.2M207.6 265v1.2M208.4 279.4l1.5 1.6v-.8v.8h-.7"/>
<path d="M208.4 278.2l1.5 1.5v-.8v.8h-.7M215.3 275.1h2.5l-1.3 2.6zM215.3 277.7h2.5M215.5 266.2h2.1v5.1h-2.1zM216.5 271.3v10.2h1.3l-1.3 1.2-1.2-1.2h1.2M216.5 265v1.2M217.3 279.4l1.5 1.6v-.8v.8h-.7M217.3 278.2l1.5 1.5v-.8v.8h-.7M224.2 275.1h2.5l-1.3 2.6zM224.2 277.7h2.5M224.4 266.2h2v5.1h-2zM225.4 271.3v10.2h1.3l-1.3 1.2-1.2-1.2h1.2"/>
<path d="M225.4 265v1.2M226.2 279.4l1.5 1.6v-.8v.8h-.8M226.2 278.2l1.5 1.5v-.8v.8h-.8M233 275.1h2.6l-1.3 2.6zM233 277.7h2.6M233.3 266.2h2v5.1h-2zM234.3 271.3v10.2h1.3l-1.3 1.2-1.3-1.2h1.3M234.3 265v1.2M235.1 279.4l1.5 1.6v-.8v.8h-.8M235.1 278.2l1.5 1.5v-.8v.8h-.8M241.9 275.1h2.6l-1.3 2.6zM241.9 277.7h2.6"/>
<path d="M242.2 266.2h2v5.1h-2zM243.2 271.3v10.2h1.3l-1.3 1.2-1.3-1.2h1.3M243.2 265v1.2M244 279.4l1.5 1.6v-.8v.8h-.8M244 278.2l1.5 1.5v-.8v.8h-.8M250.8 275.1h2.6l-1.3 2.6zM250.8 277.7h2.6M251.1 266.2h2v5.1h-2zM252.1 271.3v10.2h1.3l-1.3 1.2-1.3-1.2h1.3M252.1 265v1.2M252.9 279.4l1.5 1.6v-.8v.8h-.8M252.9 278.2l1.5 1.5v-.8v.8h-.8"/>
<path d="M304.2 277.7v5.3M304.2 277.7l-.8 1.2M304.2 277.7l.7 1.2M307.3 261.2h5.1M312.4 265h-5.1v1.2h1.3l-1.3 1.3-1.2-1.3h1.2M327.7 265h5v1.2l-.2 .8M327.7 261.2h5M331.5 267l.2-.8h2.1l-.3 .8M332.2 266.2l-.2 .8M333.2 266.2l-.2 .8M337.2 277.7v5.3M337.2 277.7l-.8 1.2"/>
<path d="M337.2 277.7l.7 1.2M359 261.2h2.1v5h-2.1zM360 266.2v1.3M375.3 277.2l.2-.8h2.1l-.3 .8M376 276.4l-.2 .8M376.6 275.1v1.3l-.3 .8M376.6 262.4h2.5M376.6 267.5h2.5M376.6 272.6h2.5M377.1 276.4l-.3 .8M396.9 262.4h2.5M396.9 267.5h2.5"/>
<path d="M396.9 272.6h2.5M402.6 263.4v2.8M405.1 262.4h1.3M405.1 272.6h1.3M406.4 261.4h5.1v2h-5.1zM406.4 271.6h5.1v2h-5.1zM411.5 262.4h1.2M411.5 272.6h1.2M418.5 265.7l.2-.7h2.1l-.3 .7M419.2 265l-.2 .7M419.7 261.2h5.1M419.7 268.8h5.1"/>
<path d="M419.7 271.3h5.1M419.7 266.2h5.1M420.2 265l-.2 .7M424.8 263.7h-5.1v1.3l-.2 .7M442.6 261.2h5.1M442.6 263.7h5.1M442.6 268.8h5.1M442.6 271.3h5.1M442.6 266.2h5.1M442.6 273.9h5.1M475.2 261.2h2.1v5h-2.1zM476.2 266.2v1.3"/>
<path d="M491.5 277.2l.2-.8h2.1l-.3 .8M492.3 276.4l-.3 .8M492.8 275.1v1.3l-.3 .8M492.8 262.4h2.5M492.8 267.5h2.5M492.8 272.6h2.5M493.3 276.4l-.3 .8M513.1 262.4h2.5M513.1 267.5h2.5M513.1 272.6h2.5M518.8 263.4v2.8M521.3 262.4h1.3"/>
<path d="M521.3 272.6h1.3M522.6 261.4h5.1v2h-5.1zM522.6 271.6h5.1v2h-5.1zM527.7 262.4h1.3M527.7 272.6h1.3M534.7 265.7l.2-.7h2.1l-.3 .7M535.4 265l-.2 .7M535.9 261.2h5.1M535.9 268.8h5.1M535.9 271.3h5.1M535.9 266.2h5.1M536.4 265l-.2 .7"/>
<path d="M541 263.7h-5.1v1.3l-.2 .7M558.8 261.2h5.1M558.8 263.7h5.1M558.8 268.8h5.1M558.8 271.3h5.1M558.8 266.2h5.1M558.8 273.9h5.1M582 260.2h2M37.5 285.9h2.5M37.5 283.4h2.5M37.5 291h2.5M37.5 293.5h2.5"/>
<path d="M40 280.8h20.3v15.3h-20.3zM50.2 296.1v3.8h1.2l-1.2 1.3-1.3-1.3h1.3M60.3 285.9h2.6M60.3 291h2.6M98.4 289.7h1.3M99.7 288.7h5.1v2h-5.1zM104.8 289.7h7M111.8 290.4l1.9 1.9v3.8h1.2l-1.2 1.2-1.3-1.2h1.3M113.7 283.4v3.8l-1.9 1.9M153 285.9h1.3M154.3 284.9h5.1v2h-5.1zM159.4 285.9h7"/>
<path d="M166.4 286.6l1.9 1.9v3.8h1.2l-1.2 1.2-1.3-1.2h1.3M206.6 294.8h2.1v5.1h-2.1zM207.6 291v3.8M207.6 299.9v1.3M207.6 291l-.7 1.3M207.6 291l.8 1.3M215.5 294.8h2.1v5.1h-2.1zM216.5 291v3.8M216.5 299.9v1.3M216.5 291l-.7 1.3M216.5 291l.8 1.3M224.4 294.8h2v5.1h-2z"/>
<path d="M225.4 291l-.7 1.3M225.4 291v3.8M225.4 299.9v1.3M225.4 291l.8 1.3M233.3 294.8h2v5.1h-2zM234.3 291v3.8M234.3 299.9v1.3M234.3 291l-.7 1.3M234.3 291l.8 1.3M304.2 285v4.1h1.2l-1.2 1.3-1.3-1.3h1.3M307.3 289.1v2.5h5.1M307.3 299.3h5.1"/>
<path d="M307.3 295.4h5.1M307.3 289.1l-.7 1.3M307.3 289.1l.8 1.3M312.4 289.1h15.3v31.7h-15.3zM327.7 299.3h5M327.7 295.4h5M332.7 289.1v2.5h-5M332.7 289.1l-.7 1.3M332.7 289.1l.8 1.3M335.9 289.9l.3-.8h2l-.3 .8M336.7 289.1l-.3 .8M337.2 285v4.1l-.3 .8"/>
<path d="M337.7 289.1l-.3 .8M360.7 298.6v2.6M360.7 298.6l-.8 1.3M360.7 298.6l.7 1.3M371.5 296.2l.2-.8h2.1l-.3 .8M372.2 295.4l-.2 .8M372.7 291.4v4l-.2 .8M372.7 284v5.3M372.7 284l-.7 1.3M372.7 284l.8 1.3M373.3 295.4l-.3 .8M379.1 298.6h17.8v20.3h-17.8z"/>
<path d="M402.6 294.2h3.8M406.4 292.9v2.5M412.7 291.6v2.6h-3.8M412.7 291.6l-.7 1.3M412.7 291.6l.8 1.3M424.8 297.3h17.8v22.9h-17.8zM442.6 299.9h5.1M448.3 298.8h11.8v2.2h-11.8l-.6-1.1zM476.6 285.4h11.7l.6 1.2-.6 1.1h-11.7zM487.7 296.2l.2-.8h2.1l-.3 .8M488.4 295.4l-.2 .8M488.9 291.4v4l-.2 .8"/>
<path d="M488.9 286.6v2.7M489.5 295.4l-.3 .8M495.3 298.6h17.8v20.3h-17.8zM518.8 294.2h3.8M522.6 292.9v2.5M525.1 294.2h3.9M529.6 293.1h11.8v2.2h-11.8l-.6-1.1zM541 297.3h17.8v22.9h-17.8zM558.8 299.9h5.1M564.5 298.8h11.8v2.2h-11.8l-.6-1.1zM10 310.2h2M146.7 313.2v5.4"/>
<path d="M146.7 313.2l-.8 1.3M146.7 313.2l.7 1.3M204.6 307.5h1.8M206.4 305v5M207.6 310v3.9h1.3l-1.3 1.2-1.2-1.2h1.2M207.6 302.4v2.6M213.5 307.5h1.8M215.3 305v5M216.5 310v3.9h1.3l-1.3 1.2-1.2-1.2h1.2M216.5 302.4v2.6M222.4 307.5h1.8M224.2 305v5"/>
<path d="M225.4 310v3.9h1.3l-1.3 1.2-1.2-1.2h1.2M225.4 302.4v2.6M231.3 307.5h1.7M233 305v5M234.3 310v3.9h1.3l-1.3 1.2-1.3-1.2h1.3M234.3 302.4v2.6M307.3 314.5h5.1M307.3 310.7h5.1M307.3 306.9h5.1M307.3 303.1h5.1M312.4 318.3h-5.1v1.3h1.3l-1.3 1.2-1.2-1.2h1.2M327.7 318.3h5v1.3l-.2 .7"/>
<path d="M327.7 314.5h5M327.7 310.7h5M327.7 306.9h5M327.7 303.1h5M332.2 319.6l-.2 .7M333.2 319.6l-.2 .7M359.7 305h2v5h-2zM360.7 303.7v1.3M360.7 310v1.3M376.6 318.9v1.3l-.3 .8M376.6 301.2h2.5M376.6 306.2h2.5"/>
<path d="M376.6 311.3h2.5M376.6 316.4h2.5M396.9 301.2h2.5M396.9 306.2h2.5M396.9 311.3h2.5M396.9 316.4h2.5M402.6 302.4v2.8M402.6 307.3v2.7M405.1 306.2h1.3M405.1 316.4h1.3M406.4 305.2h5.1v2.1h-5.1zM406.4 315.4h5.1v2h-5.1z"/>
<path d="M411.5 306.2h1.2M411.5 316.4h1.2M418.5 309.5l.2-.7h2.1l-.3 .7M419.2 308.8l-.2 .7M419.7 302.4h5.1M419.7 312.6h5.1M419.7 315.1h5.1M419.7 305h5.1M419.7 310h5.1M420.2 308.8l-.2 .7M424.8 307.5h-5.1v1.3l-.2 .7M442.6 302.4h5.1"/>
<path d="M442.6 307.5h5.1M442.6 312.6h5.1M442.6 315.1h5.1M442.6 305h5.1M442.6 310h5.1M442.6 317.7h5.1M464.5 300h11.7l.7 1.2-.7 1.1h-11.7zM475.9 305h2v5h-2zM476.9 303.7v1.3M476.9 310v1.3M492.8 318.9v1.3l-.3 .8M492.8 301.2h2.5"/>
<path d="M492.8 306.2h2.5M492.8 311.3h2.5M492.8 316.4h2.5M513.1 301.2h2.5M513.1 306.2h2.5M513.1 311.3h2.5M513.1 316.4h2.5M518.8 302.4v2.8M518.8 307.3v2.7M521.3 306.2h1.3M521.3 316.4h1.3M522.6 305.2h5.1v2.1h-5.1z"/>
<path d="M522.6 315.4h5.1v2h-5.1zM527.7 306.2h1.3M527.7 316.4h1.3M534.7 309.5l.2-.7h2.1l-.3 .7M535.4 308.8l-.2 .7M535.9 302.4h5.1M535.9 312.6h5.1M535.9 315.1h5.1M535.9 305h5.1M535.9 310h5.1M536.4 308.8l-.2 .7M541 307.5h-5.1v1.3l-.2 .7"/>
<path d="M558.8 302.4h5.1M558.8 307.5h5.1M558.8 312.6h5.1M558.8 315.1h5.1M558.8 305h5.1M558.8 310h5.1M558.8 317.7h5.1M582 310.2h2M28.6 329.7v2.6h3.8M28.6 329.7l-.8 1.3M28.6 329.7l.7 1.3M34.9 332.3h6.6"/>
<path d="M34.9 331v2.5M43.6 332.3h2.8M47 332.3v1.2h1.3l-1.3 1.3-1.3-1.3h1.3M47.6 337.4h3.8M47.6 332.3h3.8M47.6 334.8h3.8M47.6 339.9h3.8M51.4 331h2.6v10.2h-2.6zM51.4 339.8h1.3v.2h-1.3zM51.4 337.2h1.3v.3h-1.3zM51.4 332.1h1.3v.3h-1.3zM51.4 334.7h1.3v.2h-1.3z"/>
<path d="M64.1 329.7l-.7 1.3M64.1 329.7v2.6h3.8M64.1 329.7l.8 1.3M70.5 332.3h6.6M70.5 331v2.5M79.1 332.3h2.8M82.5 332.3v1.2h1.3l-1.3 1.3-1.2-1.3h1.2M83.2 337.4h3.8M83.2 332.3h3.8M83.2 334.8h3.8M83.2 339.9h3.8M87 331h2.5v10.2h-2.5z"/>
<path d="M87 339.8h1.3v.2h-1.3zM87 337.2h1.3v.3h-1.3zM87 332.1h1.3v.3h-1.3zM87 334.7h1.3v.2h-1.3zM99.1 329.7h10.1v15.3h-10.1zM99.4 331.5h3.3v.3l-.2 1h-2.8zM101.6 335.2h.6l.7 1.3h1.2M102.2 335.2h2.6M103.5 333.9h-.6l-1.3 1.3h-.6M108.5 339.8h.7v.2h-.7zM108.5 337.2h.7v.3h-.7zM108.5 332.1h.7v.3h-.7z"/>
<path d="M109.2 337.4h2.6M109.2 332.3h6.4M109.2 339.9h2.6M118.1 331v2.5M121.9 329.7v2.6h-3.8M121.9 329.7l-.7 1.3M121.9 329.7l.8 1.3M125.7 337.4h2.6M125.7 335.4h8.9M125.7 331l-.7 1.3M125.7 331v2.5M125.7 331l.8 1.3"/>
<path d="M128.3 336.1l2.5 1.3-2.5 1.2zM128.3 334.2l2.5 1.2-2.5 1.3zM130.8 334.2v4.4M130.8 337.4h3.8M132.8 335.8v-.7h-.7h.7l-1.5 1.5M132.8 333.9v-.7h-.7h.7l-1.5 1.5M134.1 335.8v-.7h-.8h.8l-1.5 1.5M134.1 333.9v-.7h-.8h.8l-1.5 1.5M134.6 338.2h5.1v2.1h-5.1zM134.6 334.4h5.1v2.1h-5.1zM134.6 336.3h5.1v2.1h-5.1zM139.7 337.4h6.3"/>
<path d="M139.7 335.4h6.3M141 333.5h5M141 339.3h5M146 332.3h12.7v13.9h-12.7zM146.7 320.6v4.1h1.3l-1.3 1.2-1.3-1.2h1.3M158.7 333.5h5.1M158.7 337.4h5.1M158.7 339.3h5.1M158.7 335.4h5.1M168.3 333.5v1.3h1.2l-1.2 1.3-1.3-1.3h1.3M172.1 336.7l-.8 1.3M172.1 336.7v2.6"/>
<path d="M172.1 336.7l.7 1.3M191.1 339.3h5.1M191.1 329.1v2.5h5.1M191.1 334.2h5.1M191.1 336.7h5.1M191.1 329.1l-.7 1.3M191.1 329.1l.8 1.3M194.9 329.1h7.7v12.7h-7.7zM201.1 338.1l-3.9 1M201.1 335.6l-3.9 1M201.1 333l-3.9 1.1M201.1 330.5l-3.9 1"/>
<path d="M201.3 339.3h5.1M201.3 331.6h5.1M201.3 334.2h5.1M201.3 336.7h5.1M207 339.3v1.2M211.7 338h2v5.1h-2zM212.7 336.7v1.3M217.4 335.4h2.1v5.1h-2.1zM218.4 334.2v1.2M223.1 332.9h2.1v5.1h-2.1zM224.2 331.6v1.3M224.2 338v1.3"/>
<path d="M247.6 336.1h5.1M252.7 333.5h12.7v12.7h-12.7zM252.7 339.9h-5.1v1.3h1.3l-1.3 1.2-1.2-1.2h1.2M261.6 336.1l-2.5 3.8M265.4 339.9h5.1v1.3h1.3l-1.3 1.2-1.3-1.2h1.3M265.4 336.1h5.1M331.5 320.3l.2-.7h2.1l-.3 .7M337.8 336.1v5.3M337.8 336.1l-.7 1.3M337.8 336.1l.8 1.3M360 338v2.5M360 338l-.7 1.3"/>
<path d="M360 338l.8 1.3M371.5 335.6l.2-.8h2.1l-.3 .8M372.2 334.8l-.2 .8M372.7 330.8v4l-.2 .8M372.7 323.4v5.3M372.7 323.4l-.7 1.3M372.7 323.4l.8 1.3M373.3 334.8l-.3 .8M375.3 321l.2-.8h2.1l-.3 .8M376 320.2l-.2 .8M377.1 320.2l-.3 .8M379.1 338h17.8v20.3h-17.8z"/>
<path d="M402.6 333.5h3.8M406.4 332.3v2.5M412.7 331v2.5h-3.8M412.7 331l-.7 1.3M412.7 331l.8 1.3M424.8 336.7h17.8v22.9h-17.8zM442.6 339.3h5.1M448.3 338.1h11.8v2.3h-11.8l-.6-1.1zM463.9 339.4h11.7l.6 1.1-.6 1.1h-11.7zM476.6 324.8h11.7l.6 1.1-.6 1.1h-11.7zM487.7 335.6l.2-.8h2.1l-.3 .8M488.4 334.8l-.2 .8"/>
<path d="M488.9 330.8v4l-.2 .8M488.9 325.9v2.8M489.5 334.8l-.3 .8M491.5 321l.2-.8h2.1l-.3 .8M492.3 320.2l-.3 .8M493.3 320.2l-.3 .8M495.3 338h17.8v20.3h-17.8zM518.8 333.5h3.8M522.6 332.3v2.5M525.1 333.5h3.9M529.6 332.4h11.8v2.3h-11.8l-.6-1.2zM541 336.7h17.8v22.9h-17.8z"/>
<path d="M558.8 339.3h5.1M564.5 338.1h11.8v2.3h-11.8l-.6-1.1zM49.5 358.3l-.7 1.3M49.5 358.3v2.5h3.8M49.5 358.3l.8 1.3M55.9 359.6v2.5M92.7 358.3v2.5h3.8M92.7 358.3l-.8 1.3M92.7 358.3l.8 1.3M99.1 359.6v2.5M101.6 345v2.5M104 344.2h.3v.8h-.3z"/>
<path d="M104.1 345v3.8h1.3l-1.3 1.3-1.2-1.3h1.2M108.5 342.3h.7v.3h-.7zM109.2 342.4h2.6M125.7 345h8.9M128.3 343.7l2.5 1.3-2.5 1.2zM130.8 343.7v2.5M131.4 358.3v2.5M131.4 358.3l-.7 1.3M131.4 358.3l.8 1.3M132.8 343.5v-.8h-.7h.7l-1.5 1.5M134.1 343.5v-.8h-.8h.8l-1.5 1.5M134.6 344h5.1v2h-5.1z"/>
<path d="M139.7 345h6.3M141 341.2h5M141 343.1h5M158.7 345h5.1M158.7 341.2h5.1M158.7 343.1h5.1M180.3 358.3v2.5M180.3 358.3l-.7 1.3M180.3 358.3l.8 1.3M206 340.5h2v5.1h-2zM207 345.6v1.3M212.7 343.1v1.2"/>
<path d="M218.4 340.5v1.3M224.2 346.9v1.2h1.2l-1.2 1.3-1.3-1.3h1.3M247.6 343.7h5.1M265.4 343.7h5.1M301 354.5h1.3M302.3 353.5h5v2h-5zM307.3 354.5h6.4M308.6 359.6h5.1M308.6 349.4h5.1M313.7 346.9h12.7v20.3h-12.7zM326.4 354.5h5.1M326.4 359.6h6.3"/>
<path d="M331.5 346.9l-.8 1.2M331.5 346.9v2.5h-5.1M331.5 346.9l.7 1.2M332.7 358.6h5.1v2h-5.1zM337.8 343.5v4h1.3l-1.3 1.3-1.3-1.3h1.3M337.8 359.6h1.3M359 344.3h2.1v5.1h-2.1zM360 343.1v1.2M360 349.4v1.3M376 359.6l-.2 .7M376.6 358.3v1.3l-.3 .7M376.6 355.8h2.5"/>
<path d="M376.6 340.5h2.5M376.6 345.6h2.5M376.6 350.7h2.5M377.1 359.6l-.3 .7M396.9 355.8h2.5M396.9 340.5h2.5M396.9 345.6h2.5M396.9 350.7h2.5M402.6 341.8v2.8M402.6 346.6v2.8M405.1 355.8h1.3M405.1 345.6h1.3"/>
<path d="M406.4 354.8h5.1v2h-5.1zM406.4 344.6h5.1v2h-5.1zM411.5 355.8h1.2M411.5 345.6h1.2M418.5 348.9l.2-.8h2.1l-.3 .8M419.2 348.1l-.2 .8M419.7 354.5h5.1M419.7 341.8h5.1M419.7 352h5.1M419.7 344.3h5.1M419.7 349.4h5.1M420.2 348.1l-.2 .8"/>
<path d="M424.8 346.9h-5.1v1.2l-.2 .8M442.6 354.5h5.1M442.6 341.8h5.1M442.6 346.9h5.1M442.6 352h5.1M442.6 344.3h5.1M442.6 349.4h5.1M442.6 357h5.1M475.2 344.3h2.1v5.1h-2.1zM476.2 343.1v1.2M476.2 349.4v1.3M492.3 359.6l-.3 .7"/>
<path d="M492.8 358.3v1.3l-.3 .7M492.8 355.8h2.5M492.8 340.5h2.5M492.8 345.6h2.5M492.8 350.7h2.5M493.3 359.6l-.3 .7M513.1 355.8h2.5M513.1 340.5h2.5M513.1 345.6h2.5M513.1 350.7h2.5M518.8 341.8v2.8M518.8 346.6v2.8"/>
<path d="M521.3 355.8h1.3M521.3 345.6h1.3M522.6 344.6h5.1v2h-5.1zM522.6 354.8h5.1v2h-5.1zM527.7 355.8h1.3M527.7 345.6h1.3M534.7 348.9l.2-.8h2.1l-.3 .8M535.4 348.1l-.2 .8M535.9 354.5h5.1M535.9 341.8h5.1M535.9 352h5.1M535.9 344.3h5.1"/>
<path d="M535.9 349.4h5.1M536.4 348.1l-.2 .8M541 346.9h-5.1v1.2l-.2 .8M558.8 354.5h5.1M558.8 341.8h5.1M558.8 346.9h5.1M558.8 352h5.1M558.8 344.3h5.1M558.8 349.4h5.1M558.8 357h5.1M10 360.2h2M47.6 369.7h3.8"/>
<path d="M47.6 372.3h3.8M47.6 374.8h3.8M47.6 377.4h3.8M47.6 379.9h3.8M51.4 368.5h2.6v25.4h-2.6zM51.4 377.2h1.3v.3h-1.3zM51.4 374.7h1.3v.2h-1.3zM51.4 372.2h1.3v.2h-1.3zM51.4 369.6h1.3v.3h-1.3zM51.4 379.8h1.3v.2h-1.3zM55.9 360.8h3.8M59.7 369.7h3.8"/>
<path d="M59.7 372.3h3.8M59.7 374.8h3.8M59.7 377.4h3.8M59.7 379.9h3.8M62.2 360.8h2.8M63.5 368.5h5.1v25.4h-5.1zM63.5 377.2h1.3v.3h-1.3zM63.5 374.7h1.3v.2h-1.3zM63.5 372.2h1.3v.2h-1.3zM63.5 369.6h1.3v.3h-1.3zM63.5 379.8h1.3v.2h-1.3zM67.1 360.8h2.7"/>
<path d="M67.3 377.2h1.3v.3h-1.3zM67.3 374.7h1.3v.2h-1.3zM67.3 372.2h1.3v.2h-1.3zM67.3 369.6h1.3v.3h-1.3zM67.3 379.8h1.3v.2h-1.3zM68.6 369.7h3.8M68.6 372.3h3.8M68.6 374.8h3.8M68.6 377.4h3.8M68.6 379.9h3.8M90.2 369.7h3.8M90.2 372.3h3.8"/>
<path d="M90.2 374.8h3.8M90.2 377.4h3.8M90.2 379.9h3.8M94 368.5h2.5v20.3h-2.5zM94 379.8h1.2v.2h-1.2zM94 374.7h1.2v.2h-1.2zM94 372.2h1.2v.2h-1.2zM94 369.6h1.2v.3h-1.2zM94 377.2h1.2v.3h-1.2zM99.1 360.8h3.8M102.9 369.7h3.8M102.9 372.3h3.8"/>
<path d="M102.9 374.8h3.8M102.9 377.4h3.8M102.9 379.9h3.8M105.4 360.8h2.8M106.7 368.5h5.1v20.3h-5.1zM106.7 379.8h1.2v.2h-1.2zM106.7 374.7h1.2v.2h-1.2zM106.7 372.2h1.2v.2h-1.2zM106.7 369.6h1.2v.3h-1.2zM106.7 377.2h1.2v.3h-1.2zM110.2 360.8h2.8M110.5 379.8h1.3v.2h-1.3z"/>
<path d="M110.5 374.7h1.3v.2h-1.3zM110.5 372.2h1.3v.2h-1.3zM110.5 369.6h1.3v.3h-1.3zM110.5 377.2h1.3v.3h-1.3zM111.8 369.7h3.8M111.8 372.3h3.8M111.8 374.8h3.8M111.8 377.4h3.8M111.8 379.9h3.8M130.4 364.7h2.1v5h-2.1zM131.4 363.4v1.3M131.4 369.7v1.3"/>
<path d="M136.1 362.1h2.1v5.1h-2.1zM137.2 360.8v1.3M137.2 367.2v1.3M137.4 372.3h2v5.1h-2zM138.4 371v1.3M138.4 377.4v1.2M141.6 360.8v2.6h3.8M141.6 360.8l-.8 1.3M141.6 360.8l.8 1.3M143.8 369.7h2v5.1h-2zM144.8 368.5v1.2M144.8 374.8v1.3"/>
<path d="M148 363.4h6.6M148 362.1v2.6M156.6 363.4h2.8M160 363.4v1.3h1.3l-1.3 1.2-1.3-1.2h1.3M160.7 363.4h3.8M160.7 365.9h3.8M160.7 368.5h3.8M160.7 371h3.8M164.5 362.1h2.5v10.2h-2.5zM164.5 370.9h1.2v.2h-1.2zM164.5 368.3h1.2v.3h-1.2zM164.5 363.3h1.2v.2h-1.2z"/>
<path d="M164.5 365.8h1.2v.3h-1.2zM179.3 364.7h2.1v5h-2.1zM180.3 363.4v1.3M180.3 369.7v1.3M185 362.1h2.1v5.1h-2.1zM186.1 360.8v1.3M186.1 367.2v1.3M186.3 372.3h2v5.1h-2zM187.3 371v1.3M187.3 377.4v1.2M190.5 360.8v2.6h3.8M190.5 360.8l-.8 1.3"/>
<path d="M190.5 360.8l.8 1.3M192.7 369.7h2v5.1h-2zM193.7 368.5v1.2M193.7 374.8v1.3M196.8 363.4h6.7M196.8 362.1v2.6M205.5 363.4h2.8M208.9 363.4v1.3h1.3l-1.3 1.2-1.3-1.2h1.3M209.5 363.4h3.9M209.5 365.9h3.9M209.5 368.5h3.9M209.5 371h3.9"/>
<path d="M213.4 362.1h2.5v10.2h-2.5zM213.4 370.9h1.2v.2h-1.2zM213.4 368.3h1.2v.3h-1.2zM213.4 363.3h1.2v.2h-1.2zM213.4 365.8h1.2v.3h-1.2zM313.7 364.7h-5.1v1.2h1.3l-1.3 1.3-1.3-1.3h1.3M326.4 364.7h6.3M332.7 363.6h5.1v2.1h-5.1zM337.8 364.7h1.3M375.3 360.3l.2-.7h2.1l-.3 .7M474 376.2h108v32h-108zM491.5 360.3l.2-.7h2.1l-.3 .7"/>
<path d="M582 360.2h2M47.6 392.6h3.8M47.6 382.4h3.8M47.6 385h3.8M47.6 387.5h3.8M47.6 390.1h3.8M51.4 384.9h1.3v.2h-1.3zM51.4 387.4h1.3v.2h-1.3zM51.4 389.9h1.3v.3h-1.3zM51.4 392.5h1.3v.2h-1.3zM51.4 382.3h1.3v.3h-1.3zM59.7 392.6h3.8"/>
<path d="M59.7 382.4h3.8M59.7 385h3.8M59.7 387.5h3.8M59.7 390.1h3.8M63.5 384.9h1.3v.2h-1.3zM63.5 387.4h1.3v.2h-1.3zM63.5 389.9h1.3v.3h-1.3zM63.5 392.5h1.3v.2h-1.3zM63.5 382.3h1.3v.3h-1.3zM67.3 384.9h1.3v.2h-1.3zM67.3 387.4h1.3v.2h-1.3zM67.3 389.9h1.3v.3h-1.3z"/>
<path d="M67.3 392.5h1.3v.2h-1.3zM67.3 382.3h1.3v.3h-1.3zM68.6 392.6h3.8v1.3h1.3l-1.3 1.2-1.3-1.2h1.3M68.6 382.4h3.8M68.6 385h3.8M68.6 387.5h3.8M68.6 390.1h3.8M90.2 382.4h3.8M90.2 385h3.8M90.2 387.5h3.8M94 382.3h1.2v.3h-1.2zM94 384.9h1.2v.2h-1.2z"/>
<path d="M94 387.4h1.2v.2h-1.2zM102.9 382.4h3.8M102.9 385h3.8M102.9 387.5h3.8M106.7 382.3h1.2v.3h-1.2zM106.7 384.9h1.2v.2h-1.2zM106.7 387.4h1.2v.2h-1.2zM110.5 382.3h1.3v.3h-1.3zM110.5 384.9h1.3v.2h-1.3zM110.5 387.4h1.3v.2h-1.3zM111.8 387.5h3.8v1.3h1.2l-1.2 1.3-1.3-1.3h1.3M111.8 382.4h3.8"/>
<path d="M111.8 385h3.8M130.4 390.1h2.1v5h-2.1zM131.4 383.7l-.7 1.3M131.4 383.7v2.5M131.4 388.8v1.3M131.4 395.1v1.3M131.4 383.7l.8 1.3M136.1 387.5h2.1v5.1h-2.1zM137.2 386.2v1.3M137.2 392.6v1.3M137.4 397.7h2v5.1h-2zM138.4 396.4v1.3"/>
<path d="M141.6 386.2v2.6h3.8M141.6 386.2l-.8 1.3M141.6 386.2l.8 1.3M143.8 395.1h2v5.1h-2zM144.8 393.9v1.2M148 388.8h6.6M148 387.5v2.6M156.6 388.8h2.8M160 388.8v1.3h1.3l-1.3 1.2-1.3-1.2h1.3M160.7 388.8h3.8M160.7 391.3h3.8M160.7 393.9h3.8"/>
<path d="M160.7 396.4h3.8M164.5 387.5h2.5v10.2h-2.5zM164.5 396.3h1.2v.2h-1.2zM164.5 393.7h1.2v.3h-1.2zM164.5 388.7h1.2v.2h-1.2zM164.5 391.2h1.2v.3h-1.2zM179.3 390.1h2.1v5h-2.1zM180.3 383.7v2.5M180.3 388.8v1.3M180.3 395.1v1.3M180.3 383.7l-.7 1.3M180.3 383.7l.8 1.3"/>
<path d="M185 387.5h2.1v5.1h-2.1zM186.1 386.2v1.3M186.1 392.6v1.3M186.3 397.7h2v5.1h-2zM187.3 396.4v1.3M190.5 386.2v2.6h3.8M190.5 386.2l-.8 1.3M190.5 386.2l.8 1.3M192.7 395.1h2v5.1h-2zM193.7 393.9v1.2M196.8 388.8h6.7M196.8 387.5v2.6"/>
<path d="M205.5 388.8h2.8M208.9 388.8v1.3h1.3l-1.3 1.2-1.3-1.2h1.3M209.5 388.8h3.9M209.5 391.3h3.9M209.5 393.9h3.9M209.5 396.4h3.9M213.4 387.5h2.5v10.2h-2.5zM213.4 396.3h1.2v.2h-1.2zM213.4 393.7h1.2v.3h-1.2zM213.4 388.7h1.2v.2h-1.2zM213.4 391.2h1.2v.3h-1.2zM474 397.7h108"/>
<path d="M474 391.7h108M484.6 392.2l-1.3 2M489.1 395.6l-.5-.1-.3 .3 .1 .6h.7M489.7 395.6h.6v.9M489.7 395v1.5M60 408.2v2M110 408.2v2M138.4 402.8v1.2M144.8 400.2v1.3M160 408.2v2M187.3 402.8v1.2M193.7 400.2v1.3"/>
<path d="M210 408.2v2M260 408.2v2M310 408.2v2M360 408.2v2M410 408.2v2M460 408.2v2M474 404.7h108M474 401.7h108M483.1 402.6l.6-.2 .3 .5-.9 1h.9M494 401.7v3M501.7 406.7h.8M503.2 406.6v.1"/>
<path d="M504.2 405.1l-.4 1.1h.9M504.5 405.7v1M505.2 405a1.71 1.71 0 0 1 0 2.3M506.3 406.2h1.2M508.1 405.7l.4-.5v1.5M508.1 406.7h.9M510 408.2v2M536.5 409.7h.8M558 401.7v6.5M560 408.2v2M566.8 405.1l-1.2 2M567.3 405.7l.4-.5v1.5"/>
<path d="M567.3 406.7h.8"/>
<circle cx="222.1" cy="35.1" r=".51"/>
<circle cx="222.1" cy="30" r=".51"/>
<circle cx="226.2" cy="32.6" r=".51"/>
<circle cx="236" cy="32.6" r="2.82"/>
<circle cx="272.8" cy="27.5" r="2.82"/>
<circle cx="450.7" cy="28.7" r=".51"/>
<circle cx="454.8" cy="31.3" r=".51"/>
<circle cx="454.8" cy="26.2" r=".51"/>
<circle cx="467.1" cy="26.2" r="2.82"/>
<circle cx="71.8" cy="51.6" r=".89"/>
<circle cx="76.8" cy="51.6" r=".89"/>
<circle cx="450.7" cy="75.7" r=".51"/>
<circle cx="454.8" cy="78.3" r=".51"/>
<circle cx="465.8" cy="78.3" r="2.82"/>
<circle cx="478.2" cy="77.6" r=".89"/>
<circle cx="478.2" cy="72.6" r=".89"/>
<circle cx="24.6" cy="99.9" r=".51"/>
<circle cx="28.7" cy="99.9" r=".51"/>
<circle cx="450.7" cy="80.8" r=".51"/>
<circle cx="112.4" cy="289.7" r="2.82"/>
<circle cx="167" cy="285.9" r="2.82"/>
<circle cx="207.6" cy="309.5" r=".51"/>
<circle cx="207.6" cy="305.5" r=".51"/>
<circle cx="216.5" cy="309.5" r=".51"/>
<circle cx="216.5" cy="305.5" r=".51"/>
<circle cx="225.4" cy="309.5" r=".51"/>
<circle cx="225.4" cy="305.5" r=".51"/>
<circle cx="234.3" cy="305.5" r=".51"/>
<circle cx="234.3" cy="309.5" r=".51"/>
<circle cx="196.7" cy="334.2" r=".51"/>
<circle cx="196.7" cy="331.6" r=".51"/>
<circle cx="196.7" cy="336.7" r=".51"/>
<circle cx="196.7" cy="339.3" r=".51"/>
<circle cx="200.8" cy="331.6" r=".51"/>
<circle cx="200.8" cy="334.2" r=".51"/>
<circle cx="200.8" cy="336.7" r=".51"/>
<circle cx="200.8" cy="339.3" r=".51"/>
<circle cx="259.1" cy="339.9" r="2.84"/>
</g>
<g fill="none" stroke="#840000" stroke-width=".51">
<path d="M109.1 19.1v4.1M110.6 19.1v4.1M73.5 25.7h4.1M73.5 24.2h4.1M120.5 39.4h4.1M147.8 38.4h4.1M147.8 36.9h4.1M165.6 31.4h4.1M165.6 29.9h4.1M188.5 31.4h4M188.5 29.9h4M359.9 34.5a3.3 3.3 0 0 1 4.1 0"/>
<path d="M359.9 32.4h4.1M389.1 34.5a3.3 3.3 0 0 1 4.1 0M389.1 32.4h4.1M104 56.8h4.1M104 55.3h4.1M112.9 56.8h4.1M112.9 55.3h4.1M120.5 40.9h4.1M121.8 56.8h4.1M121.8 55.3h4.1M130.7 56.8h4M130.7 55.3h4"/>
<path d="M139.6 56.8h4M139.6 55.3h4M148.5 56.8h4M148.5 55.3h4M157.4 56.8h4M157.4 55.3h4M166.2 56.8h4.1M166.2 55.3h4.1M175.1 56.8h4.1M175.1 55.3h4.1M24.8 76.4v2.5M28.6 76.4v2.5"/>
<path d="M20.2 82.2h4.1M20.2 80.7h4.1M29.1 82.2h4M29.1 80.7h4M361.2 85.8v4M362.7 85.8v4M25.9 105.5v4M27.4 105.5v4M349.8 108.2h4M349.8 106.7h4M372.6 105.7h4.1M372.6 104.2h4.1"/>
<path d="M382.1 106.2a3.3 3.3 0 0 1 4.1 0M382.1 104.2h4.1M405 104.4h4.1M405 102.9h4.1M415.8 103.2h4.1M415.8 101.6h4.1M436.1 103.2h4.1M436.1 101.6h4.1M502.2 106.8a3.3 3.3 0 0 1 4 0M502.2 104.8h4M512.3 106.8a3.3 3.3 0 0 1 4.1 0M512.3 104.8h4.1"/>
<path d="M370.7 124.8h4.1M370.7 123.2h4.1M400.6 139.1h4M486.9 124.8h4.1M486.9 123.2h4.1M516.8 139.1h4M400.6 140.6h4M516.8 140.6h4M370.7 164.1h4.1M370.7 162.6h4.1M400.6 178.5h4M486.9 164.1h4.1"/>
<path d="M486.9 162.6h4.1M516.8 178.5h4M400.6 180h4M516.8 180h4M370.7 207.9h4.1M370.7 206.4h4.1M486.9 207.9h4.1M486.9 206.4h4.1M201.2 223.8h4M201.2 222.3h4M213.9 223.8h4M213.9 222.3h4"/>
<path d="M302.1 231.4h4.1M302.1 229.9h4.1M335.2 231.4h4M335.2 229.9h4M400.6 223.8h4M400.6 222.3h4M516.8 223.8h4M516.8 222.3h4M47.5 252.8v4M49 252.8v4M78.6 252.8v4M80.1 252.8v4"/>
<path d="M162.4 255.9v4.1M163.7 245.8v6.6M164 255.9v4.1M165.2 245.8v6.6M370.7 247.3h4.1M370.7 245.8h4.1M486.9 247.3h4.1M486.9 245.8h4.1M31 273.3h4.1M31 271.8h4.1M400.6 263.2h4M400.6 261.7h4"/>
<path d="M516.8 263.2h4M516.8 261.7h4M111.8 287.8v3.8M166.4 284v3.8M302.1 284.8h4.1M302.1 283.3h4.1M335.2 284.8h4M335.2 283.3h4M370.7 291.1h4.1M370.7 289.6h4.1M486.9 291.1h4.1M486.9 289.6h4.1"/>
<path d="M144.7 318.8h4M400.6 307h4M400.6 305.5h4M516.8 307h4M516.8 305.5h4M41.8 330.2v4.1M43.3 330.2v4.1M77.3 330.2v4.1M78.9 330.2v4.1M144.7 320.3h4M370.7 330.5h4.1M370.7 329h4.1"/>
<path d="M486.9 330.5h4.1M486.9 329h4.1M65.3 358.8v4.1M66.8 358.8v4.1M108.5 358.8v4.1M110 358.8v4.1M335.8 343.2h4.1M335.8 341.7h4.1M400.6 346.4h4M400.6 344.8h4M516.8 346.4h4M516.8 344.8h4"/>
<path d="M154.8 361.4v4M156.3 361.4v4M203.7 361.4v4M205.2 361.4v4M154.8 386.8v4M156.3 386.8v4M203.7 386.8v4M205.2 386.8v4"/>
</g>
<g fill="#ffffc2" stroke="#ffffc2" stroke-width=".26">
<path d="M495.3 215.4h17.8v20.4h-17.8z"/>
<path d="M495.3 254.8h17.8v20.3h-17.8z"/>
<path d="M495.3 132.2h17.8v20.4h-17.8z"/>
<path d="M495.3 171.6h17.8v20.3h-17.8z"/>
<path d="M436.9 56h2.5v5.1h-2.5z"/>
<path d="M495.3 298.6h17.8v20.3h-17.8z"/>
<path d="M495.3 338h17.8v20.3h-17.8z"/>
<path d="M51.4 331h2.6v10.2h-2.6z"/>
<path d="M99.1 329.7h10.1v15.3h-10.1z"/>
<path d="M87 331h2.5v10.2h-2.5z"/>
<path d="M146 332.3h12.7v13.9h-12.7z"/>
<path d="M379.1 254.8h17.8v20.3h-17.8z"/>
<path d="M379.1 298.6h17.8v20.3h-17.8z"/>
<path d="M379.1 338h17.8v20.3h-17.8z"/>
<path d="M379.1 215.4h17.8v20.4h-17.8z"/>
<path d="M51.4 368.5h2.6v25.4h-2.6z"/>
<path d="M63.5 368.5h5.1v25.4h-5.1z"/>
<path d="M61 74.5h238.7v137.1h-238.7z"/>
<path d="M94 368.5h2.5v20.3h-2.5z"/>
<path d="M106.7 368.5h5.1v20.3h-5.1z"/>
<path d="M213.4 362.1h2.5v10.2h-2.5z"/>
<path d="M213.4 387.5h2.5v10.2h-2.5z"/>
<path d="M88.3 253.5h2.5v10.2h-2.5z"/>
<path d="M194.9 329.1h7.7v12.7h-7.7z"/>
<path d="M57.1 47.8h2.6v12.7h-2.6z"/>
<path d="M164.5 362.1h2.5v10.2h-2.5z"/>
<path d="M164.5 387.5h2.5v10.2h-2.5z"/>
<path d="M40 280.8h20.3v15.3h-20.3z"/>
<path d="M57.1 253.5h2.6v10.2h-2.6z"/>
<path d="M311.8 20.5h2.5v5.1h-2.5z"/>
<path d="M172.7 22.4h12.7v8.9h-12.7z"/>
<path d="M522.6 33.2h2.5v5.1h-2.5z"/>
<path d="M522.6 21.8h2.5v5h-2.5z"/>
<path d="M379.1 132.2h17.8v20.4h-17.8z"/>
<path d="M499.7 78.9h2.6v5.1h-2.6z"/>
<path d="M499.7 67.5h2.6v5.1h-2.6z"/>
<path d="M499.7 56h2.6v5.1h-2.6z"/>
<path d="M499.7 44.6h2.6v5.1h-2.6z"/>
<path d="M499.7 33.2h2.6v5.1h-2.6z"/>
<path d="M499.7 21.8h2.6v5h-2.6z"/>
<path d="M379.1 171.6h17.8v20.3h-17.8z"/>
</g>
<g fill="#840000" stroke="#840000" stroke-width=".26">
<path d="M522.6 211l2.5-1.3v2.6z"/>
<path d="M522.6 250.4l2.5-1.3v2.5z"/>
<path d="M522.6 127.8l2.5-1.3v2.6z"/>
<path d="M522.6 167.2l2.5-1.3v2.5z"/>
<path d="M53.3 359.6l2.6 1.2-2.6 1.3z"/>
<path d="M522.6 294.2l2.5-1.3v2.5z"/>
<path d="M522.6 333.5l2.5-1.2v2.5z"/>
<path d="M411.5 97.3l2.5 1.3-2.5 1.3z"/>
<path d="M393.7 102.4l1.3 2.5h-2.6z"/>
<path d="M103.6 336.1h.8v.7h-.8z"/>
<path d="M104.8 334.6l1.2 .6-1.2 .6z"/>
<path d="M99.8 331.8h2.6l-.3 .7h-2z"/>
<path d="M32.4 331l2.5 1.3-2.5 1.2z"/>
<path d="M67.9 331l2.6 1.3-2.6 1.2z"/>
<path d="M115.6 331l2.5 1.3-2.5 1.2z"/>
<path d="M406.4 250.4l2.5-1.3v2.5z"/>
<path d="M406.4 294.2l2.5-1.3v2.5z"/>
<path d="M406.4 333.5l2.5-1.2v2.5z"/>
<path d="M406.4 211l2.5-1.3v2.6z"/>
<path d="M563.1 24.4l1.7-.7a1.45 1.45 0 0 0 1.3-.7l.3-.1a.73 .73 0 0 1 1.2-.2 1.67 1.67 0 0 1 1.5 1.5l.2 .7a.73 .73 0 0 1-.1 1.2 5.7 5.7 0 0 0-1.3 4.4 .71 .71 0 0 1 .2 1.1 1.16 1.16 0 0 0 .4 1.8 1.19 1.19 0 0 1-.1 1.6l-.1 .4a2.11 2.11 0 0 0-.1 2.1l-.3 .7v1a4.7 4.7 0 0 1-.8 4.3l-.3 1.6-.4-1 .1-1.2a2.97 2.97 0 0 1 .3-2.7 1.94 1.94 0 0 1 .2-1.9l.1-2.3-.2-1.5a2.37 2.37 0 0 1-.1-2.1v-.2a1.96 1.96 0 0 1-.6-2.4v-.2a.49 .49 0 0 1-.4-.5 .49 .49 0 0 1 .4-.5l.2-.2v-1.9a.83 .83 0 0 0-.3-1.2l-.8-.4h-1.1l-.9-.3z"/>
<path d="M548.3 24l2.5-.8a4.3 4.3 0 0 0 2.5-.6 2.42 2.42 0 0 0 2 .5 .78 .78 0 0 0 1.2-.1l4.2-1.4 1.3 1a.67 .67 0 0 1 .7 .8l.4 .1-.5 .6a3 3 0 0 0-.8 3.3l.2 1.8 .2 .2-.2 .7a3.6 3.6 0 0 0 .3 3.4 1.25 1.25 0 0 1-.8 1.5l-.7 1.7 .1 2.4-.3 2.9 .1 1.2 .4 .5a1.45 1.45 0 0 1-.4 1.5l-.1 2-.3 .8-.5 .4-.1-.7 .2-.4a1.44 1.44 0 0 0-.3-1.8l-.3-1.1 .1-3.3-.3-.7 .1-.8-.3-.5a7.4 7.4 0 0 1 .9-4.1l-.1-1.2a6.9 6.9 0 0 1-.2-3.3 1.07 1.07 0 0 1-.3-1.2l-.1-1.5a1.04 1.04 0 0 0-.4-1.5v-.4a1.56 1.56 0 0 0 0-1.5l-.3-.1-.3-.5-1.2-.1a.78 .78 0 0 0-1 .3l-.1 1.5-1 .3 .1 2.2a2.1 2.1 0 0 0-.3 2.5l.9 2.5-.3 .8v1.3a1.78 1.78 0 0 1 0 2.4 6.1 6.1 0 0 0-.2 3.4l-.2 2.4 .1 2.2-.5-.7-.5-2.8a3.6 3.6 0 0 1-.5-2.7 1.07 1.07 0 0 1-.1-1.7l.1-.1a3.5 3.5 0 0 0-.2-2.8v-1.7l-.5-1.6a2.21 2.21 0 0 1-.3-2.7l.3-1.1a2.08 2.08 0 0 0-.9-1.9v-.6a.73 .73 0 0 0-.7-.8z"/>
<path d="M454.7 67.5l2.5-1.3v2.5z"/>
<path d="M466.7 25.8l1 .4-1 .4z"/>
<path d="M194.3 362.1l2.5 1.3-2.5 1.3z"/>
<path d="M194.3 387.5l2.5 1.3-2.5 1.3z"/>
<path d="M96.5 359.6l2.6 1.2-2.6 1.3z"/>
<path d="M85.7 50.3l2.6 1.3-2.6 1.3z"/>
<path d="M112.9 291l.5 1-1-.5z"/>
<path d="M145.4 362.1l2.6 1.3-2.6 1.3z"/>
<path d="M145.4 387.5l2.6 1.3-2.6 1.3z"/>
<path d="M167 287.7l.5-.5 .5 1z"/>
<path d="M126.4 36.4l2.5-1.3v2.5z"/>
<path d="M137.2 36.4l1.2 2.5h-2.5z"/>
<path d="M153.7 30l2.5 1.3-2.5 1.3z"/>
<path d="M267.3 21.1l2.6 1.3-2.6 1.3z"/>
<path d="M267.3 31.3l2.6 1.3-2.6 1.2z"/>
<path d="M272.2 27.5l1-.4v.8z"/>
<path d="M235.3 32.6l1-.4v.7z"/>
<path d="M465.2 78.3l1-.4v.8z"/>
<path d="M406.4 127.8l2.5-1.3v2.6z"/>
<path d="M194.3 23.7l2.5 1.2-2.5 1.3z"/>
<path d="M355.6 29.4l2.5-1.3v2.5z"/>
<path d="M406.4 167.2l2.5-1.3v2.5z"/>
<path d="M106 274.5l2.6-1.3v2.6z"/>
<circle cx="100.3" cy="335.2" r=".63"/>
<circle cx="103.5" cy="333.9" r=".38"/>
<circle cx="468" cy="24.4" r=".28"/>
<circle cx="468" cy="28" r=".28"/>
<circle cx="443.2" cy="21.1" r=".25"/>
<circle cx="273.7" cy="25.7" r=".28"/>
<circle cx="273.7" cy="29.3" r=".28"/>
<circle cx="236.9" cy="30.8" r=".28"/>
<circle cx="236.9" cy="34.3" r=".28"/>
<circle cx="466.7" cy="80.1" r=".28"/>
<circle cx="466.7" cy="76.5" r=".28"/>
</g>
<g fill="none" stroke="#008484" stroke-width=".26">
<path d="M368.6 16.5a.68 .68 0 0 0-1 .6 .68 .68 0 0 0 1 .7M383.3 16.5l.5-.1 .3 .4-.9 1.1h.9M216.3 27.1a.56 .56 0 0 0-.8 .5 .56 .56 0 0 0 .8 .5M231.7 27l.3 1.2 .3-.9 .2 .9 .3-1.2M373.2 21.5h.5M373.2 29.1h.5M373.4 21v1.1l.3 .2M373.4 28.7v1.1l.3 .1M379.6 25.6h1M447.8 46.9l.5 1.5 .5-1.5M464.3 47.3l.4-.4v1.5M464.3 48.4h.9"/>
<path d="M253.2 78.2l.7-.1v-.4l-.7-.1v1.2M254.5 78.2h.4M255.1 77.6h-.6v1.2h.6M255.7 77.7l.2-.1a.62 .62 0 0 1 .4 .6 .62 .62 0 0 1-.6 .6l-.2-.4zM82.5 87.7v1.1l.3 .2 .5-.2v-1.1M83.7 87.7h.7M84 87.7v1.3M242.6 93.5l.6-.1 .1-.5-.7-.1v1.3M243.9 93.4h.4M244.5 92.8h-.6v1.3h.6M244.6 90.9h.6v-.5l-.6-.1v1.2M245.6 92.8l-.6 .3v.7l.2 .3 .4-.2 .1-.4-.2-.2-.5 .2"/>
<path d="M245.8 90.9h.5M246.4 90.3h-.6v1.2h.6M247.1 92.8l-1.1 1.6M247.6 90.3h-.6l-.1 .6 .6-.1 .1 .6h-.7M249.1 90.2l-1.1 1.6M249.1 83.3h.7v-.5l-.7-.2v1.3M250.4 83.3h.5M251 82.6h-.6v1.3h.6M251.5 82.8l.5-.2 .2 .4-.8 .9h.8M254.9 88.4l.6-.1v-.4l-.6-.2v1.3M256.2 88.3h.4M256.8 87.7h-.6v1.3h.6"/>
<path d="M257.6 87.7l-.3 .9h.7M257.9 88.2v.8M263.1 80.8l.6-.1 .1-.5-.7-.1v1.3M263.2 98.5h.6v-.5l-.6-.1v1.3M264.3 85.8h.6v-.5l-.6-.1v1.3M264.4 80.7h.4M264.4 98.5h.5M264.9 96l.7-.1v-.4l-.7-.2v1.3M265 80.1h-.6v1.3h.6M265 97.9h-.6v1.3h.6M265.5 85.8h.5M265.8 98.4l-.3-.3 .5-.2 .3 .2-.1 .2-.7 .4 .3 .5 .5-.3-.3-.5"/>
<path d="M266.1 85.2h-.6v1.3h.6M266.2 96h.4M266.8 95.3h-.6v1.3h.6M85.4 103h.7M85.8 103v1.2M261.4 116.3h.6l.1-.5-.7-.1v1.2M262 103.6l.6-.1v-.4l-.6-.1v1.2M262 108.7l.6-.1v-.4l-.6-.2v1.3M262.1 111.2l.7-.1v-.4l-.7-.1v1.3M262.1 113.8l.7-.1v-.4l-.7-.2v1.3M262.7 116.3h.4M263.2 103.6h.5"/>
<path d="M263.2 108.7h.5M263.3 106.2l.6-.1 .1-.5-.7-.1v1.3M263.3 115.7h-.6v1.2h.6M263.3 111.2h.5M263.3 113.7h.5M263.8 116l.3-.3v1.2M263.8 116.9h.7M263.8 103h-.6v1.2h.6M263.8 108h-.6v1.3h.6M264 110.6h-.7v1.3h.7M264 113.1h-.7v1.3h.7M264.3 103.3l.4-.3v1.2"/>
<path d="M264.3 108.4l.4-.4v1.3M264.3 104.2h.7M264.3 109.3h.7M264.4 110.9l.4-.3v1.3M264.4 113.5l.4-.4v1.3M264.4 111.9h.8M264.4 114.4h.8M264.5 101.1l.7-.1v-.4l-.7-.2v1.3M264.6 106.1h.4M265.2 105.5h-.6v1.3h.6M265.7 105.9l.3-.4v1.3M265.7 106.8h.7"/>
<path d="M265.8 101h.4M266.4 100.4h-.6v1.3h.6M267.6 101l-.2 .2h-.4l-.1-.6 .5-.2 .2 .3-.1 .7-.1 .2-.4 .1M124.3 128.4v1.2l-.7-1.2v1.2M124.6 136v1.3l-.7-1.3v1.3M124.8 128.4h.7M125 136h.7M125.1 128.4v1.2M125.3 136v1.3M125.9 128.5l.2-.1 .5 .1 .1 .7-.2 .4-.6-.1zM126.1 136.2l.3-.2 .5 .2v.6l-.2 .4-.6-.1zM127.2 128.4v1l.3 .2 .5-.2v-1"/>
<path d="M127.5 136v1l.2 .3 .5-.3v-1M128.4 128.4h.7M128.6 136h.8M128.8 128.4v1.2M129 136v1.3M136.9 138.5l.4 1.3 .4-1.3M137.4 134.1h.4M138 133.4h-.6v1.3h.6M138.1 139.1h.4M138.7 138.5h-.6v1.3h.6M139.3 133.4v1.3l-.8-1.3v1.3M139.7 133.4h.7"/>
<path d="M140 138.5v1.3l-.7-1.3v1.3M140.1 133.4v1.3M140.4 138.5h.7M140.8 138.5v1.3M140.8 133.6l.3-.2 .5 .2v.7l-.1 .4-.7-.2zM141.6 138.7l.2-.2 .5 .2v.7l-.1 .3-.6-.1zM142.2 133.4v1.1l.2 .2 .5-.2v-1.1M142.4 131.5h.4M142.9 138.5v1.1l.2 .2 .5-.2v-1.1M143 130.9h-.6v1.3h.6M143.3 133.4h.7M143.7 133.4v1.3"/>
<path d="M144 138.5h.8M144.3 130.9v1.3l-.7-1.3v1.3M144.4 138.5v1.3M144.7 130.9h.7M145.1 130.9v1.3M145.9 131.1l.2-.2 .5 .2v.9l-.2 .2-.5-.2zM147.2 130.9v1l.2 .3 .5-.3v-1M148.3 123.9h.5M148.3 130.9h.8M148.7 130.9v1.3M148.9 123.3h-.6v1.3h.6M150.2 126.4h.4"/>
<path d="M150.2 123.3v1.3l-.7-1.3v1.3M150.6 123.3h.8M150.7 125.8h-.5v1.3h.5M151 123.3v1.3M151.8 123.5l.2-.2 .5 .2 .1 .6-.2 .4-.6-.1zM152 125.8v1.3l-.7-1.3v1.3M152.5 125.8h.7M152.8 125.8v1.3M153.1 123.3v1l.3 .3 .4-.3v-1M153.6 126l.2-.2 .5 .2 .1 .7-.2 .3-.6-.1zM154.3 123.3h.7M154.6 123.3v1.3"/>
<path d="M154.9 125.8v1.1l.3 .2 .5-.2v-1.1M156.1 125.8h.7M156.4 125.8v1.3M242.7 129h.6v-.5l-.6-.1v1.2M243.9 128.4a.64 .64 0 0 1 .8 .6 .64 .64 0 0 1-.8 .6zM245.2 128.5l.4-.1 .3 .3-.8 .9h.8M247.3 128.3l-1 1.6M259.9 139.2l.6-.1 .1-.4-.7-.2v1.3M260.6 134.1h.6v-.5l-.6-.2v1.3M260.8 131.6l.7-.1v-.5l-.7-.1v1.3M261.2 138.5a.64 .64 0 0 1 .7 .7 .64 .64 0 0 1-.7 .6zM261.7 136.6h.6l.1-.5-.7-.1v1.3"/>
<path d="M261.8 133.4a.64 .64 0 0 1 .8 .7 .64 .64 0 0 1-.8 .6zM262.1 130.9a.64 .64 0 0 1 .7 .6 .64 .64 0 0 1-.7 .7zM263 136a.64 .64 0 0 1 .7 .6 .64 .64 0 0 1-.7 .7zM265 123.9h.7v-.5l-.7-.1v1.3M265.4 126.5l.6-.1v-.4l-.6-.2v1.3M266.3 123.3a.64 .64 0 0 1 .8 .6 .64 .64 0 0 1-.8 .7zM266.6 125.8a.64 .64 0 0 1 .8 .7 .64 .64 0 0 1-.8 .6zM88.6 156.3v1l.2 .3 .5-.3v-1M88.8 158.8v1.1l.3 .2 .5-.2v-1.1M89.7 156.3h.8M90 158.8h.7M90.1 156.3v1.3"/>
<path d="M90.3 158.8v1.3M114.7 146.1h.7M115 146.1v1.3M115.6 148.7h.7M115.8 146.3l.3-.2 .4 .2 .1 .7-.2 .4-.6-.2zM115.9 148.7v1.3M116.7 148.9l.2-.2 .5 .2 .1 .6-.2 .4-.6-.1zM117.1 146.1v1.1l.3 .2 .5-.2v-1.1M117.9 153.9l.3-.1 .4 .1v1l-.2 .1-.5-.1zM118 148.7v1l.3 .3 .5-.3v-1M118.3 146.1h.7M118.6 146.1v1.3"/>
<path d="M118.6 151.2h.8M119 151.2v1.3M119.2 148.7h.7M119.3 153.8v1l.2 .2 .5-.2v-1M119.6 148.7v1.3M119.8 151.4l.2-.2 .5 .2 .1 .7-.2 .3-.6-.1zM120.4 153.8h.7M120.8 153.8v1.2M121.1 151.2v1.1l.3 .2 .4-.2v-1.1M122.3 151.2h.7M122.6 151.2v1.3M123.1 143.6v1.3l-.8-1.3v1.3"/>
<path d="M123.5 143.6h.7M123.9 143.6v1.3M124.6 143.8l.3-.2 .4 .2 .1 .6-.2 .4-.6-.1zM126 143.6v1l.2 .3 .5-.3v-1M127.1 143.6h.7M127.5 143.6v1.3M152.1 141.7h.5M152.8 141.1h-.7v1.2h.7M153.1 141.1l.4 1.2 .5-1.2M154.4 141.7h.4M155 141.1h-.6v1.2h.6M156.3 141.1v1.2l-.8-1.2v1.2"/>
<path d="M156.7 141.1h.7M157 141.1v1.2M157.8 141.2l.3-.1 .5 .1v.7l-.2 .4-.6-.1zM159.2 141.1v1l.2 .2 .5-.2v-1M160.3 141.1h.7M160.7 141.1v1.2M238.7 154.4l.7-.1v-.4l-.7-.1v1.2M240 153.8a.64 .64 0 0 1 .7 .6 .64 .64 0 0 1-.7 .6zM241.2 154.1l.4-.3v1.2M241.2 155h.8M242.4 153.9l.5-.1 .3 .3-.8 .9h.8M248.9 151.9l.7-.1v-.4l-.7-.2v1.3"/>
<path d="M249.3 141.7h.6l.1-.5-.7-.1v1.2M250.2 151.2a.64 .64 0 0 1 .7 .7 .64 .64 0 0 1-.7 .6zM250.6 141.1a.64 .64 0 0 1 .7 .6 .64 .64 0 0 1-.7 .6zM251.4 151.6l.3-.4v1.3M251.4 152.5h.7M251.6 159.5h.6v-.5l-.6-.2v1.3M251.7 141.1h.9l-.6 1.2M252.8 158.8a.64 .64 0 0 1 .8 .7 .64 .64 0 0 1-.8 .6zM254.1 159.2l.3-.4v1.3M260.4 149.3h.6l.1-.5-.7-.1v1.3M261.7 146.8h.6v-.5l-.6-.2v1.3M261.7 148.7a.64 .64 0 0 1 .7 .6 .64 .64 0 0 1-.7 .7z"/>
<path d="M262 144.3l.6-.1v-.5l-.6-.1v1.3M262.2 157l.6-.1v-.5l-.6-.1v1.3M262.9 146.1a.64 .64 0 0 1 .8 .7 .64 .64 0 0 1-.8 .6zM263.2 143.6a.64 .64 0 0 1 .8 .6 .64 .64 0 0 1-.8 .7zM263.4 156.3a.64 .64 0 0 1 .7 .6 .64 .64 0 0 1-.7 .7zM264.6 156.7l.4-.4v1.3M264.6 157.6h.8M81.9 174.1v1l.2 .3 .5-.3v-1M83 174.1h.7M83.4 174.1v1.3M120.4 162h.4M121 161.4h-.6v1.3h.6"/>
<path d="M122.3 161.4v1.3l-.8-1.3v1.3M122.3 179.8h.4M122.7 161.4h.7M122.9 179.2h-.6v1.2h.6M123.1 161.4v1.3M123.9 161.6l.2-.2 .5 .2v.6l-.1 .4-.6-.1zM124.2 179.2v1.2l-.8-1.2v1.2M124.6 179.2h.7M124.9 179.2v1.2M125.2 161.4v1l.2 .3 .5-.3v-1M125.8 179.2h.4l.2 .1 .1 .7-.3 .4-.5-.1v-.7zM126.3 161.4h.8"/>
<path d="M126.7 161.4v1.3M126.7 177.2h.4M127.1 179.2v1l.2 .2 .5-.2v-1M127.3 176.6h-.6v1.3h.6M128.2 179.2h.7M128.6 176.6v1.3l-.8-1.3v1.3M128.6 179.2v1.2M129 176.6h.7M129.4 176.6v1.3M130.1 176.8l.3-.2 .5 .2v.7l-.2 .3-.6-.1zM131.5 176.6v1.1l.2 .2 .5-.2v-1.1M132.6 176.6h.7"/>
<path d="M133 176.6v1.3M134.7 169.6h.5M135.3 169h-.6v1.3h.6M136.6 169v1.3l-.7-1.3v1.3M137 169h.7M137.4 169v1.3M138.2 169.2l.2-.2 .5 .2 .1 .6-.2 .4-.6-.1zM139.5 169v1l.3 .3 .4-.3v-1M140.7 169h.7M141 169v1.3M147.1 171.5l.4 1.3 .4-1.3M148.3 172.2h.5"/>
<path d="M148.9 171.5h-.6v1.3h.6M150.2 171.5v1.3l-.7-1.3v1.3M150.6 171.5h.8M151 171.5v1.3M151.8 171.7l.2-.2 .5 .2 .1 .7-.2 .4-.6-.2zM153.1 171.5v1.1l.3 .2 .4-.2v-1.1M154.3 171.5h.7M154.6 171.5v1.3M229.7 174.7l.7-.1v-.4l-.7-.1v1.3M230.1 177.3l.7-.1v-.4l-.7-.2v1.3M231.7 174.2a.56 .56 0 0 0-.8 .5 .56 .56 0 0 0 .8 .5M232.2 176.8a.56 .56 0 0 0-.8 .5 .56 .56 0 0 0 .8 .5"/>
<path d="M232.2 174.2l.5-.1 .2 .3-.7 1h.7M232.6 176.6h.7l-.4 .5 .4 .1-.1 .6h-.6M234.4 174l-1.1 1.7M234.8 176.6l-1.1 1.6M235.5 174.2h-.6l-.1 .4a.5 .5 0 0 1 .5 .2 .5 .5 0 0 1 .1 .5h-.7M252.7 179.8h.6v-.5l-.6-.1v1.2M254.1 160.1h.7M254.7 179.3a.56 .56 0 0 0-.8 .5 .56 .56 0 0 0 .8 .5M263.2 162h.6v-.5l-.6-.1v1.3M264.4 161.4a.64 .64 0 0 1 .8 .6 .64 .64 0 0 1-.8 .7zM265.7 161.7l.3-.3v1.3M265.7 162.7h.7"/>
<path d="M266.5 169.7l.6-.1 .1-.5-.7-.1v1.3M273.8 172.2l.7-.1v-.4l-.7-.2v1.3M122.3 184.2v1.3l-.8-1.3v1.3M122.7 184.2h.7M123.1 184.2v1.3M123.9 184.4l.2-.2 .5 .2v.7l-.1 .4-.6-.2zM125.2 184.2v1.1l.2 .2 .5-.2v-1.1M126.3 184.2h.8M126.4 186.8v1.3l-.7-1.3v1.3M126.7 184.2v1.3M126.9 186.8h.7M127.2 186.8v1.3"/>
<path d="M128 187l.3-.2 .5 .2v.6l-.2 .4-.6-.1zM129.4 186.8v1l.2 .3 .5-.3v-1M130.5 186.8h.7M130.9 186.8v1.3M141.7 189.9h.4M142.3 189.3h-.6v1.3h.6M142.6 189.3l.5 1.3 .4-1.3M143.9 189.9h.4M144.5 189.3h-.6v1.3h.6M145.8 189.3v1.3l-.7-1.3v1.3M146.2 189.3h.7M146.5 191.8l-1.1 1.6"/>
<path d="M146.6 189.3v1.3M146.9 192.5h.5M147.4 189.5l.2-.2 .5 .2 .1 .7-.2 .3-.6-.1zM147.5 191.9h-.6v1.2h.6M147.9 191.9l.4 1.2 .5-1.2M148.7 189.3v1.1l.2 .2 .5-.2v-1.1M149.2 192.5h.4M149.8 191.9h-.6v1.2h.6M149.9 189.3h.7M150.2 189.3v1.3M151.1 191.9v1.2l-.8-1.2v1.2M151.5 191.9h.7"/>
<path d="M151.5 197.6h.5M151.8 191.9v1.2M152.1 196.9h-.6v1.3h.6M152.3 195h.5M152.6 192l.3-.1 .5 .1v.7l-.2 .4-.6-.1zM152.9 194.4h-.6v1.3h.6M153.3 194.4l.4 1.3 .5-1.3M153.4 196.9v1.3l-.7-1.3v1.3M153.8 196.9h.8M154 191.9v1l.2 .2 .5-.2v-1M154.2 196.9v1.3M154.6 195h.4"/>
<path d="M155 197.1l.2-.2 .5 .2 .1 .7-.2 .4-.6-.2zM155.1 191.9h.7M155.2 194.4h-.6v1.3h.6M155.5 191.9v1.2M156.3 196.9v1.1l.3 .2 .4-.2v-1.1M156.4 194.4v1.3l-.7-1.3v1.3M156.9 194.4h.7M157.2 194.4v1.3M157.5 196.9h.7M157.8 196.9v1.3M158 194.6l.3-.2 .4 .2 .1 .6-.2 .4-.6-.1zM159.3 194.4v1l.3 .3 .5-.3v-1"/>
<path d="M160.5 194.4h.7M160.9 194.4v1.3M169.6 181.7a.64 .64 0 0 1 .7 .6 .64 .64 0 0 1-.7 .7zM171.8 181.7l-1.1 1.6M172.2 182.3h.4M172.8 181.7h-.6v1.3h.6M173.1 181.7l.5 1.3 .4-1.3M174.4 182.3h.4M175 181.7h-.6v1.3h.6M176.3 181.7v1.3l-.7-1.3v1.3M176.7 181.7h.7M177.1 181.7v1.3"/>
<path d="M177.9 181.9l.2-.2 .5 .2v.6l-.1 .4-.6-.1zM179.2 181.7v1l.2 .3 .5-.3v-1M180.3 181.7h.8M180.7 181.7v1.3M187.4 199.5a.64 .64 0 0 1 .7 .6 .64 .64 0 0 1-.7 .7zM189.6 199.4l-1.1 1.7M190.6 199.5h-.6v1.3h.6M191 199.5l.4 1.3 .4-1.3M192.9 199.5h-.6v1.3h.6M194.1 199.5v1.3l-.7-1.3v1.3M194.5 199.5h.8M194.9 199.5v1.3"/>
<path d="M195.7 199.7l.2-.2 .5 .2 .1 .6-.2 .4-.6-.1zM197 199.5v1l.3 .3 .4-.3v-1M198.2 199.5h.7M198.5 199.5v1.3M218.7 192.5h.6l.1-.5-.7-.1v1.2M219.2 197.6l.7-.1v-.4l-.7-.2v1.3M220.7 192a.56 .56 0 0 0-.8 .5 .56 .56 0 0 0 .8 .5M221.2 197.1a.56 .56 0 0 0-.8 .5 .56 .56 0 0 0 .8 .5M221.7 197.3l.3-.4v1.3M221.7 198.2h.7M221.9 192.4l-.2 .3-.4-.1v-.6l.4-.1 .2 .2v.7l-.2 .3h-.4M222.9 187.4l.7-.1v-.4l-.7-.1v1.3"/>
<path d="M222.9 197.3l.4-.4v1.3M222.9 198.2h.7M223.2 184.9l.7-.1v-.4l-.7-.2v1.3M223.4 191.8l-1.1 1.6M223.4 195.1l.7-.1v-.5l-.7-.1v1.3M223.8 191.9v1.2M224.2 199.6a.56 .56 0 0 0-.8 .5 .56 .56 0 0 0 .8 .5M224.4 192l.4-.1 .3 .3-.8 .9h.8M224.7 199.8l.4-.3v1.3M224.9 186.9a.56 .56 0 0 0-.8 .5 .56 .56 0 0 0 .8 .5M225.1 196.9l-1.1 1.6M225.2 184.4a.56 .56 0 0 0-.8 .5 .56 .56 0 0 0 .8 .5"/>
<path d="M225.3 186.8h.9l-.6 1.3M225.5 194.5a.56 .56 0 0 0-.8 .5 .56 .56 0 0 0 .8 .5M225.5 196.9v1.1l.2 .2 .5-.2v-1.1M225.9 194.8l.4-.4v1.3M225.9 199.6l.5-.1 .2 .3-.7 1h.7M225.9 195.7h.7M226.3 184.2l-.4 .2-.2 .4v.6l.6 .1v-.7l-.4-.1-.2 .3M226.3 191.9h-.6l-.1 .4a.5 .5 0 0 1 .5 .2 .5 .5 0 0 1 .1 .6h-.6M226.5 193.3h1M227.3 194.5l.1-.1a.62 .62 0 0 1 .5 .7 .62 .62 0 0 1-.6 .5l-.2-.4zM227.6 186.7l-1.1 1.7M227.9 184.2l-1.1 1.6"/>
<path d="M228 186.8v1.3M228.1 199.4l-1.1 1.7M228.3 184.2v1.3M228.5 186.9l.5-.1 .3 .3-.8 1h.8M228.5 199.5v1l.3 .3 .5-.3v-1M228.8 184.4l.5-.2 .2 .4-.7 .9h.7M229.3 194.4l-1.1 1.6M230.4 194.5h-.6l-.1 .4a.5 .5 0 0 1 .5 .2 .5 .5 0 0 1 .1 .5h-.6M230.5 186.9h-.7v.4a.5 .5 0 0 1 .5 .2 .5 .5 0 0 1 0 .5h-.6M230.8 184.3h-.7v.4a.5 .5 0 0 1 .5 .2 .5 .5 0 0 1 0 .6h-.6M233.3 190l.7-.1v-.4l-.7-.2v1.3M235.4 189.5a.56 .56 0 0 0-.8 .5 .56 .56 0 0 0 .8 .5"/>
<path d="M236.1 189.9l-.2-.1v-.3l.4-.2 .3 .3-.1 .2-.7 .3 .3 .5 .5-.2-.3-.5M238 189.3l-1.1 1.6M238.3 189.3h.7M238.6 189.3v1.3M252.7 182.4l.6-.1v-.5l-.6-.1v1.3M254.7 181.8a.56 .56 0 0 0-.8 .5 .56 .56 0 0 0 .8 .5M136.6 207.1l.4 1.3 .5-1.3M137.9 207.7h.4M138.5 207.1h-.6v1.3h.6M139.8 207.1v1.3l-.8-1.3v1.3M140.2 207.1h.7M140.5 207.1v1.3"/>
<path d="M141.3 207.3l.3-.2 .5 .2v.6l-.2 .4-.6-.1zM142.6 207.1v1l.3 .3 .5-.3v-1M143.8 207.1h.7M144.2 207.1v1.3M151.1 204.5l-1.1 1.6M151.5 205.2h.4M152.1 204.6h-.6v1.2h.6M152.5 204.6l.4 1.2 .4-1.2M153.7 205.2h.5M154.3 204.6h-.6v1.2h.6M155.6 204.6v1.2l-.7-1.2v1.2M156 204.6h.7"/>
<path d="M156.4 204.6v1.2M157.2 204.7l.2-.1 .5 .1 .1 .7-.2 .4-.6-.1zM158.5 204.6v1l.2 .2 .5-.2v-1M159.6 204.6h.8M160 204.6v1.2M167.9 202l-1.1 1.6M168.3 202.6h.4M168.9 202h-.6v1.3h.6M169.3 202l.4 1.3 .4-1.3M170.5 202.6h.5M171.1 202h-.6v1.3h.6M172.4 202v1.3l-.7-1.3v1.3"/>
<path d="M172.8 202h.8M173.2 202v1.3M174 202.2l.2-.2 .5 .2 .1 .7-.3 .4-.5-.2zM175.3 202v1.1l.3 .2 .4-.2v-1.1M176.5 202h.7M176.8 202v1.3M190 200.1h.4M192.3 200.1h.4M222.2 200.1l.7-.1v-.4l-.7-.1v1.3M224.7 200.8h.8M271.2 207.8l.6-.1v-.5l-.6-.1v1.3M272.8 205.2h.7v-.5l-.7-.1v1.2"/>
<path d="M273.2 207.2a.56 .56 0 0 0-.8 .5 .56 .56 0 0 0 .8 .5M274.9 204.7a.56 .56 0 0 0-.8 .5 .56 .56 0 0 0 .8 .5M283.3 202.7l.6-.1 .1-.4-.7-.2v1.3M181.3 273.3l.6-.1-.1-.2-.3-.1-.2 .2v.6h.5M100.9 338.3h1.3M101.4 338.3l-.1 .4 .2 .2 .6-.1v-.5M105.6 339.2a.64 .64 0 0 1 .7 .6 .64 .64 0 0 1-.7 .7zM106.9 340h.9M155.1 336.6a.64 .64 0 0 1 .7 .7 .64 .64 0 0 1-.7 .6zM156.4 337.4h1"/>
</g>
<path d="M155.5 227.1l.7-.1 .1-.5-.8-.2v1.6M157 226.9h.6l.1 1M157.7 227.2l-.7 .3 .2 .4 .5-.1M201.8 227l.6-.1 .1 1M202.5 227l.2-.2 .3 .1 .1 1M203.8 227l.6-.1 .1 1M203.8 226.8v1.1M204.5 227l.2-.2 .4 .1 .1 1" fill="none" stroke="#840084" stroke-width=".26"/>
<path d="M25.5 75.1h2.3v5.1h-2.3z" fill="none" stroke="#840000" stroke-width=".3"/>
<g fill="none" stroke="#008400" stroke-width=".26">
<path d="M411.5 19.9h-3.8v20.3h3.8M414 19.9h5.1v20.3M440.7 18.6v10.1h7M47.6 21.8v26.6M67.3 21.8v8.8M75.6 28.7h9.5M75.6 21.1h9.5M106 21.1h-6.3v10.2M113.7 21.1h6.3v10.2h17.2v1.3M122.6 36.4h-2.6v5M149.9 24.9v8.9M160 21.1v10.2"/>
<path d="M167.6 34.5v1.9h22.9v-1.9M167.6 24.9v1.9M190.5 24.9v1.9M214 35.1h5.1M216.5 30h2.6M236.9 22.4v5.1M236.9 37.6h10.7M266.1 27.5h-2.6v5.1M273.7 32.6h3.2M302.9 24.3h5.1M306.7 21.8h1.3M343.5 29.4h8.3"/>
<path d="M361.9 21.8h-24.7v15.2h24.7M389.9 29.4h2.5M389.9 21.8v3.8h11.4v11.4h-10.1M439.4 21.1h1.3M449.6 21.1h18.4M457.8 26.2h2.6M459.1 26.2v5.1M468 31.3v5.1h-3.2M515 23v2.6h3.8M515 34.5v2.5h3.8M63.5 51.6h3.2M63.5 49.1h1.9"/>
<path d="M63.5 59.2h14M63.5 56.7h14M63.5 54.1h14M106 59.9h71.2M106 52.2h71.2M137.2 42.7v1.3M149.9 41.4v2.6h-27.3M395.6 50.3v26.7M414 40.2h8.9M416.6 50.3v8.9M443.2 59.9h3.2v15.8h1.3M446.4 50.3v1.9"/>
<path d="M466.7 59.9v13.3M21.6 77.6h1.3M30.5 77.6h1.2M123.2 66.8h88.9M446.4 67.5h4.4M457.8 78.3h1.3M461 67.5h17.2M19.7 99.9h1.9v7.6h1.3M22.2 85.3h8.9M31.7 99.9v7.6h-1.2M358.1 87.8h-6.3v10.8M365.8 87.8h6.3v10.8h21.6"/>
<path d="M406.4 98.6h1.3M407 92.2v7.7M466.7 83.4v2.5M478.2 82.7v3.2h-19.7M336.5 103.7h15.3M343.5 111.3h8.9M384.8 101.1h-12.7v2.6M407 107.5v1.3M417.8 106.2v2.6M428 106.2v2.6M438.1 106.2v2.6h-63.5M502.3 101.8h12"/>
<path d="M504.2 109.4h10.1M376.6 134.8h-15.9v2.5M399.4 134.8h3.2M399.4 139.9h5.7M402.6 127.8v8.3M419.7 138.6h-1.2v1.3h-5.8M447.7 133.5v10.2M492.8 134.8h-15.9v2.5M515.6 134.8h3.2M515.6 139.9h5.7M518.8 127.8v8.3M535.9 138.6h-1.2v1.3h-5.7"/>
<path d="M563.9 133.5v10.2M360.7 144.9h15.9M376.6 150v2.6M399.4 144.9h3.2v1.3h17.1v2.6M399.4 150h5.7M419.7 143.7h-1.2v6.3h-5.8M447.7 146.2v5.1M476.9 144.9h15.9M492.8 150v2.6M515.6 144.9h3.2v1.3h17.1v2.6M515.6 150h5.7M535.9 143.7h-1.2v6.3h-5.7"/>
<path d="M563.9 146.2v5.1M376.6 174.2h-16.6v2.5M399.4 174.2h3.2M399.4 179.2h5.7M402.6 167.2v8.2M419.7 178h-1.2v1.2h-5.8M447.7 172.9v10.1M492.8 174.2h-16.6v2.5M515.6 174.2h3.2M515.6 179.2h5.7M518.8 167.2v8.2M535.9 178h-1.2v1.2h-5.7"/>
<path d="M563.9 172.9v10.1M360 184.3h16.6M376.6 189.4v2.5M399.4 184.3h3.2v1.3h17.1v2.5M399.4 189.4h5.7M419.7 183h-1.2v6.4h-5.8M447.7 185.6v5.1M476.2 184.3h16.6M492.8 189.4v2.5M515.6 184.3h3.2v1.3h17.1v2.5M515.6 189.4h5.7M535.9 183h-1.2v6.4h-5.7"/>
<path d="M563.9 185.6v5.1M170.2 219.2v7.7h45.7M175.3 219.2v7.7M180.3 219.2v7.7M185.4 219.2v7.7M190.5 219.2v7.7M376.6 218h-15.9v2.5M399.4 218h3.2M402.6 211v8.2M447.7 216.7v10.2M492.8 218h-15.9v2.5M515.6 218h3.2"/>
<path d="M518.8 211v8.2M563.9 216.7v10.2M360.7 228.1h15.9M376.6 233.2v2.6M399.4 228.1h3.2v1.3h17.1v2.5M399.4 233.2h5.7M399.4 223.1h5.7M419.7 221.8h-1.2v1.3h-5.8M419.7 226.9h-1.2v6.3h-5.8M447.7 229.4v5.1M476.9 228.1h15.9M492.8 233.2v2.6"/>
<path d="M515.6 228.1h3.2v1.3h17.1v2.5M515.6 233.2h5.7M515.6 223.1h5.7M535.9 226.9h-1.2v6.3h-5.7M535.9 221.8h-1.2v1.3h-5.7M563.9 229.4v5.1M44.4 250.4v6.9h8.9M52.1 254.8h1.2M75.6 250.4v6.9h8.9M83.2 254.8h1.3M152.4 247.8v7.6M158.1 247.8v22.9h10.2"/>
<path d="M158.1 255.4h10.2M159.4 255.4v2.6M160.7 247.8h-14.7v5.1M160.7 250.4v2.5h7.6M167 258h1.3M238.8 245.3v5.1M376.6 257.3h-16.6v2.6M399.4 257.3h3.2M402.6 250.4v8.2M447.7 256.1v10.1M492.8 257.3h-16.6v2.6M515.6 257.3h3.2"/>
<path d="M518.8 250.4v8.2M563.9 256.1v10.1M50.8 262.4h2.5M81.9 262.4h2.6M102.2 274.5v2.5h11.5M112.4 274.5h1.3M144.8 260.5h23.5M144.8 263.1h23.5M158.1 265.6h10.2M360 267.5h16.6M376.6 272.6v2.5M399.4 267.5h3.2v1.3h17.1v2.5"/>
<path d="M399.4 272.6h5.7M399.4 262.4h5.7M419.7 261.2h-1.2v1.2h-5.8M419.7 266.2h-1.2v6.4h-5.8M447.7 268.8v5.1M476.2 267.5h16.6M492.8 272.6v2.5M515.6 267.5h3.2v1.3h17.1v2.5M515.6 272.6h5.7M515.6 262.4h5.7M535.9 261.2h-1.2v1.2h-5.7M535.9 266.2h-1.2v6.4h-5.7"/>
<path d="M563.9 268.8v5.1M37.5 291v7.6h12.7M402.6 294.2v8.2M447.7 299.9v10.1M518.8 294.2v8.2M563.9 299.9v10.1M207.6 301.8h.7M207.6 301.2v1.2M216.5 301.8h.7M216.5 301.2v1.2M225.4 301.8h.7M225.4 301.2v1.2"/>
<path d="M234.3 301.8h.6M234.3 301.2v1.2M360.7 311.3h15.9M376.6 301.2h-15.9v2.5M376.6 316.4v2.5M399.4 311.3h3.2v1.3h17.1v2.5M399.4 301.2h3.2M399.4 316.4h5.7M399.4 306.2h5.7M419.7 305h-1.2v1.2h-5.8M419.7 310h-1.2v6.4h-5.8M447.7 312.6v5.1"/>
<path d="M476.9 311.3h15.9M492.8 301.2h-15.9v2.5M492.8 316.4v2.5M515.6 301.2h3.2M515.6 311.3h3.2v1.3h17.1v2.5M515.6 316.4h5.7M515.6 306.2h5.7M535.9 305h-1.2v1.2h-5.7M535.9 310h-1.2v6.4h-5.7M563.9 312.6v5.1M38.7 332.3v2.5h8.9M44.4 339.9h3.2"/>
<path d="M44.4 337.4h3.2M46.4 332.3h1.2M74.3 332.3v2.5h8.9M80 339.9h3.2M80 337.4h3.2M81.9 332.3h1.3M125.7 339.3h7.6M141 333.5h-15.3v11.5M163.8 333.5h4.5M163.8 339.3h8.3M191.1 331.6v7.7M206.4 339.3h.6"/>
<path d="M206.4 331.6h17.8M206.4 336.7h6.3M206.4 334.2h12M224.2 339.3v7.6h-17.2M402.6 333.5v8.3M447.7 339.3v10.1M518.8 333.5v8.3M563.9 339.3v10.1M212.7 344.3v2.6M218.4 341.8v5.1M360 350.7h16.6M376.6 340.5h-16.6v2.6"/>
<path d="M376.6 355.8v2.5M399.4 350.7h3.2v1.3h17.1v2.5M399.4 340.5h3.2M399.4 355.8h5.7M399.4 345.6h5.7M419.7 344.3h-1.2v1.3h-5.8M419.7 349.4h-1.2v6.4h-5.8M447.7 352v5M476.2 350.7h16.6M492.8 355.8v2.5M492.8 340.5h-16.6v2.6M515.6 350.7h3.2v1.3h17.1v2.5"/>
<path d="M515.6 340.5h3.2M515.6 355.8h5.7M515.6 345.6h5.7M535.9 344.3h-1.2v1.3h-5.7M535.9 349.4h-1.2v6.4h-5.7M563.9 352v5M62.2 360.8h-2.5v31.8M69.8 360.8h2.6v31.8M105.4 360.8h-2.5v26.7M113 360.8h2.6v26.7M131.4 371h29.3M137.2 360.8h-5.8v2.6"/>
<path d="M137.2 368.5h23.5M138.4 378.6h7.6M144.8 376.1h1.2M151.8 363.4v2.5h8.9M159.4 363.4h1.3M180.3 371h29.2M186.1 368.5h23.4M186.1 360.8h-5.8v2.6M187.3 378.6h7.6M193.7 376.1h1.2M200.7 363.4v2.5h8.8M208.3 363.4h1.2"/>
<path d="M131.4 396.4h29.3M137.2 386.2h-5.8v2.6M137.2 393.9h23.5M151.8 388.8v2.5h8.9M159.4 388.8h1.3M180.3 396.4h29.2M186.1 386.2h-5.8v2.6M186.1 393.9h23.4M200.7 388.8v2.5h8.8M208.3 388.8h1.2M138.4 404h7.6M144.8 401.5h1.2"/>
<path d="M187.3 404h7.6M193.7 401.5h1.2"/>
</g>
<g fill="none" stroke="#000" stroke-width=".26">
<path d="M99.1 19.5h.7M99.5 19.5v1.3M95 27.1v1.1l.2 .2M321.3 89.9h.5l.1 .7M321.6 92.4h.4l.1 .8M321.9 90.1l-.6 .2v.3h.6M322.1 92.7l-.6 .2 .2 .3 .4-.1M322.5 89.4v1.1l.2 .1M322.5 99.5v1.1l.2 .2M322.7 91.9v1.1l.2 .2M321.3 110.2h.5l.1 .8M321.3 100h.5l.1 .8"/>
<path d="M321.6 112.7h.4l.1 .8M321.6 105.1h.4l.1 .8M321.9 110.4l-.6 .3v.2h.6M321.9 100.3l-.6 .2v.3h.6M322.1 113l-.6 .2 .2 .3h.4M322.1 105.4l-.6 .2 .2 .3 .4-.1M322.5 109.7v1.1l.2 .2M322.7 112.2v1.1l.2 .2M322.7 104.6v1.1l.2 .2M38.9 128.1h.6v-.5l-.6-.1v1.2M38.9 130.7l.6-.1v-.5l-.6-.1v1.3M319.1 131.3h.8"/>
<path d="M320.8 151.6h.7M321.4 153.2l.3-.3v1.2M321.4 155.5l.5-.1 .2 .4-.8 .9h.8M321.4 154.1h.7M409.4 143.3v1.3h.6M454.5 144.6v1.3h.6M525.6 143.3v1.3h.6M570.7 144.6v1.3h.6M38.7 168.8l.6-.1v-.5l-.6-.1v1.3M38.7 171.3h.6v-.5l-.6-.1v1.2M38.8 161.2l.7-.1v-.5l-.7-.1v1.3M39.8 176.4l.6-.1 .1-.4-.7-.2v1.3"/>
<path d="M39.8 178.9h.6l.1-.5-.7-.1v1.2M322.5 175.7h.7l-.4 .5 .4 .1-.1 .7-.6-.1M322.5 171l.4-.3v1.2M322.5 173.3l.5-.1 .2 .3-.7 1h.7M322.5 171.9h.7M322.7 168.2l.1-.1a.63 .63 0 0 1 .5 .7 .63 .63 0 0 1-.6 .5l-.2-.4zM322.8 178.2l-.3 .9h.8M323.1 178.7v.8M30.8 191.6h.6l.1-.5-.7-.1v1.2M31.3 189.1l.6-.1 .1-.4-.7-.2v1.3M39.8 181.5l.6-.1 .1-.5-.7-.1v1.3M40.1 184l.6-.1v-.4l-.6-.1v1.2"/>
<path d="M321.3 188.9h.5l.1 .8h-.6v-.4l.6-.1M321.3 183.8h.5l.1 .8M321.6 191.5h.4l.1 .7M321.6 186.4h.4l.1 .8M321.9 184.1l-.6 .2v.3h.6M322.1 191.7l-.6 .2 .2 .3h.4M322.1 186.6l-.6 .3 .2 .3 .4-.1M322.5 188.4v1.1l.2 .2M322.5 183.4v1l.2 .2M322.7 191v1.1l.2 .1M322.7 185.9v1.1l.2 .2M323.2 180.8h-.6l-.1 .6h.6l.1 .6h-.7"/>
<path d="M409.4 183.4l.6-.1 .1-.5-.7-.1v1.3M454.5 184.6h.6l.1-.5-.7-.1v1.3M454.8 184.6l.4 .7M525.6 183.4l.6-.1 .1-.5-.7-.1v1.3M570.7 184.6h.6l.1-.5-.7-.1v1.3M571 184.6l.4 .7M37.9 206.8l.5-.1v.8M37.9 206.6v.9M38.1 204.2h.5l.1 .7M38.1 204.1v.8M38.4 206.8l.5-.1 .1 .8M38.7 204.3l.5-.1v.7"/>
<path d="M52.9 206.2v1.1l.2 .2M52.9 203.7v1.1l.2 .1M409.4 226.5v1.3h.6M454.5 227.8v1.3h.6M525.6 226.5v1.3h.6M570.7 227.8v1.3h.6M291.9 252.5l.5-.1v.8M291.9 244.9l.5-.1v.8M291.9 244.7v.9M291.9 252.4v.8M291.9 260v.8M292.1 248.7l.5-.1 .1 .8"/>
<path d="M292.1 256.3l.5-.1 .1 .8M292.1 241.1l.5-.1 .1 .8M292.1 240.9v.9M292.1 248.6v.8M292.1 256.2v.8M292.4 252.5l.5-.1 .1 .8M292.4 244.9l.5-.1 .1 .8M292.7 248.7l.5-.1v.8M292.7 256.4l.5-.2v.8M292.7 241.1l.5-.1v.8M306.9 248.1v1.1l.2 .2M306.9 251.9v1.1l.2 .2"/>
<path d="M306.9 255.7v1.1l.2 .2M306.9 259.6v1l.2 .2M306.9 240.5v1.1l.2 .2M306.9 244.3v1.1l.2 .2M131.5 262.1l.7-.1v-.4l-.7-.1v1.2M291.9 260.1l.5-.1v.8M292.4 260.2l.5-.2 .1 .8M409.4 266.6l.6-.1 .1-.5-.7-.1v1.3M454.5 267.8h.6l.1-.5-.7-.1v1.2M454.8 267.8l.4 .6M525.6 266.6l.6-.1 .1-.5-.7-.1v1.3M570.7 267.8h.6l.1-.5-.7-.1v1.2"/>
<path d="M571 267.8l.4 .6M76.4 288.8l.6-.1v-.4l-.6-.2v1.3M130.5 285l.6-.1 .1-.5-.7-.1v1.3M291.9 298.2l.5-.1v.8M291.9 298.1v.8M292.1 294.4l.5-.1 .1 .8M292.1 294.3v.8M292.4 298.3l.5-.2 .1 .8M292.7 294.5l.5-.2v.8M306.9 297.7v1l.2 .2M306.9 293.8v1.1l.2 .2M291.9 313.5l.5-.1v.8"/>
<path d="M291.9 305.8h.5v.7M291.9 305.7v.8M291.9 313.3v.9M292.1 309.6h.5l.1 .8M292.1 302l.5-.1 .1 .8M292.1 301.9v.8M292.1 309.5v.9M292.4 313.5l.5-.1 .1 .8M292.4 305.9l.5-.1 .1 .7M292.7 309.7l.5-.1v.8M292.7 302.1l.5-.2v.8M306.9 312.9v1.1l.2 .2"/>
<path d="M306.9 309.1v1.1l.2 .2M306.9 305.3v1.1l.2 .1M306.9 301.5v1.1l.2 .1M409.4 309.7v1.3h.6M454.5 311v1.3h.6M525.6 309.7v1.3h.6M570.7 311v1.3h.6M113.4 339.1h1M164.2 335.8a.64 .64 0 0 1 .7 .6 .64 .64 0 0 1-.7 .6zM165.5 336.5h.9M218.8 333.8h.7M409.4 349.7h.6l.1-.5-.7-.1v1.3"/>
<path d="M454.5 351h.6l.1-.5-.7-.1v1.2M454.8 351l.4 .6M525.6 349.7h.6l.1-.5-.7-.1v1.3M570.7 351h.6l.1-.5-.7-.1v1.2M571 351l.4 .6M31.7 379l.7-.1v-.5l-.7-.1v1.3M31.7 371.3h.7v-.5l-.7-.1v1.2M31.7 373.9l.7-.1v-.5l-.7-.1v1.3M31.7 376.4h.7v-.5l-.7-.1v1.2M31.7 368.8l.7-.1v-.4l-.7-.2v1.3M158.7 378.3h.7M207.8 374.6l.5-.1 .2 .3-.8 1h.8"/>
<path d="M208.8 377.4l.4-.4v1.3M208.8 378.3h.7M353.2 363.1v1.2M31.7 381.5l.7-.1v-.4l-.7-.2v1.3M33 384h.6v-.5l-.6-.1v1.2M33 386.6l.6-.1v-.5l-.6-.1v1.3M33.1 389.1h.7v-.5l-.7-.1v1.2M33.1 391.7l.7-.1v-.5l-.7-.1v1.3M160.1 402.8l.4-.4v1.3M160.1 400l.5-.1 .2 .3-.8 1h.8M160.1 403.7h.7M207.8 402.8l.3-.4v1.3"/>
<path d="M207.8 400l.5-.1 .2 .3-.8 1h.8M207.8 403.7h.7"/>
</g>
<g fill="#008400" stroke="#008400" stroke-width=".26">
<circle cx="447.7" cy="180.5" r=".51"/>
<circle cx="72.4" cy="392.6" r=".51"/>
<circle cx="447.7" cy="231.9" r=".51"/>
<circle cx="72.4" cy="369.7" r=".51"/>
<circle cx="402.6" cy="218" r=".51"/>
<circle cx="419.7" cy="268.8" r=".51"/>
<circle cx="447.7" cy="258.6" r=".51"/>
<circle cx="447.7" cy="261.2" r=".51"/>
<circle cx="26.7" cy="85.3" r=".51"/>
<circle cx="447.7" cy="263.7" r=".51"/>
<circle cx="31.1" cy="77.6" r=".51"/>
<circle cx="447.7" cy="271.3" r=".51"/>
<circle cx="395.6" cy="59.2" r=".51"/>
<circle cx="114.9" cy="59.9" r=".51"/>
<circle cx="238.8" cy="247.8" r=".51"/>
<circle cx="125.7" cy="333.5" r=".51"/>
<circle cx="518.8" cy="301.2" r=".51"/>
<circle cx="447.7" cy="148.8" r=".51"/>
<circle cx="158.1" cy="265.6" r=".51"/>
<circle cx="72.4" cy="377.4" r=".51"/>
<circle cx="419.7" cy="146.2" r=".51"/>
<circle cx="132.7" cy="59.9" r=".51"/>
<circle cx="212.7" cy="346.9" r=".51"/>
<circle cx="238.8" cy="250.4" r=".51"/>
<circle cx="447.7" cy="136.1" r=".51"/>
<circle cx="402.6" cy="228.1" r=".51"/>
<circle cx="218.4" cy="346.9" r=".51"/>
<circle cx="393.7" cy="108.8" r=".51"/>
<circle cx="224.2" cy="346.9" r=".51"/>
<circle cx="360" cy="340.5" r=".51"/>
<circle cx="72.4" cy="379.9" r=".51"/>
<circle cx="141.6" cy="59.9" r=".51"/>
<circle cx="360.7" cy="301.2" r=".51"/>
<circle cx="447.7" cy="178" r=".51"/>
<circle cx="72.4" cy="372.3" r=".51"/>
<circle cx="447.7" cy="221.8" r=".51"/>
<circle cx="447.7" cy="219.2" r=".51"/>
<circle cx="391.2" cy="29.4" r=".51"/>
<circle cx="419.7" cy="229.4" r=".51"/>
<circle cx="123.8" cy="59.9" r=".51"/>
<circle cx="447.7" cy="188.1" r=".51"/>
<circle cx="72.4" cy="374.8" r=".51"/>
<circle cx="447.7" cy="344.3" r=".51"/>
<circle cx="447.7" cy="224.3" r=".51"/>
<circle cx="125.7" cy="339.3" r=".51"/>
<circle cx="447.7" cy="175.4" r=".51"/>
<circle cx="273.7" cy="32.6" r=".51"/>
<circle cx="419.7" cy="185.6" r=".51"/>
<circle cx="125.7" cy="337.4" r=".51"/>
<circle cx="447.7" cy="141.1" r=".51"/>
<circle cx="125.7" cy="335.4" r=".51"/>
<circle cx="447.7" cy="138.6" r=".51"/>
<circle cx="563.9" cy="175.4" r=".51"/>
<circle cx="514.3" cy="109.4" r=".51"/>
<circle cx="535.9" cy="146.2" r=".51"/>
<circle cx="47" cy="332.3" r=".51"/>
<circle cx="563.9" cy="188.1" r=".51"/>
<circle cx="518.8" cy="134.8" r=".51"/>
<circle cx="74.3" cy="332.3" r=".51"/>
<circle cx="563.9" cy="180.5" r=".51"/>
<circle cx="563.9" cy="178" r=".51"/>
<circle cx="563.9" cy="136.1" r=".51"/>
<circle cx="504.2" cy="101.8" r=".51"/>
<circle cx="535.9" cy="185.6" r=".51"/>
<circle cx="563.9" cy="231.9" r=".51"/>
<circle cx="47.6" cy="30.6" r=".51"/>
<circle cx="563.9" cy="224.3" r=".51"/>
<circle cx="47.6" cy="39.5" r=".51"/>
<circle cx="563.9" cy="221.8" r=".51"/>
<circle cx="563.9" cy="219.2" r=".51"/>
<circle cx="518.8" cy="350.7" r=".51"/>
<circle cx="159.4" cy="255.4" r=".51"/>
<circle cx="113" cy="274.5" r=".51"/>
<circle cx="47.6" cy="48.4" r=".51"/>
<circle cx="44.5" cy="254.8" r=".51"/>
<circle cx="158.1" cy="255.4" r=".51"/>
<circle cx="75.6" cy="254.8" r=".51"/>
<circle cx="351.8" cy="111.3" r=".51"/>
<circle cx="384.2" cy="101.1" r=".51"/>
<circle cx="535.9" cy="229.4" r=".51"/>
<circle cx="389.9" cy="25.6" r=".51"/>
<circle cx="343.5" cy="103.7" r=".51"/>
<circle cx="372.1" cy="98.6" r=".51"/>
<circle cx="563.9" cy="148.8" r=".51"/>
<circle cx="372.1" cy="101.1" r=".51"/>
<circle cx="351.8" cy="103.7" r=".51"/>
<circle cx="563.9" cy="141.1" r=".51"/>
<circle cx="563.9" cy="138.6" r=".51"/>
<circle cx="177.2" cy="59.9" r=".51"/>
<circle cx="215.9" cy="226.9" r=".51"/>
<circle cx="535.9" cy="352" r=".51"/>
<circle cx="518.8" cy="340.5" r=".51"/>
<circle cx="447.7" cy="354.5" r=".51"/>
<circle cx="374.6" cy="101.1" r=".51"/>
<circle cx="447.7" cy="346.9" r=".51"/>
<circle cx="72.4" cy="385" r=".51"/>
<circle cx="447.7" cy="341.8" r=".51"/>
<circle cx="419.7" cy="352" r=".51"/>
<circle cx="563.9" cy="341.8" r=".51"/>
<circle cx="447.7" cy="315.1" r=".51"/>
<circle cx="21.6" cy="99.9" r=".51"/>
<circle cx="31.7" cy="107.5" r=".51"/>
<circle cx="447.7" cy="307.5" r=".51"/>
<circle cx="22.2" cy="77.6" r=".51"/>
<circle cx="447.7" cy="305" r=".51"/>
<circle cx="518.8" cy="311.3" r=".51"/>
<circle cx="447.7" cy="302.4" r=".51"/>
<circle cx="59.7" cy="360.8" r=".51"/>
<circle cx="203.2" cy="226.9" r=".51"/>
<circle cx="113.7" cy="277" r=".51"/>
<circle cx="563.9" cy="271.3" r=".51"/>
<circle cx="384.2" cy="108.8" r=".51"/>
<circle cx="563.9" cy="263.7" r=".51"/>
<circle cx="563.9" cy="261.2" r=".51"/>
<circle cx="563.9" cy="258.6" r=".51"/>
<circle cx="535.9" cy="268.8" r=".51"/>
<circle cx="563.9" cy="315.1" r=".51"/>
<circle cx="419.7" cy="312.6" r=".51"/>
<circle cx="563.9" cy="307.5" r=".51"/>
<circle cx="563.9" cy="305" r=".51"/>
<circle cx="263.5" cy="32.6" r=".51"/>
<circle cx="563.9" cy="302.4" r=".51"/>
<circle cx="535.9" cy="312.6" r=".51"/>
<circle cx="563.9" cy="354.5" r=".51"/>
<circle cx="563.9" cy="346.9" r=".51"/>
<circle cx="563.9" cy="344.3" r=".51"/>
<circle cx="144.8" cy="368.5" r=".51"/>
<circle cx="146.1" cy="247.8" r=".51"/>
<circle cx="167.6" cy="24.9" r=".51"/>
<circle cx="361.9" cy="37" r=".51"/>
<circle cx="151.8" cy="363.4" r=".51"/>
<circle cx="361.9" cy="29.4" r=".51"/>
<circle cx="401.3" cy="37" r=".51"/>
<circle cx="402.6" cy="174.2" r=".51"/>
<circle cx="83.8" cy="254.8" r=".51"/>
<circle cx="446.4" cy="59.9" r=".51"/>
<circle cx="351.8" cy="29.4" r=".51"/>
<circle cx="478.2" cy="85.9" r=".51"/>
<circle cx="138.4" cy="371" r=".51"/>
<circle cx="191.8" cy="66.8" r=".51"/>
<circle cx="402.6" cy="134.8" r=".51"/>
<circle cx="466.7" cy="67.5" r=".51"/>
<circle cx="200.7" cy="388.8" r=".51"/>
<circle cx="199.4" cy="66.8" r=".51"/>
<circle cx="208.9" cy="388.8" r=".51"/>
<circle cx="176.5" cy="66.8" r=".51"/>
<circle cx="440.7" cy="21.1" r=".51"/>
<circle cx="83.8" cy="28.7" r=".51"/>
<circle cx="135.9" cy="66.8" r=".51"/>
<circle cx="161.3" cy="66.8" r=".51"/>
<circle cx="187.3" cy="396.4" r=".51"/>
<circle cx="193.7" cy="393.9" r=".51"/>
<circle cx="83.8" cy="21.1" r=".51"/>
<circle cx="459.1" cy="26.2" r=".51"/>
<circle cx="168.9" cy="66.8" r=".51"/>
<circle cx="518.8" cy="144.9" r=".51"/>
<circle cx="393.7" cy="98.6" r=".51"/>
<circle cx="395.6" cy="77" r=".51"/>
<circle cx="395.6" cy="68.1" r=".51"/>
<circle cx="402.6" cy="301.2" r=".51"/>
<circle cx="184.1" cy="66.8" r=".51"/>
<circle cx="190.5" cy="24.9" r=".51"/>
<circle cx="160" cy="363.4" r=".51"/>
<circle cx="518.8" cy="218" r=".51"/>
<circle cx="115.6" cy="387.5" r=".51"/>
<circle cx="200.7" cy="363.4" r=".51"/>
<circle cx="115.6" cy="379.9" r=".51"/>
<circle cx="67.3" cy="30.6" r=".51"/>
<circle cx="115.6" cy="377.4" r=".51"/>
<circle cx="160" cy="388.8" r=".51"/>
<circle cx="115.6" cy="374.8" r=".51"/>
<circle cx="167.6" cy="258" r=".51"/>
<circle cx="115.6" cy="372.3" r=".51"/>
<circle cx="115.6" cy="369.7" r=".51"/>
<circle cx="115.6" cy="382.4" r=".51"/>
<circle cx="208.9" cy="363.4" r=".51"/>
<circle cx="151.8" cy="388.8" r=".51"/>
<circle cx="82.6" cy="332.3" r=".51"/>
<circle cx="402.6" cy="144.9" r=".51"/>
<circle cx="518.8" cy="184.3" r=".51"/>
<circle cx="144.8" cy="393.9" r=".51"/>
<circle cx="138.4" cy="396.4" r=".51"/>
<circle cx="131.4" cy="386.2" r=".51"/>
<circle cx="187.3" cy="371" r=".51"/>
<circle cx="179.1" cy="36.4" r=".51"/>
<circle cx="180.3" cy="360.8" r=".51"/>
<circle cx="407" cy="108.8" r=".51"/>
<circle cx="402.6" cy="311.3" r=".51"/>
<circle cx="102.9" cy="385" r=".51"/>
<circle cx="102.9" cy="382.4" r=".51"/>
<circle cx="131.4" cy="360.8" r=".51"/>
<circle cx="102.9" cy="379.9" r=".51"/>
<circle cx="191.1" cy="331.6" r=".51"/>
<circle cx="102.9" cy="377.4" r=".51"/>
<circle cx="193.7" cy="368.5" r=".51"/>
<circle cx="102.9" cy="374.8" r=".51"/>
<circle cx="518.8" cy="174.2" r=".51"/>
<circle cx="102.9" cy="372.3" r=".51"/>
<circle cx="102.9" cy="369.7" r=".51"/>
<circle cx="402.6" cy="340.5" r=".51"/>
<circle cx="115.6" cy="385" r=".51"/>
<circle cx="159.4" cy="52.2" r=".51"/>
<circle cx="150.5" cy="52.2" r=".51"/>
<circle cx="225.4" cy="301.8" r=".51"/>
<circle cx="417.8" cy="108.8" r=".51"/>
<circle cx="216.5" cy="301.8" r=".51"/>
<circle cx="518.8" cy="267.5" r=".51"/>
<circle cx="428" cy="108.8" r=".51"/>
<circle cx="207.6" cy="301.8" r=".51"/>
<circle cx="72.4" cy="390.1" r=".51"/>
<circle cx="438.1" cy="98.6" r=".51"/>
<circle cx="234.3" cy="301.8" r=".51"/>
<circle cx="417.8" cy="98.6" r=".51"/>
<circle cx="59.7" cy="369.7" r=".51"/>
<circle cx="168.3" cy="52.2" r=".51"/>
<circle cx="59.7" cy="372.3" r=".51"/>
<circle cx="152.4" cy="263.1" r=".51"/>
<circle cx="402.6" cy="267.5" r=".51"/>
<circle cx="59.7" cy="374.8" r=".51"/>
<circle cx="123.2" cy="66.8" r=".51"/>
<circle cx="106" cy="52.2" r=".51"/>
<circle cx="150.5" cy="59.9" r=".51"/>
<circle cx="159.4" cy="59.9" r=".51"/>
<circle cx="402.6" cy="257.3" r=".51"/>
<circle cx="360" cy="257.3" r=".51"/>
<circle cx="168.3" cy="59.9" r=".51"/>
<circle cx="191.1" cy="334.2" r=".51"/>
<circle cx="360.7" cy="218" r=".51"/>
<circle cx="72.4" cy="382.4" r=".51"/>
<circle cx="191.1" cy="336.7" r=".51"/>
<circle cx="419.1" cy="19.9" r=".51"/>
<circle cx="114.9" cy="52.2" r=".51"/>
<circle cx="360" cy="174.2" r=".51"/>
<circle cx="123.8" cy="52.2" r=".51"/>
<circle cx="416.6" cy="59.2" r=".51"/>
<circle cx="132.7" cy="52.2" r=".51"/>
<circle cx="72.4" cy="387.5" r=".51"/>
<circle cx="360.7" cy="134.8" r=".51"/>
<circle cx="141.6" cy="52.2" r=".51"/>
<circle cx="180.3" cy="386.2" r=".51"/>
<circle cx="146.1" cy="260.5" r=".51"/>
<circle cx="158.1" cy="247.8" r=".51"/>
<circle cx="419.1" cy="40.2" r=".51"/>
<circle cx="152.4" cy="247.8" r=".51"/>
<circle cx="122.6" cy="36.4" r=".51"/>
<circle cx="120" cy="36.4" r=".51"/>
<circle cx="518.8" cy="257.3" r=".51"/>
<circle cx="50.2" cy="298.6" r=".51"/>
<circle cx="402.6" cy="184.3" r=".51"/>
<circle cx="52.7" cy="254.8" r=".51"/>
<circle cx="120" cy="31.3" r=".51"/>
<circle cx="137.2" cy="31.3" r=".51"/>
<circle cx="518.8" cy="228.1" r=".51"/>
<circle cx="137.2" cy="44" r=".51"/>
<circle cx="446.4" cy="67.5" r=".51"/>
<circle cx="149.9" cy="31.3" r=".51"/>
<circle cx="149.9" cy="44" r=".51"/>
<circle cx="37.5" cy="293.5" r=".51"/>
<circle cx="59.7" cy="387.5" r=".51"/>
<circle cx="458.5" cy="78.3" r=".51"/>
<circle cx="102.9" cy="360.8" r=".51"/>
<circle cx="407.7" cy="19.9" r=".51"/>
<circle cx="466.7" cy="85.9" r=".51"/>
<circle cx="59.7" cy="377.4" r=".51"/>
<circle cx="59.7" cy="379.9" r=".51"/>
<circle cx="38.7" cy="332.3" r=".51"/>
<circle cx="59.7" cy="382.4" r=".51"/>
<circle cx="407" cy="98.6" r=".51"/>
<circle cx="59.7" cy="385" r=".51"/>
<circle cx="402.6" cy="350.7" r=".51"/>
<circle cx="59.7" cy="390.1" r=".51"/>
</g>
<g fill="none" stroke="#000084" stroke-width=".26">
<path d="M361.3 25l1.3 1.2M362.6 25l-1.3 1.2M457.2 30.7l1.2 1.2M458.4 30.7l-1.2 1.2M466.1 51.6l1.2 1.2M467.3 51.6l-1.2 1.2M447.1 80.2l1.2 1.2M448.3 80.2l-1.2 1.2M167.7 244.7l1.2 1.2M168.9 244.7l-1.2 1.2M101 346.9l1.2 1.2M102.2 346.9l-1.2 1.2"/>
<path d="M111.2 341.8l1.2 1.2M112.4 341.8l-1.2 1.2M163.2 340.6l1.2 1.2M163.2 342.5l1.2 1.2M163.2 344.4l1.2 1.2M164.4 340.6l-1.2 1.2M164.4 342.5l-1.2 1.2M164.4 344.4l-1.2 1.2"/>
</g>
<use href="#words"/>
</svg>
